VERSION 5.7 ;
BUSBITCHARS "[]" ;
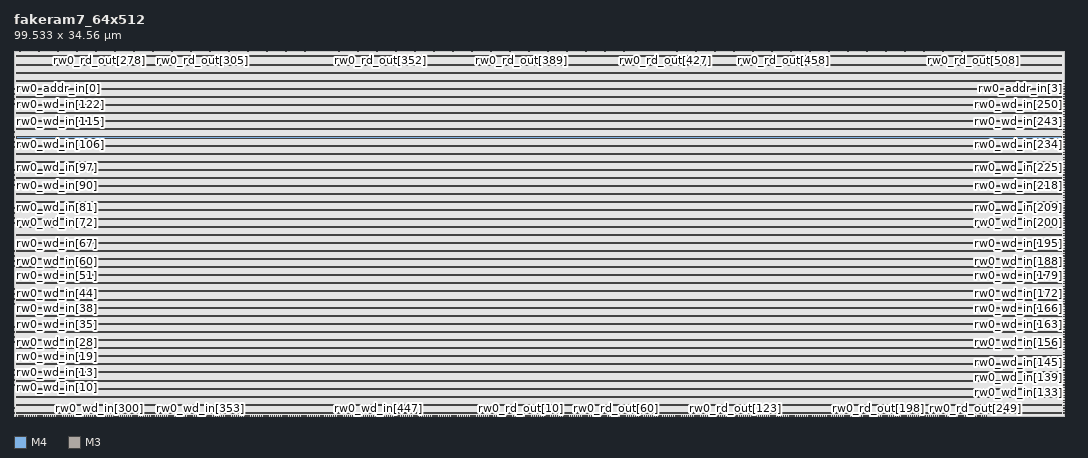
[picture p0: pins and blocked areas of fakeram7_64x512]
MACRO fakeram7_64x512
  FOREIGN fakeram7_64x512 0 0 ;
  SYMMETRY X Y R90 ;
  SIZE 99.533 BY 34.560 ;
  CLASS BLOCK ;
  PIN rw0_wd_in[0]
    DIRECTION INPUT ;
    USE SIGNAL ;
    SHAPE ABUTMENT ;
    PORT
      LAYER M4 ;
      RECT 0.000 0.276 0.072 0.300 ;
    END
  END rw0_wd_in[0]
  PIN rw0_wd_in[1]
    DIRECTION INPUT ;
    USE SIGNAL ;
    SHAPE ABUTMENT ;
    PORT
      LAYER M4 ;
      RECT 0.000 0.516 0.072 0.540 ;
    END
  END rw0_wd_in[1]
  PIN rw0_wd_in[2]
    DIRECTION INPUT ;
    USE SIGNAL ;
    SHAPE ABUTMENT ;
    PORT
      LAYER M4 ;
      RECT 0.000 0.756 0.072 0.780 ;
    END
  END rw0_wd_in[2]
  PIN rw0_wd_in[3]
    DIRECTION INPUT ;
    USE SIGNAL ;
    SHAPE ABUTMENT ;
    PORT
      LAYER M4 ;
      RECT 0.000 0.996 0.072 1.020 ;
    END
  END rw0_wd_in[3]
  PIN rw0_wd_in[4]
    DIRECTION INPUT ;
    USE SIGNAL ;
    SHAPE ABUTMENT ;
    PORT
      LAYER M4 ;
      RECT 0.000 1.236 0.072 1.260 ;
    END
  END rw0_wd_in[4]
  PIN rw0_wd_in[5]
    DIRECTION INPUT ;
    USE SIGNAL ;
    SHAPE ABUTMENT ;
    PORT
      LAYER M4 ;
      RECT 0.000 1.476 0.072 1.500 ;
    END
  END rw0_wd_in[5]
  PIN rw0_wd_in[6]
    DIRECTION INPUT ;
    USE SIGNAL ;
    SHAPE ABUTMENT ;
    PORT
      LAYER M4 ;
      RECT 0.000 1.716 0.072 1.740 ;
    END
  END rw0_wd_in[6]
  PIN rw0_wd_in[7]
    DIRECTION INPUT ;
    USE SIGNAL ;
    SHAPE ABUTMENT ;
    PORT
      LAYER M4 ;
      RECT 0.000 1.956 0.072 1.980 ;
    END
  END rw0_wd_in[7]
  PIN rw0_wd_in[8]
    DIRECTION INPUT ;
    USE SIGNAL ;
    SHAPE ABUTMENT ;
    PORT
      LAYER M4 ;
      RECT 0.000 2.196 0.072 2.220 ;
    END
  END rw0_wd_in[8]
  PIN rw0_wd_in[9]
    DIRECTION INPUT ;
    USE SIGNAL ;
    SHAPE ABUTMENT ;
    PORT
      LAYER M4 ;
      RECT 0.000 2.436 0.072 2.460 ;
    END
  END rw0_wd_in[9]
  PIN rw0_wd_in[10]
    DIRECTION INPUT ;
    USE SIGNAL ;
    SHAPE ABUTMENT ;
    PORT
      LAYER M4 ;
      RECT 0.000 2.676 0.072 2.700 ;
    END
  END rw0_wd_in[10]
  PIN rw0_wd_in[11]
    DIRECTION INPUT ;
    USE SIGNAL ;
    SHAPE ABUTMENT ;
    PORT
      LAYER M4 ;
      RECT 0.000 2.916 0.072 2.940 ;
    END
  END rw0_wd_in[11]
  PIN rw0_wd_in[12]
    DIRECTION INPUT ;
    USE SIGNAL ;
    SHAPE ABUTMENT ;
    PORT
      LAYER M4 ;
      RECT 0.000 3.156 0.072 3.180 ;
    END
  END rw0_wd_in[12]
  PIN rw0_wd_in[13]
    DIRECTION INPUT ;
    USE SIGNAL ;
    SHAPE ABUTMENT ;
    PORT
      LAYER M4 ;
      RECT 0.000 3.396 0.072 3.420 ;
    END
  END rw0_wd_in[13]
  PIN rw0_wd_in[14]
    DIRECTION INPUT ;
    USE SIGNAL ;
    SHAPE ABUTMENT ;
    PORT
      LAYER M4 ;
      RECT 0.000 3.636 0.072 3.660 ;
    END
  END rw0_wd_in[14]
  PIN rw0_wd_in[15]
    DIRECTION INPUT ;
    USE SIGNAL ;
    SHAPE ABUTMENT ;
    PORT
      LAYER M4 ;
      RECT 0.000 3.876 0.072 3.900 ;
    END
  END rw0_wd_in[15]
  PIN rw0_wd_in[16]
    DIRECTION INPUT ;
    USE SIGNAL ;
    SHAPE ABUTMENT ;
    PORT
      LAYER M4 ;
      RECT 0.000 4.116 0.072 4.140 ;
    END
  END rw0_wd_in[16]
  PIN rw0_wd_in[17]
    DIRECTION INPUT ;
    USE SIGNAL ;
    SHAPE ABUTMENT ;
    PORT
      LAYER M4 ;
      RECT 0.000 4.356 0.072 4.380 ;
    END
  END rw0_wd_in[17]
  PIN rw0_wd_in[18]
    DIRECTION INPUT ;
    USE SIGNAL ;
    SHAPE ABUTMENT ;
    PORT
      LAYER M4 ;
      RECT 0.000 4.596 0.072 4.620 ;
    END
  END rw0_wd_in[18]
  PIN rw0_wd_in[19]
    DIRECTION INPUT ;
    USE SIGNAL ;
    SHAPE ABUTMENT ;
    PORT
      LAYER M4 ;
      RECT 0.000 4.836 0.072 4.860 ;
    END
  END rw0_wd_in[19]
  PIN rw0_wd_in[20]
    DIRECTION INPUT ;
    USE SIGNAL ;
    SHAPE ABUTMENT ;
    PORT
      LAYER M4 ;
      RECT 0.000 5.076 0.072 5.100 ;
    END
  END rw0_wd_in[20]
  PIN rw0_wd_in[21]
    DIRECTION INPUT ;
    USE SIGNAL ;
    SHAPE ABUTMENT ;
    PORT
      LAYER M4 ;
      RECT 0.000 5.316 0.072 5.340 ;
    END
  END rw0_wd_in[21]
  PIN rw0_wd_in[22]
    DIRECTION INPUT ;
    USE SIGNAL ;
    SHAPE ABUTMENT ;
    PORT
      LAYER M4 ;
      RECT 0.000 5.556 0.072 5.580 ;
    END
  END rw0_wd_in[22]
  PIN rw0_wd_in[23]
    DIRECTION INPUT ;
    USE SIGNAL ;
    SHAPE ABUTMENT ;
    PORT
      LAYER M4 ;
      RECT 0.000 5.796 0.072 5.820 ;
    END
  END rw0_wd_in[23]
  PIN rw0_wd_in[24]
    DIRECTION INPUT ;
    USE SIGNAL ;
    SHAPE ABUTMENT ;
    PORT
      LAYER M4 ;
      RECT 0.000 6.036 0.072 6.060 ;
    END
  END rw0_wd_in[24]
  PIN rw0_wd_in[25]
    DIRECTION INPUT ;
    USE SIGNAL ;
    SHAPE ABUTMENT ;
    PORT
      LAYER M4 ;
      RECT 0.000 6.276 0.072 6.300 ;
    END
  END rw0_wd_in[25]
  PIN rw0_wd_in[26]
    DIRECTION INPUT ;
    USE SIGNAL ;
    SHAPE ABUTMENT ;
    PORT
      LAYER M4 ;
      RECT 0.000 6.516 0.072 6.540 ;
    END
  END rw0_wd_in[26]
  PIN rw0_wd_in[27]
    DIRECTION INPUT ;
    USE SIGNAL ;
    SHAPE ABUTMENT ;
    PORT
      LAYER M4 ;
      RECT 0.000 6.756 0.072 6.780 ;
    END
  END rw0_wd_in[27]
  PIN rw0_wd_in[28]
    DIRECTION INPUT ;
    USE SIGNAL ;
    SHAPE ABUTMENT ;
    PORT
      LAYER M4 ;
      RECT 0.000 6.996 0.072 7.020 ;
    END
  END rw0_wd_in[28]
  PIN rw0_wd_in[29]
    DIRECTION INPUT ;
    USE SIGNAL ;
    SHAPE ABUTMENT ;
    PORT
      LAYER M4 ;
      RECT 0.000 7.236 0.072 7.260 ;
    END
  END rw0_wd_in[29]
  PIN rw0_wd_in[30]
    DIRECTION INPUT ;
    USE SIGNAL ;
    SHAPE ABUTMENT ;
    PORT
      LAYER M4 ;
      RECT 0.000 7.476 0.072 7.500 ;
    END
  END rw0_wd_in[30]
  PIN rw0_wd_in[31]
    DIRECTION INPUT ;
    USE SIGNAL ;
    SHAPE ABUTMENT ;
    PORT
      LAYER M4 ;
      RECT 0.000 7.716 0.072 7.740 ;
    END
  END rw0_wd_in[31]
  PIN rw0_wd_in[32]
    DIRECTION INPUT ;
    USE SIGNAL ;
    SHAPE ABUTMENT ;
    PORT
      LAYER M4 ;
      RECT 0.000 7.956 0.072 7.980 ;
    END
  END rw0_wd_in[32]
  PIN rw0_wd_in[33]
    DIRECTION INPUT ;
    USE SIGNAL ;
    SHAPE ABUTMENT ;
    PORT
      LAYER M4 ;
      RECT 0.000 8.196 0.072 8.220 ;
    END
  END rw0_wd_in[33]
  PIN rw0_wd_in[34]
    DIRECTION INPUT ;
    USE SIGNAL ;
    SHAPE ABUTMENT ;
    PORT
      LAYER M4 ;
      RECT 0.000 8.436 0.072 8.460 ;
    END
  END rw0_wd_in[34]
  PIN rw0_wd_in[35]
    DIRECTION INPUT ;
    USE SIGNAL ;
    SHAPE ABUTMENT ;
    PORT
      LAYER M4 ;
      RECT 0.000 8.676 0.072 8.700 ;
    END
  END rw0_wd_in[35]
  PIN rw0_wd_in[36]
    DIRECTION INPUT ;
    USE SIGNAL ;
    SHAPE ABUTMENT ;
    PORT
      LAYER M4 ;
      RECT 0.000 8.916 0.072 8.940 ;
    END
  END rw0_wd_in[36]
  PIN rw0_wd_in[37]
    DIRECTION INPUT ;
    USE SIGNAL ;
    SHAPE ABUTMENT ;
    PORT
      LAYER M4 ;
      RECT 0.000 9.156 0.072 9.180 ;
    END
  END rw0_wd_in[37]
  PIN rw0_wd_in[38]
    DIRECTION INPUT ;
    USE SIGNAL ;
    SHAPE ABUTMENT ;
    PORT
      LAYER M4 ;
      RECT 0.000 9.396 0.072 9.420 ;
    END
  END rw0_wd_in[38]
  PIN rw0_wd_in[39]
    DIRECTION INPUT ;
    USE SIGNAL ;
    SHAPE ABUTMENT ;
    PORT
      LAYER M4 ;
      RECT 0.000 9.636 0.072 9.660 ;
    END
  END rw0_wd_in[39]
  PIN rw0_wd_in[40]
    DIRECTION INPUT ;
    USE SIGNAL ;
    SHAPE ABUTMENT ;
    PORT
      LAYER M4 ;
      RECT 0.000 9.876 0.072 9.900 ;
    END
  END rw0_wd_in[40]
  PIN rw0_wd_in[41]
    DIRECTION INPUT ;
    USE SIGNAL ;
    SHAPE ABUTMENT ;
    PORT
      LAYER M4 ;
      RECT 0.000 10.116 0.072 10.140 ;
    END
  END rw0_wd_in[41]
  PIN rw0_wd_in[42]
    DIRECTION INPUT ;
    USE SIGNAL ;
    SHAPE ABUTMENT ;
    PORT
      LAYER M4 ;
      RECT 0.000 10.356 0.072 10.380 ;
    END
  END rw0_wd_in[42]
  PIN rw0_wd_in[43]
    DIRECTION INPUT ;
    USE SIGNAL ;
    SHAPE ABUTMENT ;
    PORT
      LAYER M4 ;
      RECT 0.000 10.596 0.072 10.620 ;
    END
  END rw0_wd_in[43]
  PIN rw0_wd_in[44]
    DIRECTION INPUT ;
    USE SIGNAL ;
    SHAPE ABUTMENT ;
    PORT
      LAYER M4 ;
      RECT 0.000 10.836 0.072 10.860 ;
    END
  END rw0_wd_in[44]
  PIN rw0_wd_in[45]
    DIRECTION INPUT ;
    USE SIGNAL ;
    SHAPE ABUTMENT ;
    PORT
      LAYER M4 ;
      RECT 0.000 11.076 0.072 11.100 ;
    END
  END rw0_wd_in[45]
  PIN rw0_wd_in[46]
    DIRECTION INPUT ;
    USE SIGNAL ;
    SHAPE ABUTMENT ;
    PORT
      LAYER M4 ;
      RECT 0.000 11.316 0.072 11.340 ;
    END
  END rw0_wd_in[46]
  PIN rw0_wd_in[47]
    DIRECTION INPUT ;
    USE SIGNAL ;
    SHAPE ABUTMENT ;
    PORT
      LAYER M4 ;
      RECT 0.000 11.556 0.072 11.580 ;
    END
  END rw0_wd_in[47]
  PIN rw0_wd_in[48]
    DIRECTION INPUT ;
    USE SIGNAL ;
    SHAPE ABUTMENT ;
    PORT
      LAYER M4 ;
      RECT 0.000 11.796 0.072 11.820 ;
    END
  END rw0_wd_in[48]
  PIN rw0_wd_in[49]
    DIRECTION INPUT ;
    USE SIGNAL ;
    SHAPE ABUTMENT ;
    PORT
      LAYER M4 ;
      RECT 0.000 12.036 0.072 12.060 ;
    END
  END rw0_wd_in[49]
  PIN rw0_wd_in[50]
    DIRECTION INPUT ;
    USE SIGNAL ;
    SHAPE ABUTMENT ;
    PORT
      LAYER M4 ;
      RECT 0.000 12.276 0.072 12.300 ;
    END
  END rw0_wd_in[50]
  PIN rw0_wd_in[51]
    DIRECTION INPUT ;
    USE SIGNAL ;
    SHAPE ABUTMENT ;
    PORT
      LAYER M4 ;
      RECT 0.000 12.516 0.072 12.540 ;
    END
  END rw0_wd_in[51]
  PIN rw0_wd_in[52]
    DIRECTION INPUT ;
    USE SIGNAL ;
    SHAPE ABUTMENT ;
    PORT
      LAYER M4 ;
      RECT 0.000 12.756 0.072 12.780 ;
    END
  END rw0_wd_in[52]
  PIN rw0_wd_in[53]
    DIRECTION INPUT ;
    USE SIGNAL ;
    SHAPE ABUTMENT ;
    PORT
      LAYER M4 ;
      RECT 0.000 12.996 0.072 13.020 ;
    END
  END rw0_wd_in[53]
  PIN rw0_wd_in[54]
    DIRECTION INPUT ;
    USE SIGNAL ;
    SHAPE ABUTMENT ;
    PORT
      LAYER M4 ;
      RECT 0.000 13.236 0.072 13.260 ;
    END
  END rw0_wd_in[54]
  PIN rw0_wd_in[55]
    DIRECTION INPUT ;
    USE SIGNAL ;
    SHAPE ABUTMENT ;
    PORT
      LAYER M4 ;
      RECT 0.000 13.476 0.072 13.500 ;
    END
  END rw0_wd_in[55]
  PIN rw0_wd_in[56]
    DIRECTION INPUT ;
    USE SIGNAL ;
    SHAPE ABUTMENT ;
    PORT
      LAYER M4 ;
      RECT 0.000 13.716 0.072 13.740 ;
    END
  END rw0_wd_in[56]
  PIN rw0_wd_in[57]
    DIRECTION INPUT ;
    USE SIGNAL ;
    SHAPE ABUTMENT ;
    PORT
      LAYER M4 ;
      RECT 0.000 13.956 0.072 13.980 ;
    END
  END rw0_wd_in[57]
  PIN rw0_wd_in[58]
    DIRECTION INPUT ;
    USE SIGNAL ;
    SHAPE ABUTMENT ;
    PORT
      LAYER M4 ;
      RECT 0.000 14.196 0.072 14.220 ;
    END
  END rw0_wd_in[58]
  PIN rw0_wd_in[59]
    DIRECTION INPUT ;
    USE SIGNAL ;
    SHAPE ABUTMENT ;
    PORT
      LAYER M4 ;
      RECT 0.000 14.436 0.072 14.460 ;
    END
  END rw0_wd_in[59]
  PIN rw0_wd_in[60]
    DIRECTION INPUT ;
    USE SIGNAL ;
    SHAPE ABUTMENT ;
    PORT
      LAYER M4 ;
      RECT 0.000 14.676 0.072 14.700 ;
    END
  END rw0_wd_in[60]
  PIN rw0_wd_in[61]
    DIRECTION INPUT ;
    USE SIGNAL ;
    SHAPE ABUTMENT ;
    PORT
      LAYER M4 ;
      RECT 0.000 14.916 0.072 14.940 ;
    END
  END rw0_wd_in[61]
  PIN rw0_wd_in[62]
    DIRECTION INPUT ;
    USE SIGNAL ;
    SHAPE ABUTMENT ;
    PORT
      LAYER M4 ;
      RECT 0.000 15.156 0.072 15.180 ;
    END
  END rw0_wd_in[62]
  PIN rw0_wd_in[63]
    DIRECTION INPUT ;
    USE SIGNAL ;
    SHAPE ABUTMENT ;
    PORT
      LAYER M4 ;
      RECT 0.000 15.396 0.072 15.420 ;
    END
  END rw0_wd_in[63]
  PIN rw0_wd_in[64]
    DIRECTION INPUT ;
    USE SIGNAL ;
    SHAPE ABUTMENT ;
    PORT
      LAYER M4 ;
      RECT 0.000 15.636 0.072 15.660 ;
    END
  END rw0_wd_in[64]
  PIN rw0_wd_in[65]
    DIRECTION INPUT ;
    USE SIGNAL ;
    SHAPE ABUTMENT ;
    PORT
      LAYER M4 ;
      RECT 0.000 15.876 0.072 15.900 ;
    END
  END rw0_wd_in[65]
  PIN rw0_wd_in[66]
    DIRECTION INPUT ;
    USE SIGNAL ;
    SHAPE ABUTMENT ;
    PORT
      LAYER M4 ;
      RECT 0.000 16.116 0.072 16.140 ;
    END
  END rw0_wd_in[66]
  PIN rw0_wd_in[67]
    DIRECTION INPUT ;
    USE SIGNAL ;
    SHAPE ABUTMENT ;
    PORT
      LAYER M4 ;
      RECT 0.000 16.356 0.072 16.380 ;
    END
  END rw0_wd_in[67]
  PIN rw0_wd_in[68]
    DIRECTION INPUT ;
    USE SIGNAL ;
    SHAPE ABUTMENT ;
    PORT
      LAYER M4 ;
      RECT 0.000 16.596 0.072 16.620 ;
    END
  END rw0_wd_in[68]
  PIN rw0_wd_in[69]
    DIRECTION INPUT ;
    USE SIGNAL ;
    SHAPE ABUTMENT ;
    PORT
      LAYER M4 ;
      RECT 0.000 16.836 0.072 16.860 ;
    END
  END rw0_wd_in[69]
  PIN rw0_wd_in[70]
    DIRECTION INPUT ;
    USE SIGNAL ;
    SHAPE ABUTMENT ;
    PORT
      LAYER M4 ;
      RECT 0.000 17.076 0.072 17.100 ;
    END
  END rw0_wd_in[70]
  PIN rw0_wd_in[71]
    DIRECTION INPUT ;
    USE SIGNAL ;
    SHAPE ABUTMENT ;
    PORT
      LAYER M4 ;
      RECT 0.000 17.316 0.072 17.340 ;
    END
  END rw0_wd_in[71]
  PIN rw0_wd_in[72]
    DIRECTION INPUT ;
    USE SIGNAL ;
    SHAPE ABUTMENT ;
    PORT
      LAYER M4 ;
      RECT 0.000 17.556 0.072 17.580 ;
    END
  END rw0_wd_in[72]
  PIN rw0_wd_in[73]
    DIRECTION INPUT ;
    USE SIGNAL ;
    SHAPE ABUTMENT ;
    PORT
      LAYER M4 ;
      RECT 0.000 17.796 0.072 17.820 ;
    END
  END rw0_wd_in[73]
  PIN rw0_wd_in[74]
    DIRECTION INPUT ;
    USE SIGNAL ;
    SHAPE ABUTMENT ;
    PORT
      LAYER M4 ;
      RECT 0.000 18.036 0.072 18.060 ;
    END
  END rw0_wd_in[74]
  PIN rw0_wd_in[75]
    DIRECTION INPUT ;
    USE SIGNAL ;
    SHAPE ABUTMENT ;
    PORT
      LAYER M4 ;
      RECT 0.000 18.276 0.072 18.300 ;
    END
  END rw0_wd_in[75]
  PIN rw0_wd_in[76]
    DIRECTION INPUT ;
    USE SIGNAL ;
    SHAPE ABUTMENT ;
    PORT
      LAYER M4 ;
      RECT 0.000 18.516 0.072 18.540 ;
    END
  END rw0_wd_in[76]
  PIN rw0_wd_in[77]
    DIRECTION INPUT ;
    USE SIGNAL ;
    SHAPE ABUTMENT ;
    PORT
      LAYER M4 ;
      RECT 0.000 18.756 0.072 18.780 ;
    END
  END rw0_wd_in[77]
  PIN rw0_wd_in[78]
    DIRECTION INPUT ;
    USE SIGNAL ;
    SHAPE ABUTMENT ;
    PORT
      LAYER M4 ;
      RECT 0.000 18.996 0.072 19.020 ;
    END
  END rw0_wd_in[78]
  PIN rw0_wd_in[79]
    DIRECTION INPUT ;
    USE SIGNAL ;
    SHAPE ABUTMENT ;
    PORT
      LAYER M4 ;
      RECT 0.000 19.236 0.072 19.260 ;
    END
  END rw0_wd_in[79]
  PIN rw0_wd_in[80]
    DIRECTION INPUT ;
    USE SIGNAL ;
    SHAPE ABUTMENT ;
    PORT
      LAYER M4 ;
      RECT 0.000 19.476 0.072 19.500 ;
    END
  END rw0_wd_in[80]
  PIN rw0_wd_in[81]
    DIRECTION INPUT ;
    USE SIGNAL ;
    SHAPE ABUTMENT ;
    PORT
      LAYER M4 ;
      RECT 0.000 19.716 0.072 19.740 ;
    END
  END rw0_wd_in[81]
  PIN rw0_wd_in[82]
    DIRECTION INPUT ;
    USE SIGNAL ;
    SHAPE ABUTMENT ;
    PORT
      LAYER M4 ;
      RECT 0.000 19.956 0.072 19.980 ;
    END
  END rw0_wd_in[82]
  PIN rw0_wd_in[83]
    DIRECTION INPUT ;
    USE SIGNAL ;
    SHAPE ABUTMENT ;
    PORT
      LAYER M4 ;
      RECT 0.000 20.196 0.072 20.220 ;
    END
  END rw0_wd_in[83]
  PIN rw0_wd_in[84]
    DIRECTION INPUT ;
    USE SIGNAL ;
    SHAPE ABUTMENT ;
    PORT
      LAYER M4 ;
      RECT 0.000 20.436 0.072 20.460 ;
    END
  END rw0_wd_in[84]
  PIN rw0_wd_in[85]
    DIRECTION INPUT ;
    USE SIGNAL ;
    SHAPE ABUTMENT ;
    PORT
      LAYER M4 ;
      RECT 0.000 20.676 0.072 20.700 ;
    END
  END rw0_wd_in[85]
  PIN rw0_wd_in[86]
    DIRECTION INPUT ;
    USE SIGNAL ;
    SHAPE ABUTMENT ;
    PORT
      LAYER M4 ;
      RECT 0.000 20.916 0.072 20.940 ;
    END
  END rw0_wd_in[86]
  PIN rw0_wd_in[87]
    DIRECTION INPUT ;
    USE SIGNAL ;
    SHAPE ABUTMENT ;
    PORT
      LAYER M4 ;
      RECT 0.000 21.156 0.072 21.180 ;
    END
  END rw0_wd_in[87]
  PIN rw0_wd_in[88]
    DIRECTION INPUT ;
    USE SIGNAL ;
    SHAPE ABUTMENT ;
    PORT
      LAYER M4 ;
      RECT 0.000 21.396 0.072 21.420 ;
    END
  END rw0_wd_in[88]
  PIN rw0_wd_in[89]
    DIRECTION INPUT ;
    USE SIGNAL ;
    SHAPE ABUTMENT ;
    PORT
      LAYER M4 ;
      RECT 0.000 21.636 0.072 21.660 ;
    END
  END rw0_wd_in[89]
  PIN rw0_wd_in[90]
    DIRECTION INPUT ;
    USE SIGNAL ;
    SHAPE ABUTMENT ;
    PORT
      LAYER M4 ;
      RECT 0.000 21.876 0.072 21.900 ;
    END
  END rw0_wd_in[90]
  PIN rw0_wd_in[91]
    DIRECTION INPUT ;
    USE SIGNAL ;
    SHAPE ABUTMENT ;
    PORT
      LAYER M4 ;
      RECT 0.000 22.116 0.072 22.140 ;
    END
  END rw0_wd_in[91]
  PIN rw0_wd_in[92]
    DIRECTION INPUT ;
    USE SIGNAL ;
    SHAPE ABUTMENT ;
    PORT
      LAYER M4 ;
      RECT 0.000 22.356 0.072 22.380 ;
    END
  END rw0_wd_in[92]
  PIN rw0_wd_in[93]
    DIRECTION INPUT ;
    USE SIGNAL ;
    SHAPE ABUTMENT ;
    PORT
      LAYER M4 ;
      RECT 0.000 22.596 0.072 22.620 ;
    END
  END rw0_wd_in[93]
  PIN rw0_wd_in[94]
    DIRECTION INPUT ;
    USE SIGNAL ;
    SHAPE ABUTMENT ;
    PORT
      LAYER M4 ;
      RECT 0.000 22.836 0.072 22.860 ;
    END
  END rw0_wd_in[94]
  PIN rw0_wd_in[95]
    DIRECTION INPUT ;
    USE SIGNAL ;
    SHAPE ABUTMENT ;
    PORT
      LAYER M4 ;
      RECT 0.000 23.076 0.072 23.100 ;
    END
  END rw0_wd_in[95]
  PIN rw0_wd_in[96]
    DIRECTION INPUT ;
    USE SIGNAL ;
    SHAPE ABUTMENT ;
    PORT
      LAYER M4 ;
      RECT 0.000 23.316 0.072 23.340 ;
    END
  END rw0_wd_in[96]
  PIN rw0_wd_in[97]
    DIRECTION INPUT ;
    USE SIGNAL ;
    SHAPE ABUTMENT ;
    PORT
      LAYER M4 ;
      RECT 0.000 23.556 0.072 23.580 ;
    END
  END rw0_wd_in[97]
  PIN rw0_wd_in[98]
    DIRECTION INPUT ;
    USE SIGNAL ;
    SHAPE ABUTMENT ;
    PORT
      LAYER M4 ;
      RECT 0.000 23.796 0.072 23.820 ;
    END
  END rw0_wd_in[98]
  PIN rw0_wd_in[99]
    DIRECTION INPUT ;
    USE SIGNAL ;
    SHAPE ABUTMENT ;
    PORT
      LAYER M4 ;
      RECT 0.000 24.036 0.072 24.060 ;
    END
  END rw0_wd_in[99]
  PIN rw0_wd_in[100]
    DIRECTION INPUT ;
    USE SIGNAL ;
    SHAPE ABUTMENT ;
    PORT
      LAYER M4 ;
      RECT 0.000 24.276 0.072 24.300 ;
    END
  END rw0_wd_in[100]
  PIN rw0_wd_in[101]
    DIRECTION INPUT ;
    USE SIGNAL ;
    SHAPE ABUTMENT ;
    PORT
      LAYER M4 ;
      RECT 0.000 24.516 0.072 24.540 ;
    END
  END rw0_wd_in[101]
  PIN rw0_wd_in[102]
    DIRECTION INPUT ;
    USE SIGNAL ;
    SHAPE ABUTMENT ;
    PORT
      LAYER M4 ;
      RECT 0.000 24.756 0.072 24.780 ;
    END
  END rw0_wd_in[102]
  PIN rw0_wd_in[103]
    DIRECTION INPUT ;
    USE SIGNAL ;
    SHAPE ABUTMENT ;
    PORT
      LAYER M4 ;
      RECT 0.000 24.996 0.072 25.020 ;
    END
  END rw0_wd_in[103]
  PIN rw0_wd_in[104]
    DIRECTION INPUT ;
    USE SIGNAL ;
    SHAPE ABUTMENT ;
    PORT
      LAYER M4 ;
      RECT 0.000 25.236 0.072 25.260 ;
    END
  END rw0_wd_in[104]
  PIN rw0_wd_in[105]
    DIRECTION INPUT ;
    USE SIGNAL ;
    SHAPE ABUTMENT ;
    PORT
      LAYER M4 ;
      RECT 0.000 25.476 0.072 25.500 ;
    END
  END rw0_wd_in[105]
  PIN rw0_wd_in[106]
    DIRECTION INPUT ;
    USE SIGNAL ;
    SHAPE ABUTMENT ;
    PORT
      LAYER M4 ;
      RECT 0.000 25.716 0.072 25.740 ;
    END
  END rw0_wd_in[106]
  PIN rw0_wd_in[107]
    DIRECTION INPUT ;
    USE SIGNAL ;
    SHAPE ABUTMENT ;
    PORT
      LAYER M4 ;
      RECT 0.000 25.956 0.072 25.980 ;
    END
  END rw0_wd_in[107]
  PIN rw0_wd_in[108]
    DIRECTION INPUT ;
    USE SIGNAL ;
    SHAPE ABUTMENT ;
    PORT
      LAYER M4 ;
      RECT 0.000 26.196 0.072 26.220 ;
    END
  END rw0_wd_in[108]
  PIN rw0_wd_in[109]
    DIRECTION INPUT ;
    USE SIGNAL ;
    SHAPE ABUTMENT ;
    PORT
      LAYER M4 ;
      RECT 0.000 26.436 0.072 26.460 ;
    END
  END rw0_wd_in[109]
  PIN rw0_wd_in[110]
    DIRECTION INPUT ;
    USE SIGNAL ;
    SHAPE ABUTMENT ;
    PORT
      LAYER M4 ;
      RECT 0.000 26.676 0.072 26.700 ;
    END
  END rw0_wd_in[110]
  PIN rw0_wd_in[111]
    DIRECTION INPUT ;
    USE SIGNAL ;
    SHAPE ABUTMENT ;
    PORT
      LAYER M4 ;
      RECT 0.000 26.916 0.072 26.940 ;
    END
  END rw0_wd_in[111]
  PIN rw0_wd_in[112]
    DIRECTION INPUT ;
    USE SIGNAL ;
    SHAPE ABUTMENT ;
    PORT
      LAYER M4 ;
      RECT 0.000 27.156 0.072 27.180 ;
    END
  END rw0_wd_in[112]
  PIN rw0_wd_in[113]
    DIRECTION INPUT ;
    USE SIGNAL ;
    SHAPE ABUTMENT ;
    PORT
      LAYER M4 ;
      RECT 0.000 27.396 0.072 27.420 ;
    END
  END rw0_wd_in[113]
  PIN rw0_wd_in[114]
    DIRECTION INPUT ;
    USE SIGNAL ;
    SHAPE ABUTMENT ;
    PORT
      LAYER M4 ;
      RECT 0.000 27.636 0.072 27.660 ;
    END
  END rw0_wd_in[114]
  PIN rw0_wd_in[115]
    DIRECTION INPUT ;
    USE SIGNAL ;
    SHAPE ABUTMENT ;
    PORT
      LAYER M4 ;
      RECT 0.000 27.876 0.072 27.900 ;
    END
  END rw0_wd_in[115]
  PIN rw0_wd_in[116]
    DIRECTION INPUT ;
    USE SIGNAL ;
    SHAPE ABUTMENT ;
    PORT
      LAYER M4 ;
      RECT 0.000 28.116 0.072 28.140 ;
    END
  END rw0_wd_in[116]
  PIN rw0_wd_in[117]
    DIRECTION INPUT ;
    USE SIGNAL ;
    SHAPE ABUTMENT ;
    PORT
      LAYER M4 ;
      RECT 0.000 28.356 0.072 28.380 ;
    END
  END rw0_wd_in[117]
  PIN rw0_wd_in[118]
    DIRECTION INPUT ;
    USE SIGNAL ;
    SHAPE ABUTMENT ;
    PORT
      LAYER M4 ;
      RECT 0.000 28.596 0.072 28.620 ;
    END
  END rw0_wd_in[118]
  PIN rw0_wd_in[119]
    DIRECTION INPUT ;
    USE SIGNAL ;
    SHAPE ABUTMENT ;
    PORT
      LAYER M4 ;
      RECT 0.000 28.836 0.072 28.860 ;
    END
  END rw0_wd_in[119]
  PIN rw0_wd_in[120]
    DIRECTION INPUT ;
    USE SIGNAL ;
    SHAPE ABUTMENT ;
    PORT
      LAYER M4 ;
      RECT 0.000 29.076 0.072 29.100 ;
    END
  END rw0_wd_in[120]
  PIN rw0_wd_in[121]
    DIRECTION INPUT ;
    USE SIGNAL ;
    SHAPE ABUTMENT ;
    PORT
      LAYER M4 ;
      RECT 0.000 29.316 0.072 29.340 ;
    END
  END rw0_wd_in[121]
  PIN rw0_wd_in[122]
    DIRECTION INPUT ;
    USE SIGNAL ;
    SHAPE ABUTMENT ;
    PORT
      LAYER M4 ;
      RECT 0.000 29.556 0.072 29.580 ;
    END
  END rw0_wd_in[122]
  PIN rw0_wd_in[123]
    DIRECTION INPUT ;
    USE SIGNAL ;
    SHAPE ABUTMENT ;
    PORT
      LAYER M4 ;
      RECT 0.000 29.796 0.072 29.820 ;
    END
  END rw0_wd_in[123]
  PIN rw0_wd_in[124]
    DIRECTION INPUT ;
    USE SIGNAL ;
    SHAPE ABUTMENT ;
    PORT
      LAYER M4 ;
      RECT 0.000 30.036 0.072 30.060 ;
    END
  END rw0_wd_in[124]
  PIN rw0_wd_in[125]
    DIRECTION INPUT ;
    USE SIGNAL ;
    SHAPE ABUTMENT ;
    PORT
      LAYER M4 ;
      RECT 0.000 30.276 0.072 30.300 ;
    END
  END rw0_wd_in[125]
  PIN rw0_wd_in[126]
    DIRECTION INPUT ;
    USE SIGNAL ;
    SHAPE ABUTMENT ;
    PORT
      LAYER M4 ;
      RECT 0.000 30.516 0.072 30.540 ;
    END
  END rw0_wd_in[126]
  PIN rw0_wd_in[127]
    DIRECTION INPUT ;
    USE SIGNAL ;
    SHAPE ABUTMENT ;
    PORT
      LAYER M4 ;
      RECT 0.000 30.756 0.072 30.780 ;
    END
  END rw0_wd_in[127]
  PIN rw0_wd_in[128]
    DIRECTION INPUT ;
    USE SIGNAL ;
    SHAPE ABUTMENT ;
    PORT
      LAYER M4 ;
      RECT 99.461 0.276 99.533 0.300 ;
    END
  END rw0_wd_in[128]
  PIN rw0_wd_in[129]
    DIRECTION INPUT ;
    USE SIGNAL ;
    SHAPE ABUTMENT ;
    PORT
      LAYER M4 ;
      RECT 99.461 0.516 99.533 0.540 ;
    END
  END rw0_wd_in[129]
  PIN rw0_wd_in[130]
    DIRECTION INPUT ;
    USE SIGNAL ;
    SHAPE ABUTMENT ;
    PORT
      LAYER M4 ;
      RECT 99.461 0.756 99.533 0.780 ;
    END
  END rw0_wd_in[130]
  PIN rw0_wd_in[131]
    DIRECTION INPUT ;
    USE SIGNAL ;
    SHAPE ABUTMENT ;
    PORT
      LAYER M4 ;
      RECT 99.461 0.996 99.533 1.020 ;
    END
  END rw0_wd_in[131]
  PIN rw0_wd_in[132]
    DIRECTION INPUT ;
    USE SIGNAL ;
    SHAPE ABUTMENT ;
    PORT
      LAYER M4 ;
      RECT 99.461 1.236 99.533 1.260 ;
    END
  END rw0_wd_in[132]
  PIN rw0_wd_in[133]
    DIRECTION INPUT ;
    USE SIGNAL ;
    SHAPE ABUTMENT ;
    PORT
      LAYER M4 ;
      RECT 99.461 1.476 99.533 1.500 ;
    END
  END rw0_wd_in[133]
  PIN rw0_wd_in[134]
    DIRECTION INPUT ;
    USE SIGNAL ;
    SHAPE ABUTMENT ;
    PORT
      LAYER M4 ;
      RECT 99.461 1.716 99.533 1.740 ;
    END
  END rw0_wd_in[134]
  PIN rw0_wd_in[135]
    DIRECTION INPUT ;
    USE SIGNAL ;
    SHAPE ABUTMENT ;
    PORT
      LAYER M4 ;
      RECT 99.461 1.956 99.533 1.980 ;
    END
  END rw0_wd_in[135]
  PIN rw0_wd_in[136]
    DIRECTION INPUT ;
    USE SIGNAL ;
    SHAPE ABUTMENT ;
    PORT
      LAYER M4 ;
      RECT 99.461 2.196 99.533 2.220 ;
    END
  END rw0_wd_in[136]
  PIN rw0_wd_in[137]
    DIRECTION INPUT ;
    USE SIGNAL ;
    SHAPE ABUTMENT ;
    PORT
      LAYER M4 ;
      RECT 99.461 2.436 99.533 2.460 ;
    END
  END rw0_wd_in[137]
  PIN rw0_wd_in[138]
    DIRECTION INPUT ;
    USE SIGNAL ;
    SHAPE ABUTMENT ;
    PORT
      LAYER M4 ;
      RECT 99.461 2.676 99.533 2.700 ;
    END
  END rw0_wd_in[138]
  PIN rw0_wd_in[139]
    DIRECTION INPUT ;
    USE SIGNAL ;
    SHAPE ABUTMENT ;
    PORT
      LAYER M4 ;
      RECT 99.461 2.916 99.533 2.940 ;
    END
  END rw0_wd_in[139]
  PIN rw0_wd_in[140]
    DIRECTION INPUT ;
    USE SIGNAL ;
    SHAPE ABUTMENT ;
    PORT
      LAYER M4 ;
      RECT 99.461 3.156 99.533 3.180 ;
    END
  END rw0_wd_in[140]
  PIN rw0_wd_in[141]
    DIRECTION INPUT ;
    USE SIGNAL ;
    SHAPE ABUTMENT ;
    PORT
      LAYER M4 ;
      RECT 99.461 3.396 99.533 3.420 ;
    END
  END rw0_wd_in[141]
  PIN rw0_wd_in[142]
    DIRECTION INPUT ;
    USE SIGNAL ;
    SHAPE ABUTMENT ;
    PORT
      LAYER M4 ;
      RECT 99.461 3.636 99.533 3.660 ;
    END
  END rw0_wd_in[142]
  PIN rw0_wd_in[143]
    DIRECTION INPUT ;
    USE SIGNAL ;
    SHAPE ABUTMENT ;
    PORT
      LAYER M4 ;
      RECT 99.461 3.876 99.533 3.900 ;
    END
  END rw0_wd_in[143]
  PIN rw0_wd_in[144]
    DIRECTION INPUT ;
    USE SIGNAL ;
    SHAPE ABUTMENT ;
    PORT
      LAYER M4 ;
      RECT 99.461 4.116 99.533 4.140 ;
    END
  END rw0_wd_in[144]
  PIN rw0_wd_in[145]
    DIRECTION INPUT ;
    USE SIGNAL ;
    SHAPE ABUTMENT ;
    PORT
      LAYER M4 ;
      RECT 99.461 4.356 99.533 4.380 ;
    END
  END rw0_wd_in[145]
  PIN rw0_wd_in[146]
    DIRECTION INPUT ;
    USE SIGNAL ;
    SHAPE ABUTMENT ;
    PORT
      LAYER M4 ;
      RECT 99.461 4.596 99.533 4.620 ;
    END
  END rw0_wd_in[146]
  PIN rw0_wd_in[147]
    DIRECTION INPUT ;
    USE SIGNAL ;
    SHAPE ABUTMENT ;
    PORT
      LAYER M4 ;
      RECT 99.461 4.836 99.533 4.860 ;
    END
  END rw0_wd_in[147]
  PIN rw0_wd_in[148]
    DIRECTION INPUT ;
    USE SIGNAL ;
    SHAPE ABUTMENT ;
    PORT
      LAYER M4 ;
      RECT 99.461 5.076 99.533 5.100 ;
    END
  END rw0_wd_in[148]
  PIN rw0_wd_in[149]
    DIRECTION INPUT ;
    USE SIGNAL ;
    SHAPE ABUTMENT ;
    PORT
      LAYER M4 ;
      RECT 99.461 5.316 99.533 5.340 ;
    END
  END rw0_wd_in[149]
  PIN rw0_wd_in[150]
    DIRECTION INPUT ;
    USE SIGNAL ;
    SHAPE ABUTMENT ;
    PORT
      LAYER M4 ;
      RECT 99.461 5.556 99.533 5.580 ;
    END
  END rw0_wd_in[150]
  PIN rw0_wd_in[151]
    DIRECTION INPUT ;
    USE SIGNAL ;
    SHAPE ABUTMENT ;
    PORT
      LAYER M4 ;
      RECT 99.461 5.796 99.533 5.820 ;
    END
  END rw0_wd_in[151]
  PIN rw0_wd_in[152]
    DIRECTION INPUT ;
    USE SIGNAL ;
    SHAPE ABUTMENT ;
    PORT
      LAYER M4 ;
      RECT 99.461 6.036 99.533 6.060 ;
    END
  END rw0_wd_in[152]
  PIN rw0_wd_in[153]
    DIRECTION INPUT ;
    USE SIGNAL ;
    SHAPE ABUTMENT ;
    PORT
      LAYER M4 ;
      RECT 99.461 6.276 99.533 6.300 ;
    END
  END rw0_wd_in[153]
  PIN rw0_wd_in[154]
    DIRECTION INPUT ;
    USE SIGNAL ;
    SHAPE ABUTMENT ;
    PORT
      LAYER M4 ;
      RECT 99.461 6.516 99.533 6.540 ;
    END
  END rw0_wd_in[154]
  PIN rw0_wd_in[155]
    DIRECTION INPUT ;
    USE SIGNAL ;
    SHAPE ABUTMENT ;
    PORT
      LAYER M4 ;
      RECT 99.461 6.756 99.533 6.780 ;
    END
  END rw0_wd_in[155]
  PIN rw0_wd_in[156]
    DIRECTION INPUT ;
    USE SIGNAL ;
    SHAPE ABUTMENT ;
    PORT
      LAYER M4 ;
      RECT 99.461 6.996 99.533 7.020 ;
    END
  END rw0_wd_in[156]
  PIN rw0_wd_in[157]
    DIRECTION INPUT ;
    USE SIGNAL ;
    SHAPE ABUTMENT ;
    PORT
      LAYER M4 ;
      RECT 99.461 7.236 99.533 7.260 ;
    END
  END rw0_wd_in[157]
  PIN rw0_wd_in[158]
    DIRECTION INPUT ;
    USE SIGNAL ;
    SHAPE ABUTMENT ;
    PORT
      LAYER M4 ;
      RECT 99.461 7.476 99.533 7.500 ;
    END
  END rw0_wd_in[158]
  PIN rw0_wd_in[159]
    DIRECTION INPUT ;
    USE SIGNAL ;
    SHAPE ABUTMENT ;
    PORT
      LAYER M4 ;
      RECT 99.461 7.716 99.533 7.740 ;
    END
  END rw0_wd_in[159]
  PIN rw0_wd_in[160]
    DIRECTION INPUT ;
    USE SIGNAL ;
    SHAPE ABUTMENT ;
    PORT
      LAYER M4 ;
      RECT 99.461 7.956 99.533 7.980 ;
    END
  END rw0_wd_in[160]
  PIN rw0_wd_in[161]
    DIRECTION INPUT ;
    USE SIGNAL ;
    SHAPE ABUTMENT ;
    PORT
      LAYER M4 ;
      RECT 99.461 8.196 99.533 8.220 ;
    END
  END rw0_wd_in[161]
  PIN rw0_wd_in[162]
    DIRECTION INPUT ;
    USE SIGNAL ;
    SHAPE ABUTMENT ;
    PORT
      LAYER M4 ;
      RECT 99.461 8.436 99.533 8.460 ;
    END
  END rw0_wd_in[162]
  PIN rw0_wd_in[163]
    DIRECTION INPUT ;
    USE SIGNAL ;
    SHAPE ABUTMENT ;
    PORT
      LAYER M4 ;
      RECT 99.461 8.676 99.533 8.700 ;
    END
  END rw0_wd_in[163]
  PIN rw0_wd_in[164]
    DIRECTION INPUT ;
    USE SIGNAL ;
    SHAPE ABUTMENT ;
    PORT
      LAYER M4 ;
      RECT 99.461 8.916 99.533 8.940 ;
    END
  END rw0_wd_in[164]
  PIN rw0_wd_in[165]
    DIRECTION INPUT ;
    USE SIGNAL ;
    SHAPE ABUTMENT ;
    PORT
      LAYER M4 ;
      RECT 99.461 9.156 99.533 9.180 ;
    END
  END rw0_wd_in[165]
  PIN rw0_wd_in[166]
    DIRECTION INPUT ;
    USE SIGNAL ;
    SHAPE ABUTMENT ;
    PORT
      LAYER M4 ;
      RECT 99.461 9.396 99.533 9.420 ;
    END
  END rw0_wd_in[166]
  PIN rw0_wd_in[167]
    DIRECTION INPUT ;
    USE SIGNAL ;
    SHAPE ABUTMENT ;
    PORT
      LAYER M4 ;
      RECT 99.461 9.636 99.533 9.660 ;
    END
  END rw0_wd_in[167]
  PIN rw0_wd_in[168]
    DIRECTION INPUT ;
    USE SIGNAL ;
    SHAPE ABUTMENT ;
    PORT
      LAYER M4 ;
      RECT 99.461 9.876 99.533 9.900 ;
    END
  END rw0_wd_in[168]
  PIN rw0_wd_in[169]
    DIRECTION INPUT ;
    USE SIGNAL ;
    SHAPE ABUTMENT ;
    PORT
      LAYER M4 ;
      RECT 99.461 10.116 99.533 10.140 ;
    END
  END rw0_wd_in[169]
  PIN rw0_wd_in[170]
    DIRECTION INPUT ;
    USE SIGNAL ;
    SHAPE ABUTMENT ;
    PORT
      LAYER M4 ;
      RECT 99.461 10.356 99.533 10.380 ;
    END
  END rw0_wd_in[170]
  PIN rw0_wd_in[171]
    DIRECTION INPUT ;
    USE SIGNAL ;
    SHAPE ABUTMENT ;
    PORT
      LAYER M4 ;
      RECT 99.461 10.596 99.533 10.620 ;
    END
  END rw0_wd_in[171]
  PIN rw0_wd_in[172]
    DIRECTION INPUT ;
    USE SIGNAL ;
    SHAPE ABUTMENT ;
    PORT
      LAYER M4 ;
      RECT 99.461 10.836 99.533 10.860 ;
    END
  END rw0_wd_in[172]
  PIN rw0_wd_in[173]
    DIRECTION INPUT ;
    USE SIGNAL ;
    SHAPE ABUTMENT ;
    PORT
      LAYER M4 ;
      RECT 99.461 11.076 99.533 11.100 ;
    END
  END rw0_wd_in[173]
  PIN rw0_wd_in[174]
    DIRECTION INPUT ;
    USE SIGNAL ;
    SHAPE ABUTMENT ;
    PORT
      LAYER M4 ;
      RECT 99.461 11.316 99.533 11.340 ;
    END
  END rw0_wd_in[174]
  PIN rw0_wd_in[175]
    DIRECTION INPUT ;
    USE SIGNAL ;
    SHAPE ABUTMENT ;
    PORT
      LAYER M4 ;
      RECT 99.461 11.556 99.533 11.580 ;
    END
  END rw0_wd_in[175]
  PIN rw0_wd_in[176]
    DIRECTION INPUT ;
    USE SIGNAL ;
    SHAPE ABUTMENT ;
    PORT
      LAYER M4 ;
      RECT 99.461 11.796 99.533 11.820 ;
    END
  END rw0_wd_in[176]
  PIN rw0_wd_in[177]
    DIRECTION INPUT ;
    USE SIGNAL ;
    SHAPE ABUTMENT ;
    PORT
      LAYER M4 ;
      RECT 99.461 12.036 99.533 12.060 ;
    END
  END rw0_wd_in[177]
  PIN rw0_wd_in[178]
    DIRECTION INPUT ;
    USE SIGNAL ;
    SHAPE ABUTMENT ;
    PORT
      LAYER M4 ;
      RECT 99.461 12.276 99.533 12.300 ;
    END
  END rw0_wd_in[178]
  PIN rw0_wd_in[179]
    DIRECTION INPUT ;
    USE SIGNAL ;
    SHAPE ABUTMENT ;
    PORT
      LAYER M4 ;
      RECT 99.461 12.516 99.533 12.540 ;
    END
  END rw0_wd_in[179]
  PIN rw0_wd_in[180]
    DIRECTION INPUT ;
    USE SIGNAL ;
    SHAPE ABUTMENT ;
    PORT
      LAYER M4 ;
      RECT 99.461 12.756 99.533 12.780 ;
    END
  END rw0_wd_in[180]
  PIN rw0_wd_in[181]
    DIRECTION INPUT ;
    USE SIGNAL ;
    SHAPE ABUTMENT ;
    PORT
      LAYER M4 ;
      RECT 99.461 12.996 99.533 13.020 ;
    END
  END rw0_wd_in[181]
  PIN rw0_wd_in[182]
    DIRECTION INPUT ;
    USE SIGNAL ;
    SHAPE ABUTMENT ;
    PORT
      LAYER M4 ;
      RECT 99.461 13.236 99.533 13.260 ;
    END
  END rw0_wd_in[182]
  PIN rw0_wd_in[183]
    DIRECTION INPUT ;
    USE SIGNAL ;
    SHAPE ABUTMENT ;
    PORT
      LAYER M4 ;
      RECT 99.461 13.476 99.533 13.500 ;
    END
  END rw0_wd_in[183]
  PIN rw0_wd_in[184]
    DIRECTION INPUT ;
    USE SIGNAL ;
    SHAPE ABUTMENT ;
    PORT
      LAYER M4 ;
      RECT 99.461 13.716 99.533 13.740 ;
    END
  END rw0_wd_in[184]
  PIN rw0_wd_in[185]
    DIRECTION INPUT ;
    USE SIGNAL ;
    SHAPE ABUTMENT ;
    PORT
      LAYER M4 ;
      RECT 99.461 13.956 99.533 13.980 ;
    END
  END rw0_wd_in[185]
  PIN rw0_wd_in[186]
    DIRECTION INPUT ;
    USE SIGNAL ;
    SHAPE ABUTMENT ;
    PORT
      LAYER M4 ;
      RECT 99.461 14.196 99.533 14.220 ;
    END
  END rw0_wd_in[186]
  PIN rw0_wd_in[187]
    DIRECTION INPUT ;
    USE SIGNAL ;
    SHAPE ABUTMENT ;
    PORT
      LAYER M4 ;
      RECT 99.461 14.436 99.533 14.460 ;
    END
  END rw0_wd_in[187]
  PIN rw0_wd_in[188]
    DIRECTION INPUT ;
    USE SIGNAL ;
    SHAPE ABUTMENT ;
    PORT
      LAYER M4 ;
      RECT 99.461 14.676 99.533 14.700 ;
    END
  END rw0_wd_in[188]
  PIN rw0_wd_in[189]
    DIRECTION INPUT ;
    USE SIGNAL ;
    SHAPE ABUTMENT ;
    PORT
      LAYER M4 ;
      RECT 99.461 14.916 99.533 14.940 ;
    END
  END rw0_wd_in[189]
  PIN rw0_wd_in[190]
    DIRECTION INPUT ;
    USE SIGNAL ;
    SHAPE ABUTMENT ;
    PORT
      LAYER M4 ;
      RECT 99.461 15.156 99.533 15.180 ;
    END
  END rw0_wd_in[190]
  PIN rw0_wd_in[191]
    DIRECTION INPUT ;
    USE SIGNAL ;
    SHAPE ABUTMENT ;
    PORT
      LAYER M4 ;
      RECT 99.461 15.396 99.533 15.420 ;
    END
  END rw0_wd_in[191]
  PIN rw0_wd_in[192]
    DIRECTION INPUT ;
    USE SIGNAL ;
    SHAPE ABUTMENT ;
    PORT
      LAYER M4 ;
      RECT 99.461 15.636 99.533 15.660 ;
    END
  END rw0_wd_in[192]
  PIN rw0_wd_in[193]
    DIRECTION INPUT ;
    USE SIGNAL ;
    SHAPE ABUTMENT ;
    PORT
      LAYER M4 ;
      RECT 99.461 15.876 99.533 15.900 ;
    END
  END rw0_wd_in[193]
  PIN rw0_wd_in[194]
    DIRECTION INPUT ;
    USE SIGNAL ;
    SHAPE ABUTMENT ;
    PORT
      LAYER M4 ;
      RECT 99.461 16.116 99.533 16.140 ;
    END
  END rw0_wd_in[194]
  PIN rw0_wd_in[195]
    DIRECTION INPUT ;
    USE SIGNAL ;
    SHAPE ABUTMENT ;
    PORT
      LAYER M4 ;
      RECT 99.461 16.356 99.533 16.380 ;
    END
  END rw0_wd_in[195]
  PIN rw0_wd_in[196]
    DIRECTION INPUT ;
    USE SIGNAL ;
    SHAPE ABUTMENT ;
    PORT
      LAYER M4 ;
      RECT 99.461 16.596 99.533 16.620 ;
    END
  END rw0_wd_in[196]
  PIN rw0_wd_in[197]
    DIRECTION INPUT ;
    USE SIGNAL ;
    SHAPE ABUTMENT ;
    PORT
      LAYER M4 ;
      RECT 99.461 16.836 99.533 16.860 ;
    END
  END rw0_wd_in[197]
  PIN rw0_wd_in[198]
    DIRECTION INPUT ;
    USE SIGNAL ;
    SHAPE ABUTMENT ;
    PORT
      LAYER M4 ;
      RECT 99.461 17.076 99.533 17.100 ;
    END
  END rw0_wd_in[198]
  PIN rw0_wd_in[199]
    DIRECTION INPUT ;
    USE SIGNAL ;
    SHAPE ABUTMENT ;
    PORT
      LAYER M4 ;
      RECT 99.461 17.316 99.533 17.340 ;
    END
  END rw0_wd_in[199]
  PIN rw0_wd_in[200]
    DIRECTION INPUT ;
    USE SIGNAL ;
    SHAPE ABUTMENT ;
    PORT
      LAYER M4 ;
      RECT 99.461 17.556 99.533 17.580 ;
    END
  END rw0_wd_in[200]
  PIN rw0_wd_in[201]
    DIRECTION INPUT ;
    USE SIGNAL ;
    SHAPE ABUTMENT ;
    PORT
      LAYER M4 ;
      RECT 99.461 17.796 99.533 17.820 ;
    END
  END rw0_wd_in[201]
  PIN rw0_wd_in[202]
    DIRECTION INPUT ;
    USE SIGNAL ;
    SHAPE ABUTMENT ;
    PORT
      LAYER M4 ;
      RECT 99.461 18.036 99.533 18.060 ;
    END
  END rw0_wd_in[202]
  PIN rw0_wd_in[203]
    DIRECTION INPUT ;
    USE SIGNAL ;
    SHAPE ABUTMENT ;
    PORT
      LAYER M4 ;
      RECT 99.461 18.276 99.533 18.300 ;
    END
  END rw0_wd_in[203]
  PIN rw0_wd_in[204]
    DIRECTION INPUT ;
    USE SIGNAL ;
    SHAPE ABUTMENT ;
    PORT
      LAYER M4 ;
      RECT 99.461 18.516 99.533 18.540 ;
    END
  END rw0_wd_in[204]
  PIN rw0_wd_in[205]
    DIRECTION INPUT ;
    USE SIGNAL ;
    SHAPE ABUTMENT ;
    PORT
      LAYER M4 ;
      RECT 99.461 18.756 99.533 18.780 ;
    END
  END rw0_wd_in[205]
  PIN rw0_wd_in[206]
    DIRECTION INPUT ;
    USE SIGNAL ;
    SHAPE ABUTMENT ;
    PORT
      LAYER M4 ;
      RECT 99.461 18.996 99.533 19.020 ;
    END
  END rw0_wd_in[206]
  PIN rw0_wd_in[207]
    DIRECTION INPUT ;
    USE SIGNAL ;
    SHAPE ABUTMENT ;
    PORT
      LAYER M4 ;
      RECT 99.461 19.236 99.533 19.260 ;
    END
  END rw0_wd_in[207]
  PIN rw0_wd_in[208]
    DIRECTION INPUT ;
    USE SIGNAL ;
    SHAPE ABUTMENT ;
    PORT
      LAYER M4 ;
      RECT 99.461 19.476 99.533 19.500 ;
    END
  END rw0_wd_in[208]
  PIN rw0_wd_in[209]
    DIRECTION INPUT ;
    USE SIGNAL ;
    SHAPE ABUTMENT ;
    PORT
      LAYER M4 ;
      RECT 99.461 19.716 99.533 19.740 ;
    END
  END rw0_wd_in[209]
  PIN rw0_wd_in[210]
    DIRECTION INPUT ;
    USE SIGNAL ;
    SHAPE ABUTMENT ;
    PORT
      LAYER M4 ;
      RECT 99.461 19.956 99.533 19.980 ;
    END
  END rw0_wd_in[210]
  PIN rw0_wd_in[211]
    DIRECTION INPUT ;
    USE SIGNAL ;
    SHAPE ABUTMENT ;
    PORT
      LAYER M4 ;
      RECT 99.461 20.196 99.533 20.220 ;
    END
  END rw0_wd_in[211]
  PIN rw0_wd_in[212]
    DIRECTION INPUT ;
    USE SIGNAL ;
    SHAPE ABUTMENT ;
    PORT
      LAYER M4 ;
      RECT 99.461 20.436 99.533 20.460 ;
    END
  END rw0_wd_in[212]
  PIN rw0_wd_in[213]
    DIRECTION INPUT ;
    USE SIGNAL ;
    SHAPE ABUTMENT ;
    PORT
      LAYER M4 ;
      RECT 99.461 20.676 99.533 20.700 ;
    END
  END rw0_wd_in[213]
  PIN rw0_wd_in[214]
    DIRECTION INPUT ;
    USE SIGNAL ;
    SHAPE ABUTMENT ;
    PORT
      LAYER M4 ;
      RECT 99.461 20.916 99.533 20.940 ;
    END
  END rw0_wd_in[214]
  PIN rw0_wd_in[215]
    DIRECTION INPUT ;
    USE SIGNAL ;
    SHAPE ABUTMENT ;
    PORT
      LAYER M4 ;
      RECT 99.461 21.156 99.533 21.180 ;
    END
  END rw0_wd_in[215]
  PIN rw0_wd_in[216]
    DIRECTION INPUT ;
    USE SIGNAL ;
    SHAPE ABUTMENT ;
    PORT
      LAYER M4 ;
      RECT 99.461 21.396 99.533 21.420 ;
    END
  END rw0_wd_in[216]
  PIN rw0_wd_in[217]
    DIRECTION INPUT ;
    USE SIGNAL ;
    SHAPE ABUTMENT ;
    PORT
      LAYER M4 ;
      RECT 99.461 21.636 99.533 21.660 ;
    END
  END rw0_wd_in[217]
  PIN rw0_wd_in[218]
    DIRECTION INPUT ;
    USE SIGNAL ;
    SHAPE ABUTMENT ;
    PORT
      LAYER M4 ;
      RECT 99.461 21.876 99.533 21.900 ;
    END
  END rw0_wd_in[218]
  PIN rw0_wd_in[219]
    DIRECTION INPUT ;
    USE SIGNAL ;
    SHAPE ABUTMENT ;
    PORT
      LAYER M4 ;
      RECT 99.461 22.116 99.533 22.140 ;
    END
  END rw0_wd_in[219]
  PIN rw0_wd_in[220]
    DIRECTION INPUT ;
    USE SIGNAL ;
    SHAPE ABUTMENT ;
    PORT
      LAYER M4 ;
      RECT 99.461 22.356 99.533 22.380 ;
    END
  END rw0_wd_in[220]
  PIN rw0_wd_in[221]
    DIRECTION INPUT ;
    USE SIGNAL ;
    SHAPE ABUTMENT ;
    PORT
      LAYER M4 ;
      RECT 99.461 22.596 99.533 22.620 ;
    END
  END rw0_wd_in[221]
  PIN rw0_wd_in[222]
    DIRECTION INPUT ;
    USE SIGNAL ;
    SHAPE ABUTMENT ;
    PORT
      LAYER M4 ;
      RECT 99.461 22.836 99.533 22.860 ;
    END
  END rw0_wd_in[222]
  PIN rw0_wd_in[223]
    DIRECTION INPUT ;
    USE SIGNAL ;
    SHAPE ABUTMENT ;
    PORT
      LAYER M4 ;
      RECT 99.461 23.076 99.533 23.100 ;
    END
  END rw0_wd_in[223]
  PIN rw0_wd_in[224]
    DIRECTION INPUT ;
    USE SIGNAL ;
    SHAPE ABUTMENT ;
    PORT
      LAYER M4 ;
      RECT 99.461 23.316 99.533 23.340 ;
    END
  END rw0_wd_in[224]
  PIN rw0_wd_in[225]
    DIRECTION INPUT ;
    USE SIGNAL ;
    SHAPE ABUTMENT ;
    PORT
      LAYER M4 ;
      RECT 99.461 23.556 99.533 23.580 ;
    END
  END rw0_wd_in[225]
  PIN rw0_wd_in[226]
    DIRECTION INPUT ;
    USE SIGNAL ;
    SHAPE ABUTMENT ;
    PORT
      LAYER M4 ;
      RECT 99.461 23.796 99.533 23.820 ;
    END
  END rw0_wd_in[226]
  PIN rw0_wd_in[227]
    DIRECTION INPUT ;
    USE SIGNAL ;
    SHAPE ABUTMENT ;
    PORT
      LAYER M4 ;
      RECT 99.461 24.036 99.533 24.060 ;
    END
  END rw0_wd_in[227]
  PIN rw0_wd_in[228]
    DIRECTION INPUT ;
    USE SIGNAL ;
    SHAPE ABUTMENT ;
    PORT
      LAYER M4 ;
      RECT 99.461 24.276 99.533 24.300 ;
    END
  END rw0_wd_in[228]
  PIN rw0_wd_in[229]
    DIRECTION INPUT ;
    USE SIGNAL ;
    SHAPE ABUTMENT ;
    PORT
      LAYER M4 ;
      RECT 99.461 24.516 99.533 24.540 ;
    END
  END rw0_wd_in[229]
  PIN rw0_wd_in[230]
    DIRECTION INPUT ;
    USE SIGNAL ;
    SHAPE ABUTMENT ;
    PORT
      LAYER M4 ;
      RECT 99.461 24.756 99.533 24.780 ;
    END
  END rw0_wd_in[230]
  PIN rw0_wd_in[231]
    DIRECTION INPUT ;
    USE SIGNAL ;
    SHAPE ABUTMENT ;
    PORT
      LAYER M4 ;
      RECT 99.461 24.996 99.533 25.020 ;
    END
  END rw0_wd_in[231]
  PIN rw0_wd_in[232]
    DIRECTION INPUT ;
    USE SIGNAL ;
    SHAPE ABUTMENT ;
    PORT
      LAYER M4 ;
      RECT 99.461 25.236 99.533 25.260 ;
    END
  END rw0_wd_in[232]
  PIN rw0_wd_in[233]
    DIRECTION INPUT ;
    USE SIGNAL ;
    SHAPE ABUTMENT ;
    PORT
      LAYER M4 ;
      RECT 99.461 25.476 99.533 25.500 ;
    END
  END rw0_wd_in[233]
  PIN rw0_wd_in[234]
    DIRECTION INPUT ;
    USE SIGNAL ;
    SHAPE ABUTMENT ;
    PORT
      LAYER M4 ;
      RECT 99.461 25.716 99.533 25.740 ;
    END
  END rw0_wd_in[234]
  PIN rw0_wd_in[235]
    DIRECTION INPUT ;
    USE SIGNAL ;
    SHAPE ABUTMENT ;
    PORT
      LAYER M4 ;
      RECT 99.461 25.956 99.533 25.980 ;
    END
  END rw0_wd_in[235]
  PIN rw0_wd_in[236]
    DIRECTION INPUT ;
    USE SIGNAL ;
    SHAPE ABUTMENT ;
    PORT
      LAYER M4 ;
      RECT 99.461 26.196 99.533 26.220 ;
    END
  END rw0_wd_in[236]
  PIN rw0_wd_in[237]
    DIRECTION INPUT ;
    USE SIGNAL ;
    SHAPE ABUTMENT ;
    PORT
      LAYER M4 ;
      RECT 99.461 26.436 99.533 26.460 ;
    END
  END rw0_wd_in[237]
  PIN rw0_wd_in[238]
    DIRECTION INPUT ;
    USE SIGNAL ;
    SHAPE ABUTMENT ;
    PORT
      LAYER M4 ;
      RECT 99.461 26.676 99.533 26.700 ;
    END
  END rw0_wd_in[238]
  PIN rw0_wd_in[239]
    DIRECTION INPUT ;
    USE SIGNAL ;
    SHAPE ABUTMENT ;
    PORT
      LAYER M4 ;
      RECT 99.461 26.916 99.533 26.940 ;
    END
  END rw0_wd_in[239]
  PIN rw0_wd_in[240]
    DIRECTION INPUT ;
    USE SIGNAL ;
    SHAPE ABUTMENT ;
    PORT
      LAYER M4 ;
      RECT 99.461 27.156 99.533 27.180 ;
    END
  END rw0_wd_in[240]
  PIN rw0_wd_in[241]
    DIRECTION INPUT ;
    USE SIGNAL ;
    SHAPE ABUTMENT ;
    PORT
      LAYER M4 ;
      RECT 99.461 27.396 99.533 27.420 ;
    END
  END rw0_wd_in[241]
  PIN rw0_wd_in[242]
    DIRECTION INPUT ;
    USE SIGNAL ;
    SHAPE ABUTMENT ;
    PORT
      LAYER M4 ;
      RECT 99.461 27.636 99.533 27.660 ;
    END
  END rw0_wd_in[242]
  PIN rw0_wd_in[243]
    DIRECTION INPUT ;
    USE SIGNAL ;
    SHAPE ABUTMENT ;
    PORT
      LAYER M4 ;
      RECT 99.461 27.876 99.533 27.900 ;
    END
  END rw0_wd_in[243]
  PIN rw0_wd_in[244]
    DIRECTION INPUT ;
    USE SIGNAL ;
    SHAPE ABUTMENT ;
    PORT
      LAYER M4 ;
      RECT 99.461 28.116 99.533 28.140 ;
    END
  END rw0_wd_in[244]
  PIN rw0_wd_in[245]
    DIRECTION INPUT ;
    USE SIGNAL ;
    SHAPE ABUTMENT ;
    PORT
      LAYER M4 ;
      RECT 99.461 28.356 99.533 28.380 ;
    END
  END rw0_wd_in[245]
  PIN rw0_wd_in[246]
    DIRECTION INPUT ;
    USE SIGNAL ;
    SHAPE ABUTMENT ;
    PORT
      LAYER M4 ;
      RECT 99.461 28.596 99.533 28.620 ;
    END
  END rw0_wd_in[246]
  PIN rw0_wd_in[247]
    DIRECTION INPUT ;
    USE SIGNAL ;
    SHAPE ABUTMENT ;
    PORT
      LAYER M4 ;
      RECT 99.461 28.836 99.533 28.860 ;
    END
  END rw0_wd_in[247]
  PIN rw0_wd_in[248]
    DIRECTION INPUT ;
    USE SIGNAL ;
    SHAPE ABUTMENT ;
    PORT
      LAYER M4 ;
      RECT 99.461 29.076 99.533 29.100 ;
    END
  END rw0_wd_in[248]
  PIN rw0_wd_in[249]
    DIRECTION INPUT ;
    USE SIGNAL ;
    SHAPE ABUTMENT ;
    PORT
      LAYER M4 ;
      RECT 99.461 29.316 99.533 29.340 ;
    END
  END rw0_wd_in[249]
  PIN rw0_wd_in[250]
    DIRECTION INPUT ;
    USE SIGNAL ;
    SHAPE ABUTMENT ;
    PORT
      LAYER M4 ;
      RECT 99.461 29.556 99.533 29.580 ;
    END
  END rw0_wd_in[250]
  PIN rw0_wd_in[251]
    DIRECTION INPUT ;
    USE SIGNAL ;
    SHAPE ABUTMENT ;
    PORT
      LAYER M4 ;
      RECT 99.461 29.796 99.533 29.820 ;
    END
  END rw0_wd_in[251]
  PIN rw0_wd_in[252]
    DIRECTION INPUT ;
    USE SIGNAL ;
    SHAPE ABUTMENT ;
    PORT
      LAYER M4 ;
      RECT 99.461 30.036 99.533 30.060 ;
    END
  END rw0_wd_in[252]
  PIN rw0_wd_in[253]
    DIRECTION INPUT ;
    USE SIGNAL ;
    SHAPE ABUTMENT ;
    PORT
      LAYER M4 ;
      RECT 99.461 30.276 99.533 30.300 ;
    END
  END rw0_wd_in[253]
  PIN rw0_wd_in[254]
    DIRECTION INPUT ;
    USE SIGNAL ;
    SHAPE ABUTMENT ;
    PORT
      LAYER M4 ;
      RECT 99.461 30.516 99.533 30.540 ;
    END
  END rw0_wd_in[254]
  PIN rw0_wd_in[255]
    DIRECTION INPUT ;
    USE SIGNAL ;
    SHAPE ABUTMENT ;
    PORT
      LAYER M4 ;
      RECT 99.461 30.756 99.533 30.780 ;
    END
  END rw0_wd_in[255]
  PIN rw0_wd_in[256]
    DIRECTION OUTPUT ;
    USE SIGNAL ;
    SHAPE ABUTMENT ;
    PORT
      LAYER M3 ;
      RECT 0.207 0.000 0.225 0.054 ;
    END
  END rw0_wd_in[256]
  PIN rw0_wd_in[257]
    DIRECTION OUTPUT ;
    USE SIGNAL ;
    SHAPE ABUTMENT ;
    PORT
      LAYER M3 ;
      RECT 0.387 0.000 0.405 0.054 ;
    END
  END rw0_wd_in[257]
  PIN rw0_wd_in[258]
    DIRECTION OUTPUT ;
    USE SIGNAL ;
    SHAPE ABUTMENT ;
    PORT
      LAYER M3 ;
      RECT 0.567 0.000 0.585 0.054 ;
    END
  END rw0_wd_in[258]
  PIN rw0_wd_in[259]
    DIRECTION OUTPUT ;
    USE SIGNAL ;
    SHAPE ABUTMENT ;
    PORT
      LAYER M3 ;
      RECT 0.747 0.000 0.765 0.054 ;
    END
  END rw0_wd_in[259]
  PIN rw0_wd_in[260]
    DIRECTION OUTPUT ;
    USE SIGNAL ;
    SHAPE ABUTMENT ;
    PORT
      LAYER M3 ;
      RECT 0.927 0.000 0.945 0.054 ;
    END
  END rw0_wd_in[260]
  PIN rw0_wd_in[261]
    DIRECTION OUTPUT ;
    USE SIGNAL ;
    SHAPE ABUTMENT ;
    PORT
      LAYER M3 ;
      RECT 1.107 0.000 1.125 0.054 ;
    END
  END rw0_wd_in[261]
  PIN rw0_wd_in[262]
    DIRECTION OUTPUT ;
    USE SIGNAL ;
    SHAPE ABUTMENT ;
    PORT
      LAYER M3 ;
      RECT 1.287 0.000 1.305 0.054 ;
    END
  END rw0_wd_in[262]
  PIN rw0_wd_in[263]
    DIRECTION OUTPUT ;
    USE SIGNAL ;
    SHAPE ABUTMENT ;
    PORT
      LAYER M3 ;
      RECT 1.467 0.000 1.485 0.054 ;
    END
  END rw0_wd_in[263]
  PIN rw0_wd_in[264]
    DIRECTION OUTPUT ;
    USE SIGNAL ;
    SHAPE ABUTMENT ;
    PORT
      LAYER M3 ;
      RECT 1.647 0.000 1.665 0.054 ;
    END
  END rw0_wd_in[264]
  PIN rw0_wd_in[265]
    DIRECTION OUTPUT ;
    USE SIGNAL ;
    SHAPE ABUTMENT ;
    PORT
      LAYER M3 ;
      RECT 1.827 0.000 1.845 0.054 ;
    END
  END rw0_wd_in[265]
  PIN rw0_wd_in[266]
    DIRECTION OUTPUT ;
    USE SIGNAL ;
    SHAPE ABUTMENT ;
    PORT
      LAYER M3 ;
      RECT 2.007 0.000 2.025 0.054 ;
    END
  END rw0_wd_in[266]
  PIN rw0_wd_in[267]
    DIRECTION OUTPUT ;
    USE SIGNAL ;
    SHAPE ABUTMENT ;
    PORT
      LAYER M3 ;
      RECT 2.187 0.000 2.205 0.054 ;
    END
  END rw0_wd_in[267]
  PIN rw0_wd_in[268]
    DIRECTION OUTPUT ;
    USE SIGNAL ;
    SHAPE ABUTMENT ;
    PORT
      LAYER M3 ;
      RECT 2.367 0.000 2.385 0.054 ;
    END
  END rw0_wd_in[268]
  PIN rw0_wd_in[269]
    DIRECTION OUTPUT ;
    USE SIGNAL ;
    SHAPE ABUTMENT ;
    PORT
      LAYER M3 ;
      RECT 2.547 0.000 2.565 0.054 ;
    END
  END rw0_wd_in[269]
  PIN rw0_wd_in[270]
    DIRECTION OUTPUT ;
    USE SIGNAL ;
    SHAPE ABUTMENT ;
    PORT
      LAYER M3 ;
      RECT 2.727 0.000 2.745 0.054 ;
    END
  END rw0_wd_in[270]
  PIN rw0_wd_in[271]
    DIRECTION OUTPUT ;
    USE SIGNAL ;
    SHAPE ABUTMENT ;
    PORT
      LAYER M3 ;
      RECT 2.907 0.000 2.925 0.054 ;
    END
  END rw0_wd_in[271]
  PIN rw0_wd_in[272]
    DIRECTION OUTPUT ;
    USE SIGNAL ;
    SHAPE ABUTMENT ;
    PORT
      LAYER M3 ;
      RECT 3.087 0.000 3.105 0.054 ;
    END
  END rw0_wd_in[272]
  PIN rw0_wd_in[273]
    DIRECTION OUTPUT ;
    USE SIGNAL ;
    SHAPE ABUTMENT ;
    PORT
      LAYER M3 ;
      RECT 3.267 0.000 3.285 0.054 ;
    END
  END rw0_wd_in[273]
  PIN rw0_wd_in[274]
    DIRECTION OUTPUT ;
    USE SIGNAL ;
    SHAPE ABUTMENT ;
    PORT
      LAYER M3 ;
      RECT 3.447 0.000 3.465 0.054 ;
    END
  END rw0_wd_in[274]
  PIN rw0_wd_in[275]
    DIRECTION OUTPUT ;
    USE SIGNAL ;
    SHAPE ABUTMENT ;
    PORT
      LAYER M3 ;
      RECT 3.627 0.000 3.645 0.054 ;
    END
  END rw0_wd_in[275]
  PIN rw0_wd_in[276]
    DIRECTION OUTPUT ;
    USE SIGNAL ;
    SHAPE ABUTMENT ;
    PORT
      LAYER M3 ;
      RECT 3.807 0.000 3.825 0.054 ;
    END
  END rw0_wd_in[276]
  PIN rw0_wd_in[277]
    DIRECTION OUTPUT ;
    USE SIGNAL ;
    SHAPE ABUTMENT ;
    PORT
      LAYER M3 ;
      RECT 3.987 0.000 4.005 0.054 ;
    END
  END rw0_wd_in[277]
  PIN rw0_wd_in[278]
    DIRECTION OUTPUT ;
    USE SIGNAL ;
    SHAPE ABUTMENT ;
    PORT
      LAYER M3 ;
      RECT 4.167 0.000 4.185 0.054 ;
    END
  END rw0_wd_in[278]
  PIN rw0_wd_in[279]
    DIRECTION OUTPUT ;
    USE SIGNAL ;
    SHAPE ABUTMENT ;
    PORT
      LAYER M3 ;
      RECT 4.347 0.000 4.365 0.054 ;
    END
  END rw0_wd_in[279]
  PIN rw0_wd_in[280]
    DIRECTION OUTPUT ;
    USE SIGNAL ;
    SHAPE ABUTMENT ;
    PORT
      LAYER M3 ;
      RECT 4.527 0.000 4.545 0.054 ;
    END
  END rw0_wd_in[280]
  PIN rw0_wd_in[281]
    DIRECTION OUTPUT ;
    USE SIGNAL ;
    SHAPE ABUTMENT ;
    PORT
      LAYER M3 ;
      RECT 4.707 0.000 4.725 0.054 ;
    END
  END rw0_wd_in[281]
  PIN rw0_wd_in[282]
    DIRECTION OUTPUT ;
    USE SIGNAL ;
    SHAPE ABUTMENT ;
    PORT
      LAYER M3 ;
      RECT 4.887 0.000 4.905 0.054 ;
    END
  END rw0_wd_in[282]
  PIN rw0_wd_in[283]
    DIRECTION OUTPUT ;
    USE SIGNAL ;
    SHAPE ABUTMENT ;
    PORT
      LAYER M3 ;
      RECT 5.067 0.000 5.085 0.054 ;
    END
  END rw0_wd_in[283]
  PIN rw0_wd_in[284]
    DIRECTION OUTPUT ;
    USE SIGNAL ;
    SHAPE ABUTMENT ;
    PORT
      LAYER M3 ;
      RECT 5.247 0.000 5.265 0.054 ;
    END
  END rw0_wd_in[284]
  PIN rw0_wd_in[285]
    DIRECTION OUTPUT ;
    USE SIGNAL ;
    SHAPE ABUTMENT ;
    PORT
      LAYER M3 ;
      RECT 5.427 0.000 5.445 0.054 ;
    END
  END rw0_wd_in[285]
  PIN rw0_wd_in[286]
    DIRECTION OUTPUT ;
    USE SIGNAL ;
    SHAPE ABUTMENT ;
    PORT
      LAYER M3 ;
      RECT 5.607 0.000 5.625 0.054 ;
    END
  END rw0_wd_in[286]
  PIN rw0_wd_in[287]
    DIRECTION OUTPUT ;
    USE SIGNAL ;
    SHAPE ABUTMENT ;
    PORT
      LAYER M3 ;
      RECT 5.787 0.000 5.805 0.054 ;
    END
  END rw0_wd_in[287]
  PIN rw0_wd_in[288]
    DIRECTION OUTPUT ;
    USE SIGNAL ;
    SHAPE ABUTMENT ;
    PORT
      LAYER M3 ;
      RECT 5.967 0.000 5.985 0.054 ;
    END
  END rw0_wd_in[288]
  PIN rw0_wd_in[289]
    DIRECTION OUTPUT ;
    USE SIGNAL ;
    SHAPE ABUTMENT ;
    PORT
      LAYER M3 ;
      RECT 6.147 0.000 6.165 0.054 ;
    END
  END rw0_wd_in[289]
  PIN rw0_wd_in[290]
    DIRECTION OUTPUT ;
    USE SIGNAL ;
    SHAPE ABUTMENT ;
    PORT
      LAYER M3 ;
      RECT 6.327 0.000 6.345 0.054 ;
    END
  END rw0_wd_in[290]
  PIN rw0_wd_in[291]
    DIRECTION OUTPUT ;
    USE SIGNAL ;
    SHAPE ABUTMENT ;
    PORT
      LAYER M3 ;
      RECT 6.507 0.000 6.525 0.054 ;
    END
  END rw0_wd_in[291]
  PIN rw0_wd_in[292]
    DIRECTION OUTPUT ;
    USE SIGNAL ;
    SHAPE ABUTMENT ;
    PORT
      LAYER M3 ;
      RECT 6.687 0.000 6.705 0.054 ;
    END
  END rw0_wd_in[292]
  PIN rw0_wd_in[293]
    DIRECTION OUTPUT ;
    USE SIGNAL ;
    SHAPE ABUTMENT ;
    PORT
      LAYER M3 ;
      RECT 6.867 0.000 6.885 0.054 ;
    END
  END rw0_wd_in[293]
  PIN rw0_wd_in[294]
    DIRECTION OUTPUT ;
    USE SIGNAL ;
    SHAPE ABUTMENT ;
    PORT
      LAYER M3 ;
      RECT 7.047 0.000 7.065 0.054 ;
    END
  END rw0_wd_in[294]
  PIN rw0_wd_in[295]
    DIRECTION OUTPUT ;
    USE SIGNAL ;
    SHAPE ABUTMENT ;
    PORT
      LAYER M3 ;
      RECT 7.227 0.000 7.245 0.054 ;
    END
  END rw0_wd_in[295]
  PIN rw0_wd_in[296]
    DIRECTION OUTPUT ;
    USE SIGNAL ;
    SHAPE ABUTMENT ;
    PORT
      LAYER M3 ;
      RECT 7.407 0.000 7.425 0.054 ;
    END
  END rw0_wd_in[296]
  PIN rw0_wd_in[297]
    DIRECTION OUTPUT ;
    USE SIGNAL ;
    SHAPE ABUTMENT ;
    PORT
      LAYER M3 ;
      RECT 7.587 0.000 7.605 0.054 ;
    END
  END rw0_wd_in[297]
  PIN rw0_wd_in[298]
    DIRECTION OUTPUT ;
    USE SIGNAL ;
    SHAPE ABUTMENT ;
    PORT
      LAYER M3 ;
      RECT 7.767 0.000 7.785 0.054 ;
    END
  END rw0_wd_in[298]
  PIN rw0_wd_in[299]
    DIRECTION OUTPUT ;
    USE SIGNAL ;
    SHAPE ABUTMENT ;
    PORT
      LAYER M3 ;
      RECT 7.947 0.000 7.965 0.054 ;
    END
  END rw0_wd_in[299]
  PIN rw0_wd_in[300]
    DIRECTION OUTPUT ;
    USE SIGNAL ;
    SHAPE ABUTMENT ;
    PORT
      LAYER M3 ;
      RECT 8.127 0.000 8.145 0.054 ;
    END
  END rw0_wd_in[300]
  PIN rw0_wd_in[301]
    DIRECTION OUTPUT ;
    USE SIGNAL ;
    SHAPE ABUTMENT ;
    PORT
      LAYER M3 ;
      RECT 8.307 0.000 8.325 0.054 ;
    END
  END rw0_wd_in[301]
  PIN rw0_wd_in[302]
    DIRECTION OUTPUT ;
    USE SIGNAL ;
    SHAPE ABUTMENT ;
    PORT
      LAYER M3 ;
      RECT 8.487 0.000 8.505 0.054 ;
    END
  END rw0_wd_in[302]
  PIN rw0_wd_in[303]
    DIRECTION OUTPUT ;
    USE SIGNAL ;
    SHAPE ABUTMENT ;
    PORT
      LAYER M3 ;
      RECT 8.667 0.000 8.685 0.054 ;
    END
  END rw0_wd_in[303]
  PIN rw0_wd_in[304]
    DIRECTION OUTPUT ;
    USE SIGNAL ;
    SHAPE ABUTMENT ;
    PORT
      LAYER M3 ;
      RECT 8.847 0.000 8.865 0.054 ;
    END
  END rw0_wd_in[304]
  PIN rw0_wd_in[305]
    DIRECTION OUTPUT ;
    USE SIGNAL ;
    SHAPE ABUTMENT ;
    PORT
      LAYER M3 ;
      RECT 9.027 0.000 9.045 0.054 ;
    END
  END rw0_wd_in[305]
  PIN rw0_wd_in[306]
    DIRECTION OUTPUT ;
    USE SIGNAL ;
    SHAPE ABUTMENT ;
    PORT
      LAYER M3 ;
      RECT 9.207 0.000 9.225 0.054 ;
    END
  END rw0_wd_in[306]
  PIN rw0_wd_in[307]
    DIRECTION OUTPUT ;
    USE SIGNAL ;
    SHAPE ABUTMENT ;
    PORT
      LAYER M3 ;
      RECT 9.387 0.000 9.405 0.054 ;
    END
  END rw0_wd_in[307]
  PIN rw0_wd_in[308]
    DIRECTION OUTPUT ;
    USE SIGNAL ;
    SHAPE ABUTMENT ;
    PORT
      LAYER M3 ;
      RECT 9.567 0.000 9.585 0.054 ;
    END
  END rw0_wd_in[308]
  PIN rw0_wd_in[309]
    DIRECTION OUTPUT ;
    USE SIGNAL ;
    SHAPE ABUTMENT ;
    PORT
      LAYER M3 ;
      RECT 9.747 0.000 9.765 0.054 ;
    END
  END rw0_wd_in[309]
  PIN rw0_wd_in[310]
    DIRECTION OUTPUT ;
    USE SIGNAL ;
    SHAPE ABUTMENT ;
    PORT
      LAYER M3 ;
      RECT 9.927 0.000 9.945 0.054 ;
    END
  END rw0_wd_in[310]
  PIN rw0_wd_in[311]
    DIRECTION OUTPUT ;
    USE SIGNAL ;
    SHAPE ABUTMENT ;
    PORT
      LAYER M3 ;
      RECT 10.107 0.000 10.125 0.054 ;
    END
  END rw0_wd_in[311]
  PIN rw0_wd_in[312]
    DIRECTION OUTPUT ;
    USE SIGNAL ;
    SHAPE ABUTMENT ;
    PORT
      LAYER M3 ;
      RECT 10.287 0.000 10.305 0.054 ;
    END
  END rw0_wd_in[312]
  PIN rw0_wd_in[313]
    DIRECTION OUTPUT ;
    USE SIGNAL ;
    SHAPE ABUTMENT ;
    PORT
      LAYER M3 ;
      RECT 10.467 0.000 10.485 0.054 ;
    END
  END rw0_wd_in[313]
  PIN rw0_wd_in[314]
    DIRECTION OUTPUT ;
    USE SIGNAL ;
    SHAPE ABUTMENT ;
    PORT
      LAYER M3 ;
      RECT 10.647 0.000 10.665 0.054 ;
    END
  END rw0_wd_in[314]
  PIN rw0_wd_in[315]
    DIRECTION OUTPUT ;
    USE SIGNAL ;
    SHAPE ABUTMENT ;
    PORT
      LAYER M3 ;
      RECT 10.827 0.000 10.845 0.054 ;
    END
  END rw0_wd_in[315]
  PIN rw0_wd_in[316]
    DIRECTION OUTPUT ;
    USE SIGNAL ;
    SHAPE ABUTMENT ;
    PORT
      LAYER M3 ;
      RECT 11.007 0.000 11.025 0.054 ;
    END
  END rw0_wd_in[316]
  PIN rw0_wd_in[317]
    DIRECTION OUTPUT ;
    USE SIGNAL ;
    SHAPE ABUTMENT ;
    PORT
      LAYER M3 ;
      RECT 11.187 0.000 11.205 0.054 ;
    END
  END rw0_wd_in[317]
  PIN rw0_wd_in[318]
    DIRECTION OUTPUT ;
    USE SIGNAL ;
    SHAPE ABUTMENT ;
    PORT
      LAYER M3 ;
      RECT 11.367 0.000 11.385 0.054 ;
    END
  END rw0_wd_in[318]
  PIN rw0_wd_in[319]
    DIRECTION OUTPUT ;
    USE SIGNAL ;
    SHAPE ABUTMENT ;
    PORT
      LAYER M3 ;
      RECT 11.547 0.000 11.565 0.054 ;
    END
  END rw0_wd_in[319]
  PIN rw0_wd_in[320]
    DIRECTION OUTPUT ;
    USE SIGNAL ;
    SHAPE ABUTMENT ;
    PORT
      LAYER M3 ;
      RECT 11.727 0.000 11.745 0.054 ;
    END
  END rw0_wd_in[320]
  PIN rw0_wd_in[321]
    DIRECTION OUTPUT ;
    USE SIGNAL ;
    SHAPE ABUTMENT ;
    PORT
      LAYER M3 ;
      RECT 11.907 0.000 11.925 0.054 ;
    END
  END rw0_wd_in[321]
  PIN rw0_wd_in[322]
    DIRECTION OUTPUT ;
    USE SIGNAL ;
    SHAPE ABUTMENT ;
    PORT
      LAYER M3 ;
      RECT 12.087 0.000 12.105 0.054 ;
    END
  END rw0_wd_in[322]
  PIN rw0_wd_in[323]
    DIRECTION OUTPUT ;
    USE SIGNAL ;
    SHAPE ABUTMENT ;
    PORT
      LAYER M3 ;
      RECT 12.267 0.000 12.285 0.054 ;
    END
  END rw0_wd_in[323]
  PIN rw0_wd_in[324]
    DIRECTION OUTPUT ;
    USE SIGNAL ;
    SHAPE ABUTMENT ;
    PORT
      LAYER M3 ;
      RECT 12.447 0.000 12.465 0.054 ;
    END
  END rw0_wd_in[324]
  PIN rw0_wd_in[325]
    DIRECTION OUTPUT ;
    USE SIGNAL ;
    SHAPE ABUTMENT ;
    PORT
      LAYER M3 ;
      RECT 12.627 0.000 12.645 0.054 ;
    END
  END rw0_wd_in[325]
  PIN rw0_wd_in[326]
    DIRECTION OUTPUT ;
    USE SIGNAL ;
    SHAPE ABUTMENT ;
    PORT
      LAYER M3 ;
      RECT 12.807 0.000 12.825 0.054 ;
    END
  END rw0_wd_in[326]
  PIN rw0_wd_in[327]
    DIRECTION OUTPUT ;
    USE SIGNAL ;
    SHAPE ABUTMENT ;
    PORT
      LAYER M3 ;
      RECT 12.987 0.000 13.005 0.054 ;
    END
  END rw0_wd_in[327]
  PIN rw0_wd_in[328]
    DIRECTION OUTPUT ;
    USE SIGNAL ;
    SHAPE ABUTMENT ;
    PORT
      LAYER M3 ;
      RECT 13.167 0.000 13.185 0.054 ;
    END
  END rw0_wd_in[328]
  PIN rw0_wd_in[329]
    DIRECTION OUTPUT ;
    USE SIGNAL ;
    SHAPE ABUTMENT ;
    PORT
      LAYER M3 ;
      RECT 13.347 0.000 13.365 0.054 ;
    END
  END rw0_wd_in[329]
  PIN rw0_wd_in[330]
    DIRECTION OUTPUT ;
    USE SIGNAL ;
    SHAPE ABUTMENT ;
    PORT
      LAYER M3 ;
      RECT 13.527 0.000 13.545 0.054 ;
    END
  END rw0_wd_in[330]
  PIN rw0_wd_in[331]
    DIRECTION OUTPUT ;
    USE SIGNAL ;
    SHAPE ABUTMENT ;
    PORT
      LAYER M3 ;
      RECT 13.707 0.000 13.725 0.054 ;
    END
  END rw0_wd_in[331]
  PIN rw0_wd_in[332]
    DIRECTION OUTPUT ;
    USE SIGNAL ;
    SHAPE ABUTMENT ;
    PORT
      LAYER M3 ;
      RECT 13.887 0.000 13.905 0.054 ;
    END
  END rw0_wd_in[332]
  PIN rw0_wd_in[333]
    DIRECTION OUTPUT ;
    USE SIGNAL ;
    SHAPE ABUTMENT ;
    PORT
      LAYER M3 ;
      RECT 14.067 0.000 14.085 0.054 ;
    END
  END rw0_wd_in[333]
  PIN rw0_wd_in[334]
    DIRECTION OUTPUT ;
    USE SIGNAL ;
    SHAPE ABUTMENT ;
    PORT
      LAYER M3 ;
      RECT 14.247 0.000 14.265 0.054 ;
    END
  END rw0_wd_in[334]
  PIN rw0_wd_in[335]
    DIRECTION OUTPUT ;
    USE SIGNAL ;
    SHAPE ABUTMENT ;
    PORT
      LAYER M3 ;
      RECT 14.427 0.000 14.445 0.054 ;
    END
  END rw0_wd_in[335]
  PIN rw0_wd_in[336]
    DIRECTION OUTPUT ;
    USE SIGNAL ;
    SHAPE ABUTMENT ;
    PORT
      LAYER M3 ;
      RECT 14.607 0.000 14.625 0.054 ;
    END
  END rw0_wd_in[336]
  PIN rw0_wd_in[337]
    DIRECTION OUTPUT ;
    USE SIGNAL ;
    SHAPE ABUTMENT ;
    PORT
      LAYER M3 ;
      RECT 14.787 0.000 14.805 0.054 ;
    END
  END rw0_wd_in[337]
  PIN rw0_wd_in[338]
    DIRECTION OUTPUT ;
    USE SIGNAL ;
    SHAPE ABUTMENT ;
    PORT
      LAYER M3 ;
      RECT 14.967 0.000 14.985 0.054 ;
    END
  END rw0_wd_in[338]
  PIN rw0_wd_in[339]
    DIRECTION OUTPUT ;
    USE SIGNAL ;
    SHAPE ABUTMENT ;
    PORT
      LAYER M3 ;
      RECT 15.147 0.000 15.165 0.054 ;
    END
  END rw0_wd_in[339]
  PIN rw0_wd_in[340]
    DIRECTION OUTPUT ;
    USE SIGNAL ;
    SHAPE ABUTMENT ;
    PORT
      LAYER M3 ;
      RECT 15.327 0.000 15.345 0.054 ;
    END
  END rw0_wd_in[340]
  PIN rw0_wd_in[341]
    DIRECTION OUTPUT ;
    USE SIGNAL ;
    SHAPE ABUTMENT ;
    PORT
      LAYER M3 ;
      RECT 15.507 0.000 15.525 0.054 ;
    END
  END rw0_wd_in[341]
  PIN rw0_wd_in[342]
    DIRECTION OUTPUT ;
    USE SIGNAL ;
    SHAPE ABUTMENT ;
    PORT
      LAYER M3 ;
      RECT 15.687 0.000 15.705 0.054 ;
    END
  END rw0_wd_in[342]
  PIN rw0_wd_in[343]
    DIRECTION OUTPUT ;
    USE SIGNAL ;
    SHAPE ABUTMENT ;
    PORT
      LAYER M3 ;
      RECT 15.867 0.000 15.885 0.054 ;
    END
  END rw0_wd_in[343]
  PIN rw0_wd_in[344]
    DIRECTION OUTPUT ;
    USE SIGNAL ;
    SHAPE ABUTMENT ;
    PORT
      LAYER M3 ;
      RECT 16.047 0.000 16.065 0.054 ;
    END
  END rw0_wd_in[344]
  PIN rw0_wd_in[345]
    DIRECTION OUTPUT ;
    USE SIGNAL ;
    SHAPE ABUTMENT ;
    PORT
      LAYER M3 ;
      RECT 16.227 0.000 16.245 0.054 ;
    END
  END rw0_wd_in[345]
  PIN rw0_wd_in[346]
    DIRECTION OUTPUT ;
    USE SIGNAL ;
    SHAPE ABUTMENT ;
    PORT
      LAYER M3 ;
      RECT 16.407 0.000 16.425 0.054 ;
    END
  END rw0_wd_in[346]
  PIN rw0_wd_in[347]
    DIRECTION OUTPUT ;
    USE SIGNAL ;
    SHAPE ABUTMENT ;
    PORT
      LAYER M3 ;
      RECT 16.587 0.000 16.605 0.054 ;
    END
  END rw0_wd_in[347]
  PIN rw0_wd_in[348]
    DIRECTION OUTPUT ;
    USE SIGNAL ;
    SHAPE ABUTMENT ;
    PORT
      LAYER M3 ;
      RECT 16.767 0.000 16.785 0.054 ;
    END
  END rw0_wd_in[348]
  PIN rw0_wd_in[349]
    DIRECTION OUTPUT ;
    USE SIGNAL ;
    SHAPE ABUTMENT ;
    PORT
      LAYER M3 ;
      RECT 16.947 0.000 16.965 0.054 ;
    END
  END rw0_wd_in[349]
  PIN rw0_wd_in[350]
    DIRECTION OUTPUT ;
    USE SIGNAL ;
    SHAPE ABUTMENT ;
    PORT
      LAYER M3 ;
      RECT 17.127 0.000 17.145 0.054 ;
    END
  END rw0_wd_in[350]
  PIN rw0_wd_in[351]
    DIRECTION OUTPUT ;
    USE SIGNAL ;
    SHAPE ABUTMENT ;
    PORT
      LAYER M3 ;
      RECT 17.307 0.000 17.325 0.054 ;
    END
  END rw0_wd_in[351]
  PIN rw0_wd_in[352]
    DIRECTION OUTPUT ;
    USE SIGNAL ;
    SHAPE ABUTMENT ;
    PORT
      LAYER M3 ;
      RECT 17.487 0.000 17.505 0.054 ;
    END
  END rw0_wd_in[352]
  PIN rw0_wd_in[353]
    DIRECTION OUTPUT ;
    USE SIGNAL ;
    SHAPE ABUTMENT ;
    PORT
      LAYER M3 ;
      RECT 17.667 0.000 17.685 0.054 ;
    END
  END rw0_wd_in[353]
  PIN rw0_wd_in[354]
    DIRECTION OUTPUT ;
    USE SIGNAL ;
    SHAPE ABUTMENT ;
    PORT
      LAYER M3 ;
      RECT 17.847 0.000 17.865 0.054 ;
    END
  END rw0_wd_in[354]
  PIN rw0_wd_in[355]
    DIRECTION OUTPUT ;
    USE SIGNAL ;
    SHAPE ABUTMENT ;
    PORT
      LAYER M3 ;
      RECT 18.027 0.000 18.045 0.054 ;
    END
  END rw0_wd_in[355]
  PIN rw0_wd_in[356]
    DIRECTION OUTPUT ;
    USE SIGNAL ;
    SHAPE ABUTMENT ;
    PORT
      LAYER M3 ;
      RECT 18.207 0.000 18.225 0.054 ;
    END
  END rw0_wd_in[356]
  PIN rw0_wd_in[357]
    DIRECTION OUTPUT ;
    USE SIGNAL ;
    SHAPE ABUTMENT ;
    PORT
      LAYER M3 ;
      RECT 18.387 0.000 18.405 0.054 ;
    END
  END rw0_wd_in[357]
  PIN rw0_wd_in[358]
    DIRECTION OUTPUT ;
    USE SIGNAL ;
    SHAPE ABUTMENT ;
    PORT
      LAYER M3 ;
      RECT 18.567 0.000 18.585 0.054 ;
    END
  END rw0_wd_in[358]
  PIN rw0_wd_in[359]
    DIRECTION OUTPUT ;
    USE SIGNAL ;
    SHAPE ABUTMENT ;
    PORT
      LAYER M3 ;
      RECT 18.747 0.000 18.765 0.054 ;
    END
  END rw0_wd_in[359]
  PIN rw0_wd_in[360]
    DIRECTION OUTPUT ;
    USE SIGNAL ;
    SHAPE ABUTMENT ;
    PORT
      LAYER M3 ;
      RECT 18.927 0.000 18.945 0.054 ;
    END
  END rw0_wd_in[360]
  PIN rw0_wd_in[361]
    DIRECTION OUTPUT ;
    USE SIGNAL ;
    SHAPE ABUTMENT ;
    PORT
      LAYER M3 ;
      RECT 19.107 0.000 19.125 0.054 ;
    END
  END rw0_wd_in[361]
  PIN rw0_wd_in[362]
    DIRECTION OUTPUT ;
    USE SIGNAL ;
    SHAPE ABUTMENT ;
    PORT
      LAYER M3 ;
      RECT 19.287 0.000 19.305 0.054 ;
    END
  END rw0_wd_in[362]
  PIN rw0_wd_in[363]
    DIRECTION OUTPUT ;
    USE SIGNAL ;
    SHAPE ABUTMENT ;
    PORT
      LAYER M3 ;
      RECT 19.467 0.000 19.485 0.054 ;
    END
  END rw0_wd_in[363]
  PIN rw0_wd_in[364]
    DIRECTION OUTPUT ;
    USE SIGNAL ;
    SHAPE ABUTMENT ;
    PORT
      LAYER M3 ;
      RECT 19.647 0.000 19.665 0.054 ;
    END
  END rw0_wd_in[364]
  PIN rw0_wd_in[365]
    DIRECTION OUTPUT ;
    USE SIGNAL ;
    SHAPE ABUTMENT ;
    PORT
      LAYER M3 ;
      RECT 19.827 0.000 19.845 0.054 ;
    END
  END rw0_wd_in[365]
  PIN rw0_wd_in[366]
    DIRECTION OUTPUT ;
    USE SIGNAL ;
    SHAPE ABUTMENT ;
    PORT
      LAYER M3 ;
      RECT 20.007 0.000 20.025 0.054 ;
    END
  END rw0_wd_in[366]
  PIN rw0_wd_in[367]
    DIRECTION OUTPUT ;
    USE SIGNAL ;
    SHAPE ABUTMENT ;
    PORT
      LAYER M3 ;
      RECT 20.187 0.000 20.205 0.054 ;
    END
  END rw0_wd_in[367]
  PIN rw0_wd_in[368]
    DIRECTION OUTPUT ;
    USE SIGNAL ;
    SHAPE ABUTMENT ;
    PORT
      LAYER M3 ;
      RECT 20.367 0.000 20.385 0.054 ;
    END
  END rw0_wd_in[368]
  PIN rw0_wd_in[369]
    DIRECTION OUTPUT ;
    USE SIGNAL ;
    SHAPE ABUTMENT ;
    PORT
      LAYER M3 ;
      RECT 20.547 0.000 20.565 0.054 ;
    END
  END rw0_wd_in[369]
  PIN rw0_wd_in[370]
    DIRECTION OUTPUT ;
    USE SIGNAL ;
    SHAPE ABUTMENT ;
    PORT
      LAYER M3 ;
      RECT 20.727 0.000 20.745 0.054 ;
    END
  END rw0_wd_in[370]
  PIN rw0_wd_in[371]
    DIRECTION OUTPUT ;
    USE SIGNAL ;
    SHAPE ABUTMENT ;
    PORT
      LAYER M3 ;
      RECT 20.907 0.000 20.925 0.054 ;
    END
  END rw0_wd_in[371]
  PIN rw0_wd_in[372]
    DIRECTION OUTPUT ;
    USE SIGNAL ;
    SHAPE ABUTMENT ;
    PORT
      LAYER M3 ;
      RECT 21.087 0.000 21.105 0.054 ;
    END
  END rw0_wd_in[372]
  PIN rw0_wd_in[373]
    DIRECTION OUTPUT ;
    USE SIGNAL ;
    SHAPE ABUTMENT ;
    PORT
      LAYER M3 ;
      RECT 21.267 0.000 21.285 0.054 ;
    END
  END rw0_wd_in[373]
  PIN rw0_wd_in[374]
    DIRECTION OUTPUT ;
    USE SIGNAL ;
    SHAPE ABUTMENT ;
    PORT
      LAYER M3 ;
      RECT 21.447 0.000 21.465 0.054 ;
    END
  END rw0_wd_in[374]
  PIN rw0_wd_in[375]
    DIRECTION OUTPUT ;
    USE SIGNAL ;
    SHAPE ABUTMENT ;
    PORT
      LAYER M3 ;
      RECT 21.627 0.000 21.645 0.054 ;
    END
  END rw0_wd_in[375]
  PIN rw0_wd_in[376]
    DIRECTION OUTPUT ;
    USE SIGNAL ;
    SHAPE ABUTMENT ;
    PORT
      LAYER M3 ;
      RECT 21.807 0.000 21.825 0.054 ;
    END
  END rw0_wd_in[376]
  PIN rw0_wd_in[377]
    DIRECTION OUTPUT ;
    USE SIGNAL ;
    SHAPE ABUTMENT ;
    PORT
      LAYER M3 ;
      RECT 21.987 0.000 22.005 0.054 ;
    END
  END rw0_wd_in[377]
  PIN rw0_wd_in[378]
    DIRECTION OUTPUT ;
    USE SIGNAL ;
    SHAPE ABUTMENT ;
    PORT
      LAYER M3 ;
      RECT 22.167 0.000 22.185 0.054 ;
    END
  END rw0_wd_in[378]
  PIN rw0_wd_in[379]
    DIRECTION OUTPUT ;
    USE SIGNAL ;
    SHAPE ABUTMENT ;
    PORT
      LAYER M3 ;
      RECT 22.347 0.000 22.365 0.054 ;
    END
  END rw0_wd_in[379]
  PIN rw0_wd_in[380]
    DIRECTION OUTPUT ;
    USE SIGNAL ;
    SHAPE ABUTMENT ;
    PORT
      LAYER M3 ;
      RECT 22.527 0.000 22.545 0.054 ;
    END
  END rw0_wd_in[380]
  PIN rw0_wd_in[381]
    DIRECTION OUTPUT ;
    USE SIGNAL ;
    SHAPE ABUTMENT ;
    PORT
      LAYER M3 ;
      RECT 22.707 0.000 22.725 0.054 ;
    END
  END rw0_wd_in[381]
  PIN rw0_wd_in[382]
    DIRECTION OUTPUT ;
    USE SIGNAL ;
    SHAPE ABUTMENT ;
    PORT
      LAYER M3 ;
      RECT 22.887 0.000 22.905 0.054 ;
    END
  END rw0_wd_in[382]
  PIN rw0_wd_in[383]
    DIRECTION OUTPUT ;
    USE SIGNAL ;
    SHAPE ABUTMENT ;
    PORT
      LAYER M3 ;
      RECT 23.067 0.000 23.085 0.054 ;
    END
  END rw0_wd_in[383]
  PIN rw0_wd_in[384]
    DIRECTION OUTPUT ;
    USE SIGNAL ;
    SHAPE ABUTMENT ;
    PORT
      LAYER M3 ;
      RECT 23.247 0.000 23.265 0.054 ;
    END
  END rw0_wd_in[384]
  PIN rw0_wd_in[385]
    DIRECTION OUTPUT ;
    USE SIGNAL ;
    SHAPE ABUTMENT ;
    PORT
      LAYER M3 ;
      RECT 23.427 0.000 23.445 0.054 ;
    END
  END rw0_wd_in[385]
  PIN rw0_wd_in[386]
    DIRECTION OUTPUT ;
    USE SIGNAL ;
    SHAPE ABUTMENT ;
    PORT
      LAYER M3 ;
      RECT 23.607 0.000 23.625 0.054 ;
    END
  END rw0_wd_in[386]
  PIN rw0_wd_in[387]
    DIRECTION OUTPUT ;
    USE SIGNAL ;
    SHAPE ABUTMENT ;
    PORT
      LAYER M3 ;
      RECT 23.787 0.000 23.805 0.054 ;
    END
  END rw0_wd_in[387]
  PIN rw0_wd_in[388]
    DIRECTION OUTPUT ;
    USE SIGNAL ;
    SHAPE ABUTMENT ;
    PORT
      LAYER M3 ;
      RECT 23.967 0.000 23.985 0.054 ;
    END
  END rw0_wd_in[388]
  PIN rw0_wd_in[389]
    DIRECTION OUTPUT ;
    USE SIGNAL ;
    SHAPE ABUTMENT ;
    PORT
      LAYER M3 ;
      RECT 24.147 0.000 24.165 0.054 ;
    END
  END rw0_wd_in[389]
  PIN rw0_wd_in[390]
    DIRECTION OUTPUT ;
    USE SIGNAL ;
    SHAPE ABUTMENT ;
    PORT
      LAYER M3 ;
      RECT 24.327 0.000 24.345 0.054 ;
    END
  END rw0_wd_in[390]
  PIN rw0_wd_in[391]
    DIRECTION OUTPUT ;
    USE SIGNAL ;
    SHAPE ABUTMENT ;
    PORT
      LAYER M3 ;
      RECT 24.507 0.000 24.525 0.054 ;
    END
  END rw0_wd_in[391]
  PIN rw0_wd_in[392]
    DIRECTION OUTPUT ;
    USE SIGNAL ;
    SHAPE ABUTMENT ;
    PORT
      LAYER M3 ;
      RECT 24.687 0.000 24.705 0.054 ;
    END
  END rw0_wd_in[392]
  PIN rw0_wd_in[393]
    DIRECTION OUTPUT ;
    USE SIGNAL ;
    SHAPE ABUTMENT ;
    PORT
      LAYER M3 ;
      RECT 24.867 0.000 24.885 0.054 ;
    END
  END rw0_wd_in[393]
  PIN rw0_wd_in[394]
    DIRECTION OUTPUT ;
    USE SIGNAL ;
    SHAPE ABUTMENT ;
    PORT
      LAYER M3 ;
      RECT 25.047 0.000 25.065 0.054 ;
    END
  END rw0_wd_in[394]
  PIN rw0_wd_in[395]
    DIRECTION OUTPUT ;
    USE SIGNAL ;
    SHAPE ABUTMENT ;
    PORT
      LAYER M3 ;
      RECT 25.227 0.000 25.245 0.054 ;
    END
  END rw0_wd_in[395]
  PIN rw0_wd_in[396]
    DIRECTION OUTPUT ;
    USE SIGNAL ;
    SHAPE ABUTMENT ;
    PORT
      LAYER M3 ;
      RECT 25.407 0.000 25.425 0.054 ;
    END
  END rw0_wd_in[396]
  PIN rw0_wd_in[397]
    DIRECTION OUTPUT ;
    USE SIGNAL ;
    SHAPE ABUTMENT ;
    PORT
      LAYER M3 ;
      RECT 25.587 0.000 25.605 0.054 ;
    END
  END rw0_wd_in[397]
  PIN rw0_wd_in[398]
    DIRECTION OUTPUT ;
    USE SIGNAL ;
    SHAPE ABUTMENT ;
    PORT
      LAYER M3 ;
      RECT 25.767 0.000 25.785 0.054 ;
    END
  END rw0_wd_in[398]
  PIN rw0_wd_in[399]
    DIRECTION OUTPUT ;
    USE SIGNAL ;
    SHAPE ABUTMENT ;
    PORT
      LAYER M3 ;
      RECT 25.947 0.000 25.965 0.054 ;
    END
  END rw0_wd_in[399]
  PIN rw0_wd_in[400]
    DIRECTION OUTPUT ;
    USE SIGNAL ;
    SHAPE ABUTMENT ;
    PORT
      LAYER M3 ;
      RECT 26.127 0.000 26.145 0.054 ;
    END
  END rw0_wd_in[400]
  PIN rw0_wd_in[401]
    DIRECTION OUTPUT ;
    USE SIGNAL ;
    SHAPE ABUTMENT ;
    PORT
      LAYER M3 ;
      RECT 26.307 0.000 26.325 0.054 ;
    END
  END rw0_wd_in[401]
  PIN rw0_wd_in[402]
    DIRECTION OUTPUT ;
    USE SIGNAL ;
    SHAPE ABUTMENT ;
    PORT
      LAYER M3 ;
      RECT 26.487 0.000 26.505 0.054 ;
    END
  END rw0_wd_in[402]
  PIN rw0_wd_in[403]
    DIRECTION OUTPUT ;
    USE SIGNAL ;
    SHAPE ABUTMENT ;
    PORT
      LAYER M3 ;
      RECT 26.667 0.000 26.685 0.054 ;
    END
  END rw0_wd_in[403]
  PIN rw0_wd_in[404]
    DIRECTION OUTPUT ;
    USE SIGNAL ;
    SHAPE ABUTMENT ;
    PORT
      LAYER M3 ;
      RECT 26.847 0.000 26.865 0.054 ;
    END
  END rw0_wd_in[404]
  PIN rw0_wd_in[405]
    DIRECTION OUTPUT ;
    USE SIGNAL ;
    SHAPE ABUTMENT ;
    PORT
      LAYER M3 ;
      RECT 27.027 0.000 27.045 0.054 ;
    END
  END rw0_wd_in[405]
  PIN rw0_wd_in[406]
    DIRECTION OUTPUT ;
    USE SIGNAL ;
    SHAPE ABUTMENT ;
    PORT
      LAYER M3 ;
      RECT 27.207 0.000 27.225 0.054 ;
    END
  END rw0_wd_in[406]
  PIN rw0_wd_in[407]
    DIRECTION OUTPUT ;
    USE SIGNAL ;
    SHAPE ABUTMENT ;
    PORT
      LAYER M3 ;
      RECT 27.387 0.000 27.405 0.054 ;
    END
  END rw0_wd_in[407]
  PIN rw0_wd_in[408]
    DIRECTION OUTPUT ;
    USE SIGNAL ;
    SHAPE ABUTMENT ;
    PORT
      LAYER M3 ;
      RECT 27.567 0.000 27.585 0.054 ;
    END
  END rw0_wd_in[408]
  PIN rw0_wd_in[409]
    DIRECTION OUTPUT ;
    USE SIGNAL ;
    SHAPE ABUTMENT ;
    PORT
      LAYER M3 ;
      RECT 27.747 0.000 27.765 0.054 ;
    END
  END rw0_wd_in[409]
  PIN rw0_wd_in[410]
    DIRECTION OUTPUT ;
    USE SIGNAL ;
    SHAPE ABUTMENT ;
    PORT
      LAYER M3 ;
      RECT 27.927 0.000 27.945 0.054 ;
    END
  END rw0_wd_in[410]
  PIN rw0_wd_in[411]
    DIRECTION OUTPUT ;
    USE SIGNAL ;
    SHAPE ABUTMENT ;
    PORT
      LAYER M3 ;
      RECT 28.107 0.000 28.125 0.054 ;
    END
  END rw0_wd_in[411]
  PIN rw0_wd_in[412]
    DIRECTION OUTPUT ;
    USE SIGNAL ;
    SHAPE ABUTMENT ;
    PORT
      LAYER M3 ;
      RECT 28.287 0.000 28.305 0.054 ;
    END
  END rw0_wd_in[412]
  PIN rw0_wd_in[413]
    DIRECTION OUTPUT ;
    USE SIGNAL ;
    SHAPE ABUTMENT ;
    PORT
      LAYER M3 ;
      RECT 28.467 0.000 28.485 0.054 ;
    END
  END rw0_wd_in[413]
  PIN rw0_wd_in[414]
    DIRECTION OUTPUT ;
    USE SIGNAL ;
    SHAPE ABUTMENT ;
    PORT
      LAYER M3 ;
      RECT 28.647 0.000 28.665 0.054 ;
    END
  END rw0_wd_in[414]
  PIN rw0_wd_in[415]
    DIRECTION OUTPUT ;
    USE SIGNAL ;
    SHAPE ABUTMENT ;
    PORT
      LAYER M3 ;
      RECT 28.827 0.000 28.845 0.054 ;
    END
  END rw0_wd_in[415]
  PIN rw0_wd_in[416]
    DIRECTION OUTPUT ;
    USE SIGNAL ;
    SHAPE ABUTMENT ;
    PORT
      LAYER M3 ;
      RECT 29.007 0.000 29.025 0.054 ;
    END
  END rw0_wd_in[416]
  PIN rw0_wd_in[417]
    DIRECTION OUTPUT ;
    USE SIGNAL ;
    SHAPE ABUTMENT ;
    PORT
      LAYER M3 ;
      RECT 29.187 0.000 29.205 0.054 ;
    END
  END rw0_wd_in[417]
  PIN rw0_wd_in[418]
    DIRECTION OUTPUT ;
    USE SIGNAL ;
    SHAPE ABUTMENT ;
    PORT
      LAYER M3 ;
      RECT 29.367 0.000 29.385 0.054 ;
    END
  END rw0_wd_in[418]
  PIN rw0_wd_in[419]
    DIRECTION OUTPUT ;
    USE SIGNAL ;
    SHAPE ABUTMENT ;
    PORT
      LAYER M3 ;
      RECT 29.547 0.000 29.565 0.054 ;
    END
  END rw0_wd_in[419]
  PIN rw0_wd_in[420]
    DIRECTION OUTPUT ;
    USE SIGNAL ;
    SHAPE ABUTMENT ;
    PORT
      LAYER M3 ;
      RECT 29.727 0.000 29.745 0.054 ;
    END
  END rw0_wd_in[420]
  PIN rw0_wd_in[421]
    DIRECTION OUTPUT ;
    USE SIGNAL ;
    SHAPE ABUTMENT ;
    PORT
      LAYER M3 ;
      RECT 29.907 0.000 29.925 0.054 ;
    END
  END rw0_wd_in[421]
  PIN rw0_wd_in[422]
    DIRECTION OUTPUT ;
    USE SIGNAL ;
    SHAPE ABUTMENT ;
    PORT
      LAYER M3 ;
      RECT 30.087 0.000 30.105 0.054 ;
    END
  END rw0_wd_in[422]
  PIN rw0_wd_in[423]
    DIRECTION OUTPUT ;
    USE SIGNAL ;
    SHAPE ABUTMENT ;
    PORT
      LAYER M3 ;
      RECT 30.267 0.000 30.285 0.054 ;
    END
  END rw0_wd_in[423]
  PIN rw0_wd_in[424]
    DIRECTION OUTPUT ;
    USE SIGNAL ;
    SHAPE ABUTMENT ;
    PORT
      LAYER M3 ;
      RECT 30.447 0.000 30.465 0.054 ;
    END
  END rw0_wd_in[424]
  PIN rw0_wd_in[425]
    DIRECTION OUTPUT ;
    USE SIGNAL ;
    SHAPE ABUTMENT ;
    PORT
      LAYER M3 ;
      RECT 30.627 0.000 30.645 0.054 ;
    END
  END rw0_wd_in[425]
  PIN rw0_wd_in[426]
    DIRECTION OUTPUT ;
    USE SIGNAL ;
    SHAPE ABUTMENT ;
    PORT
      LAYER M3 ;
      RECT 30.807 0.000 30.825 0.054 ;
    END
  END rw0_wd_in[426]
  PIN rw0_wd_in[427]
    DIRECTION OUTPUT ;
    USE SIGNAL ;
    SHAPE ABUTMENT ;
    PORT
      LAYER M3 ;
      RECT 30.987 0.000 31.005 0.054 ;
    END
  END rw0_wd_in[427]
  PIN rw0_wd_in[428]
    DIRECTION OUTPUT ;
    USE SIGNAL ;
    SHAPE ABUTMENT ;
    PORT
      LAYER M3 ;
      RECT 31.167 0.000 31.185 0.054 ;
    END
  END rw0_wd_in[428]
  PIN rw0_wd_in[429]
    DIRECTION OUTPUT ;
    USE SIGNAL ;
    SHAPE ABUTMENT ;
    PORT
      LAYER M3 ;
      RECT 31.347 0.000 31.365 0.054 ;
    END
  END rw0_wd_in[429]
  PIN rw0_wd_in[430]
    DIRECTION OUTPUT ;
    USE SIGNAL ;
    SHAPE ABUTMENT ;
    PORT
      LAYER M3 ;
      RECT 31.527 0.000 31.545 0.054 ;
    END
  END rw0_wd_in[430]
  PIN rw0_wd_in[431]
    DIRECTION OUTPUT ;
    USE SIGNAL ;
    SHAPE ABUTMENT ;
    PORT
      LAYER M3 ;
      RECT 31.707 0.000 31.725 0.054 ;
    END
  END rw0_wd_in[431]
  PIN rw0_wd_in[432]
    DIRECTION OUTPUT ;
    USE SIGNAL ;
    SHAPE ABUTMENT ;
    PORT
      LAYER M3 ;
      RECT 31.887 0.000 31.905 0.054 ;
    END
  END rw0_wd_in[432]
  PIN rw0_wd_in[433]
    DIRECTION OUTPUT ;
    USE SIGNAL ;
    SHAPE ABUTMENT ;
    PORT
      LAYER M3 ;
      RECT 32.067 0.000 32.085 0.054 ;
    END
  END rw0_wd_in[433]
  PIN rw0_wd_in[434]
    DIRECTION OUTPUT ;
    USE SIGNAL ;
    SHAPE ABUTMENT ;
    PORT
      LAYER M3 ;
      RECT 32.247 0.000 32.265 0.054 ;
    END
  END rw0_wd_in[434]
  PIN rw0_wd_in[435]
    DIRECTION OUTPUT ;
    USE SIGNAL ;
    SHAPE ABUTMENT ;
    PORT
      LAYER M3 ;
      RECT 32.427 0.000 32.445 0.054 ;
    END
  END rw0_wd_in[435]
  PIN rw0_wd_in[436]
    DIRECTION OUTPUT ;
    USE SIGNAL ;
    SHAPE ABUTMENT ;
    PORT
      LAYER M3 ;
      RECT 32.607 0.000 32.625 0.054 ;
    END
  END rw0_wd_in[436]
  PIN rw0_wd_in[437]
    DIRECTION OUTPUT ;
    USE SIGNAL ;
    SHAPE ABUTMENT ;
    PORT
      LAYER M3 ;
      RECT 32.787 0.000 32.805 0.054 ;
    END
  END rw0_wd_in[437]
  PIN rw0_wd_in[438]
    DIRECTION OUTPUT ;
    USE SIGNAL ;
    SHAPE ABUTMENT ;
    PORT
      LAYER M3 ;
      RECT 32.967 0.000 32.985 0.054 ;
    END
  END rw0_wd_in[438]
  PIN rw0_wd_in[439]
    DIRECTION OUTPUT ;
    USE SIGNAL ;
    SHAPE ABUTMENT ;
    PORT
      LAYER M3 ;
      RECT 33.147 0.000 33.165 0.054 ;
    END
  END rw0_wd_in[439]
  PIN rw0_wd_in[440]
    DIRECTION OUTPUT ;
    USE SIGNAL ;
    SHAPE ABUTMENT ;
    PORT
      LAYER M3 ;
      RECT 33.327 0.000 33.345 0.054 ;
    END
  END rw0_wd_in[440]
  PIN rw0_wd_in[441]
    DIRECTION OUTPUT ;
    USE SIGNAL ;
    SHAPE ABUTMENT ;
    PORT
      LAYER M3 ;
      RECT 33.507 0.000 33.525 0.054 ;
    END
  END rw0_wd_in[441]
  PIN rw0_wd_in[442]
    DIRECTION OUTPUT ;
    USE SIGNAL ;
    SHAPE ABUTMENT ;
    PORT
      LAYER M3 ;
      RECT 33.687 0.000 33.705 0.054 ;
    END
  END rw0_wd_in[442]
  PIN rw0_wd_in[443]
    DIRECTION OUTPUT ;
    USE SIGNAL ;
    SHAPE ABUTMENT ;
    PORT
      LAYER M3 ;
      RECT 33.867 0.000 33.885 0.054 ;
    END
  END rw0_wd_in[443]
  PIN rw0_wd_in[444]
    DIRECTION OUTPUT ;
    USE SIGNAL ;
    SHAPE ABUTMENT ;
    PORT
      LAYER M3 ;
      RECT 34.047 0.000 34.065 0.054 ;
    END
  END rw0_wd_in[444]
  PIN rw0_wd_in[445]
    DIRECTION OUTPUT ;
    USE SIGNAL ;
    SHAPE ABUTMENT ;
    PORT
      LAYER M3 ;
      RECT 34.227 0.000 34.245 0.054 ;
    END
  END rw0_wd_in[445]
  PIN rw0_wd_in[446]
    DIRECTION OUTPUT ;
    USE SIGNAL ;
    SHAPE ABUTMENT ;
    PORT
      LAYER M3 ;
      RECT 34.407 0.000 34.425 0.054 ;
    END
  END rw0_wd_in[446]
  PIN rw0_wd_in[447]
    DIRECTION OUTPUT ;
    USE SIGNAL ;
    SHAPE ABUTMENT ;
    PORT
      LAYER M3 ;
      RECT 34.587 0.000 34.605 0.054 ;
    END
  END rw0_wd_in[447]
  PIN rw0_wd_in[448]
    DIRECTION OUTPUT ;
    USE SIGNAL ;
    SHAPE ABUTMENT ;
    PORT
      LAYER M3 ;
      RECT 34.767 0.000 34.785 0.054 ;
    END
  END rw0_wd_in[448]
  PIN rw0_wd_in[449]
    DIRECTION OUTPUT ;
    USE SIGNAL ;
    SHAPE ABUTMENT ;
    PORT
      LAYER M3 ;
      RECT 34.947 0.000 34.965 0.054 ;
    END
  END rw0_wd_in[449]
  PIN rw0_wd_in[450]
    DIRECTION OUTPUT ;
    USE SIGNAL ;
    SHAPE ABUTMENT ;
    PORT
      LAYER M3 ;
      RECT 35.127 0.000 35.145 0.054 ;
    END
  END rw0_wd_in[450]
  PIN rw0_wd_in[451]
    DIRECTION OUTPUT ;
    USE SIGNAL ;
    SHAPE ABUTMENT ;
    PORT
      LAYER M3 ;
      RECT 35.307 0.000 35.325 0.054 ;
    END
  END rw0_wd_in[451]
  PIN rw0_wd_in[452]
    DIRECTION OUTPUT ;
    USE SIGNAL ;
    SHAPE ABUTMENT ;
    PORT
      LAYER M3 ;
      RECT 35.487 0.000 35.505 0.054 ;
    END
  END rw0_wd_in[452]
  PIN rw0_wd_in[453]
    DIRECTION OUTPUT ;
    USE SIGNAL ;
    SHAPE ABUTMENT ;
    PORT
      LAYER M3 ;
      RECT 35.667 0.000 35.685 0.054 ;
    END
  END rw0_wd_in[453]
  PIN rw0_wd_in[454]
    DIRECTION OUTPUT ;
    USE SIGNAL ;
    SHAPE ABUTMENT ;
    PORT
      LAYER M3 ;
      RECT 35.847 0.000 35.865 0.054 ;
    END
  END rw0_wd_in[454]
  PIN rw0_wd_in[455]
    DIRECTION OUTPUT ;
    USE SIGNAL ;
    SHAPE ABUTMENT ;
    PORT
      LAYER M3 ;
      RECT 36.027 0.000 36.045 0.054 ;
    END
  END rw0_wd_in[455]
  PIN rw0_wd_in[456]
    DIRECTION OUTPUT ;
    USE SIGNAL ;
    SHAPE ABUTMENT ;
    PORT
      LAYER M3 ;
      RECT 36.207 0.000 36.225 0.054 ;
    END
  END rw0_wd_in[456]
  PIN rw0_wd_in[457]
    DIRECTION OUTPUT ;
    USE SIGNAL ;
    SHAPE ABUTMENT ;
    PORT
      LAYER M3 ;
      RECT 36.387 0.000 36.405 0.054 ;
    END
  END rw0_wd_in[457]
  PIN rw0_wd_in[458]
    DIRECTION OUTPUT ;
    USE SIGNAL ;
    SHAPE ABUTMENT ;
    PORT
      LAYER M3 ;
      RECT 36.567 0.000 36.585 0.054 ;
    END
  END rw0_wd_in[458]
  PIN rw0_wd_in[459]
    DIRECTION OUTPUT ;
    USE SIGNAL ;
    SHAPE ABUTMENT ;
    PORT
      LAYER M3 ;
      RECT 36.747 0.000 36.765 0.054 ;
    END
  END rw0_wd_in[459]
  PIN rw0_wd_in[460]
    DIRECTION OUTPUT ;
    USE SIGNAL ;
    SHAPE ABUTMENT ;
    PORT
      LAYER M3 ;
      RECT 36.927 0.000 36.945 0.054 ;
    END
  END rw0_wd_in[460]
  PIN rw0_wd_in[461]
    DIRECTION OUTPUT ;
    USE SIGNAL ;
    SHAPE ABUTMENT ;
    PORT
      LAYER M3 ;
      RECT 37.107 0.000 37.125 0.054 ;
    END
  END rw0_wd_in[461]
  PIN rw0_wd_in[462]
    DIRECTION OUTPUT ;
    USE SIGNAL ;
    SHAPE ABUTMENT ;
    PORT
      LAYER M3 ;
      RECT 37.287 0.000 37.305 0.054 ;
    END
  END rw0_wd_in[462]
  PIN rw0_wd_in[463]
    DIRECTION OUTPUT ;
    USE SIGNAL ;
    SHAPE ABUTMENT ;
    PORT
      LAYER M3 ;
      RECT 37.467 0.000 37.485 0.054 ;
    END
  END rw0_wd_in[463]
  PIN rw0_wd_in[464]
    DIRECTION OUTPUT ;
    USE SIGNAL ;
    SHAPE ABUTMENT ;
    PORT
      LAYER M3 ;
      RECT 37.647 0.000 37.665 0.054 ;
    END
  END rw0_wd_in[464]
  PIN rw0_wd_in[465]
    DIRECTION OUTPUT ;
    USE SIGNAL ;
    SHAPE ABUTMENT ;
    PORT
      LAYER M3 ;
      RECT 37.827 0.000 37.845 0.054 ;
    END
  END rw0_wd_in[465]
  PIN rw0_wd_in[466]
    DIRECTION OUTPUT ;
    USE SIGNAL ;
    SHAPE ABUTMENT ;
    PORT
      LAYER M3 ;
      RECT 38.007 0.000 38.025 0.054 ;
    END
  END rw0_wd_in[466]
  PIN rw0_wd_in[467]
    DIRECTION OUTPUT ;
    USE SIGNAL ;
    SHAPE ABUTMENT ;
    PORT
      LAYER M3 ;
      RECT 38.187 0.000 38.205 0.054 ;
    END
  END rw0_wd_in[467]
  PIN rw0_wd_in[468]
    DIRECTION OUTPUT ;
    USE SIGNAL ;
    SHAPE ABUTMENT ;
    PORT
      LAYER M3 ;
      RECT 38.367 0.000 38.385 0.054 ;
    END
  END rw0_wd_in[468]
  PIN rw0_wd_in[469]
    DIRECTION OUTPUT ;
    USE SIGNAL ;
    SHAPE ABUTMENT ;
    PORT
      LAYER M3 ;
      RECT 38.547 0.000 38.565 0.054 ;
    END
  END rw0_wd_in[469]
  PIN rw0_wd_in[470]
    DIRECTION OUTPUT ;
    USE SIGNAL ;
    SHAPE ABUTMENT ;
    PORT
      LAYER M3 ;
      RECT 38.727 0.000 38.745 0.054 ;
    END
  END rw0_wd_in[470]
  PIN rw0_wd_in[471]
    DIRECTION OUTPUT ;
    USE SIGNAL ;
    SHAPE ABUTMENT ;
    PORT
      LAYER M3 ;
      RECT 38.907 0.000 38.925 0.054 ;
    END
  END rw0_wd_in[471]
  PIN rw0_wd_in[472]
    DIRECTION OUTPUT ;
    USE SIGNAL ;
    SHAPE ABUTMENT ;
    PORT
      LAYER M3 ;
      RECT 39.087 0.000 39.105 0.054 ;
    END
  END rw0_wd_in[472]
  PIN rw0_wd_in[473]
    DIRECTION OUTPUT ;
    USE SIGNAL ;
    SHAPE ABUTMENT ;
    PORT
      LAYER M3 ;
      RECT 39.267 0.000 39.285 0.054 ;
    END
  END rw0_wd_in[473]
  PIN rw0_wd_in[474]
    DIRECTION OUTPUT ;
    USE SIGNAL ;
    SHAPE ABUTMENT ;
    PORT
      LAYER M3 ;
      RECT 39.447 0.000 39.465 0.054 ;
    END
  END rw0_wd_in[474]
  PIN rw0_wd_in[475]
    DIRECTION OUTPUT ;
    USE SIGNAL ;
    SHAPE ABUTMENT ;
    PORT
      LAYER M3 ;
      RECT 39.627 0.000 39.645 0.054 ;
    END
  END rw0_wd_in[475]
  PIN rw0_wd_in[476]
    DIRECTION OUTPUT ;
    USE SIGNAL ;
    SHAPE ABUTMENT ;
    PORT
      LAYER M3 ;
      RECT 39.807 0.000 39.825 0.054 ;
    END
  END rw0_wd_in[476]
  PIN rw0_wd_in[477]
    DIRECTION OUTPUT ;
    USE SIGNAL ;
    SHAPE ABUTMENT ;
    PORT
      LAYER M3 ;
      RECT 39.987 0.000 40.005 0.054 ;
    END
  END rw0_wd_in[477]
  PIN rw0_wd_in[478]
    DIRECTION OUTPUT ;
    USE SIGNAL ;
    SHAPE ABUTMENT ;
    PORT
      LAYER M3 ;
      RECT 40.167 0.000 40.185 0.054 ;
    END
  END rw0_wd_in[478]
  PIN rw0_wd_in[479]
    DIRECTION OUTPUT ;
    USE SIGNAL ;
    SHAPE ABUTMENT ;
    PORT
      LAYER M3 ;
      RECT 40.347 0.000 40.365 0.054 ;
    END
  END rw0_wd_in[479]
  PIN rw0_wd_in[480]
    DIRECTION OUTPUT ;
    USE SIGNAL ;
    SHAPE ABUTMENT ;
    PORT
      LAYER M3 ;
      RECT 40.527 0.000 40.545 0.054 ;
    END
  END rw0_wd_in[480]
  PIN rw0_wd_in[481]
    DIRECTION OUTPUT ;
    USE SIGNAL ;
    SHAPE ABUTMENT ;
    PORT
      LAYER M3 ;
      RECT 40.707 0.000 40.725 0.054 ;
    END
  END rw0_wd_in[481]
  PIN rw0_wd_in[482]
    DIRECTION OUTPUT ;
    USE SIGNAL ;
    SHAPE ABUTMENT ;
    PORT
      LAYER M3 ;
      RECT 40.887 0.000 40.905 0.054 ;
    END
  END rw0_wd_in[482]
  PIN rw0_wd_in[483]
    DIRECTION OUTPUT ;
    USE SIGNAL ;
    SHAPE ABUTMENT ;
    PORT
      LAYER M3 ;
      RECT 41.067 0.000 41.085 0.054 ;
    END
  END rw0_wd_in[483]
  PIN rw0_wd_in[484]
    DIRECTION OUTPUT ;
    USE SIGNAL ;
    SHAPE ABUTMENT ;
    PORT
      LAYER M3 ;
      RECT 41.247 0.000 41.265 0.054 ;
    END
  END rw0_wd_in[484]
  PIN rw0_wd_in[485]
    DIRECTION OUTPUT ;
    USE SIGNAL ;
    SHAPE ABUTMENT ;
    PORT
      LAYER M3 ;
      RECT 41.427 0.000 41.445 0.054 ;
    END
  END rw0_wd_in[485]
  PIN rw0_wd_in[486]
    DIRECTION OUTPUT ;
    USE SIGNAL ;
    SHAPE ABUTMENT ;
    PORT
      LAYER M3 ;
      RECT 41.607 0.000 41.625 0.054 ;
    END
  END rw0_wd_in[486]
  PIN rw0_wd_in[487]
    DIRECTION OUTPUT ;
    USE SIGNAL ;
    SHAPE ABUTMENT ;
    PORT
      LAYER M3 ;
      RECT 41.787 0.000 41.805 0.054 ;
    END
  END rw0_wd_in[487]
  PIN rw0_wd_in[488]
    DIRECTION OUTPUT ;
    USE SIGNAL ;
    SHAPE ABUTMENT ;
    PORT
      LAYER M3 ;
      RECT 41.967 0.000 41.985 0.054 ;
    END
  END rw0_wd_in[488]
  PIN rw0_wd_in[489]
    DIRECTION OUTPUT ;
    USE SIGNAL ;
    SHAPE ABUTMENT ;
    PORT
      LAYER M3 ;
      RECT 42.147 0.000 42.165 0.054 ;
    END
  END rw0_wd_in[489]
  PIN rw0_wd_in[490]
    DIRECTION OUTPUT ;
    USE SIGNAL ;
    SHAPE ABUTMENT ;
    PORT
      LAYER M3 ;
      RECT 42.327 0.000 42.345 0.054 ;
    END
  END rw0_wd_in[490]
  PIN rw0_wd_in[491]
    DIRECTION OUTPUT ;
    USE SIGNAL ;
    SHAPE ABUTMENT ;
    PORT
      LAYER M3 ;
      RECT 42.507 0.000 42.525 0.054 ;
    END
  END rw0_wd_in[491]
  PIN rw0_wd_in[492]
    DIRECTION OUTPUT ;
    USE SIGNAL ;
    SHAPE ABUTMENT ;
    PORT
      LAYER M3 ;
      RECT 42.687 0.000 42.705 0.054 ;
    END
  END rw0_wd_in[492]
  PIN rw0_wd_in[493]
    DIRECTION OUTPUT ;
    USE SIGNAL ;
    SHAPE ABUTMENT ;
    PORT
      LAYER M3 ;
      RECT 42.867 0.000 42.885 0.054 ;
    END
  END rw0_wd_in[493]
  PIN rw0_wd_in[494]
    DIRECTION OUTPUT ;
    USE SIGNAL ;
    SHAPE ABUTMENT ;
    PORT
      LAYER M3 ;
      RECT 43.047 0.000 43.065 0.054 ;
    END
  END rw0_wd_in[494]
  PIN rw0_wd_in[495]
    DIRECTION OUTPUT ;
    USE SIGNAL ;
    SHAPE ABUTMENT ;
    PORT
      LAYER M3 ;
      RECT 43.227 0.000 43.245 0.054 ;
    END
  END rw0_wd_in[495]
  PIN rw0_wd_in[496]
    DIRECTION OUTPUT ;
    USE SIGNAL ;
    SHAPE ABUTMENT ;
    PORT
      LAYER M3 ;
      RECT 43.407 0.000 43.425 0.054 ;
    END
  END rw0_wd_in[496]
  PIN rw0_wd_in[497]
    DIRECTION OUTPUT ;
    USE SIGNAL ;
    SHAPE ABUTMENT ;
    PORT
      LAYER M3 ;
      RECT 43.587 0.000 43.605 0.054 ;
    END
  END rw0_wd_in[497]
  PIN rw0_wd_in[498]
    DIRECTION OUTPUT ;
    USE SIGNAL ;
    SHAPE ABUTMENT ;
    PORT
      LAYER M3 ;
      RECT 43.767 0.000 43.785 0.054 ;
    END
  END rw0_wd_in[498]
  PIN rw0_wd_in[499]
    DIRECTION OUTPUT ;
    USE SIGNAL ;
    SHAPE ABUTMENT ;
    PORT
      LAYER M3 ;
      RECT 43.947 0.000 43.965 0.054 ;
    END
  END rw0_wd_in[499]
  PIN rw0_wd_in[500]
    DIRECTION OUTPUT ;
    USE SIGNAL ;
    SHAPE ABUTMENT ;
    PORT
      LAYER M3 ;
      RECT 44.127 0.000 44.145 0.054 ;
    END
  END rw0_wd_in[500]
  PIN rw0_wd_in[501]
    DIRECTION OUTPUT ;
    USE SIGNAL ;
    SHAPE ABUTMENT ;
    PORT
      LAYER M3 ;
      RECT 44.307 0.000 44.325 0.054 ;
    END
  END rw0_wd_in[501]
  PIN rw0_wd_in[502]
    DIRECTION OUTPUT ;
    USE SIGNAL ;
    SHAPE ABUTMENT ;
    PORT
      LAYER M3 ;
      RECT 44.487 0.000 44.505 0.054 ;
    END
  END rw0_wd_in[502]
  PIN rw0_wd_in[503]
    DIRECTION OUTPUT ;
    USE SIGNAL ;
    SHAPE ABUTMENT ;
    PORT
      LAYER M3 ;
      RECT 44.667 0.000 44.685 0.054 ;
    END
  END rw0_wd_in[503]
  PIN rw0_wd_in[504]
    DIRECTION OUTPUT ;
    USE SIGNAL ;
    SHAPE ABUTMENT ;
    PORT
      LAYER M3 ;
      RECT 44.847 0.000 44.865 0.054 ;
    END
  END rw0_wd_in[504]
  PIN rw0_wd_in[505]
    DIRECTION OUTPUT ;
    USE SIGNAL ;
    SHAPE ABUTMENT ;
    PORT
      LAYER M3 ;
      RECT 45.027 0.000 45.045 0.054 ;
    END
  END rw0_wd_in[505]
  PIN rw0_wd_in[506]
    DIRECTION OUTPUT ;
    USE SIGNAL ;
    SHAPE ABUTMENT ;
    PORT
      LAYER M3 ;
      RECT 45.207 0.000 45.225 0.054 ;
    END
  END rw0_wd_in[506]
  PIN rw0_wd_in[507]
    DIRECTION OUTPUT ;
    USE SIGNAL ;
    SHAPE ABUTMENT ;
    PORT
      LAYER M3 ;
      RECT 45.387 0.000 45.405 0.054 ;
    END
  END rw0_wd_in[507]
  PIN rw0_wd_in[508]
    DIRECTION OUTPUT ;
    USE SIGNAL ;
    SHAPE ABUTMENT ;
    PORT
      LAYER M3 ;
      RECT 45.567 0.000 45.585 0.054 ;
    END
  END rw0_wd_in[508]
  PIN rw0_wd_in[509]
    DIRECTION OUTPUT ;
    USE SIGNAL ;
    SHAPE ABUTMENT ;
    PORT
      LAYER M3 ;
      RECT 45.747 0.000 45.765 0.054 ;
    END
  END rw0_wd_in[509]
  PIN rw0_wd_in[510]
    DIRECTION OUTPUT ;
    USE SIGNAL ;
    SHAPE ABUTMENT ;
    PORT
      LAYER M3 ;
      RECT 45.927 0.000 45.945 0.054 ;
    END
  END rw0_wd_in[510]
  PIN rw0_wd_in[511]
    DIRECTION OUTPUT ;
    USE SIGNAL ;
    SHAPE ABUTMENT ;
    PORT
      LAYER M3 ;
      RECT 46.107 0.000 46.125 0.054 ;
    END
  END rw0_wd_in[511]
  PIN rw0_rd_out[0]
    DIRECTION OUTPUT ;
    USE SIGNAL ;
    SHAPE ABUTMENT ;
    PORT
      LAYER M3 ;
      RECT 46.287 0.000 46.305 0.054 ;
    END
  END rw0_rd_out[0]
  PIN rw0_rd_out[1]
    DIRECTION OUTPUT ;
    USE SIGNAL ;
    SHAPE ABUTMENT ;
    PORT
      LAYER M3 ;
      RECT 46.467 0.000 46.485 0.054 ;
    END
  END rw0_rd_out[1]
  PIN rw0_rd_out[2]
    DIRECTION OUTPUT ;
    USE SIGNAL ;
    SHAPE ABUTMENT ;
    PORT
      LAYER M3 ;
      RECT 46.647 0.000 46.665 0.054 ;
    END
  END rw0_rd_out[2]
  PIN rw0_rd_out[3]
    DIRECTION OUTPUT ;
    USE SIGNAL ;
    SHAPE ABUTMENT ;
    PORT
      LAYER M3 ;
      RECT 46.827 0.000 46.845 0.054 ;
    END
  END rw0_rd_out[3]
  PIN rw0_rd_out[4]
    DIRECTION OUTPUT ;
    USE SIGNAL ;
    SHAPE ABUTMENT ;
    PORT
      LAYER M3 ;
      RECT 47.007 0.000 47.025 0.054 ;
    END
  END rw0_rd_out[4]
  PIN rw0_rd_out[5]
    DIRECTION OUTPUT ;
    USE SIGNAL ;
    SHAPE ABUTMENT ;
    PORT
      LAYER M3 ;
      RECT 47.187 0.000 47.205 0.054 ;
    END
  END rw0_rd_out[5]
  PIN rw0_rd_out[6]
    DIRECTION OUTPUT ;
    USE SIGNAL ;
    SHAPE ABUTMENT ;
    PORT
      LAYER M3 ;
      RECT 47.367 0.000 47.385 0.054 ;
    END
  END rw0_rd_out[6]
  PIN rw0_rd_out[7]
    DIRECTION OUTPUT ;
    USE SIGNAL ;
    SHAPE ABUTMENT ;
    PORT
      LAYER M3 ;
      RECT 47.547 0.000 47.565 0.054 ;
    END
  END rw0_rd_out[7]
  PIN rw0_rd_out[8]
    DIRECTION OUTPUT ;
    USE SIGNAL ;
    SHAPE ABUTMENT ;
    PORT
      LAYER M3 ;
      RECT 47.727 0.000 47.745 0.054 ;
    END
  END rw0_rd_out[8]
  PIN rw0_rd_out[9]
    DIRECTION OUTPUT ;
    USE SIGNAL ;
    SHAPE ABUTMENT ;
    PORT
      LAYER M3 ;
      RECT 47.907 0.000 47.925 0.054 ;
    END
  END rw0_rd_out[9]
  PIN rw0_rd_out[10]
    DIRECTION OUTPUT ;
    USE SIGNAL ;
    SHAPE ABUTMENT ;
    PORT
      LAYER M3 ;
      RECT 48.087 0.000 48.105 0.054 ;
    END
  END rw0_rd_out[10]
  PIN rw0_rd_out[11]
    DIRECTION OUTPUT ;
    USE SIGNAL ;
    SHAPE ABUTMENT ;
    PORT
      LAYER M3 ;
      RECT 48.267 0.000 48.285 0.054 ;
    END
  END rw0_rd_out[11]
  PIN rw0_rd_out[12]
    DIRECTION OUTPUT ;
    USE SIGNAL ;
    SHAPE ABUTMENT ;
    PORT
      LAYER M3 ;
      RECT 48.447 0.000 48.465 0.054 ;
    END
  END rw0_rd_out[12]
  PIN rw0_rd_out[13]
    DIRECTION OUTPUT ;
    USE SIGNAL ;
    SHAPE ABUTMENT ;
    PORT
      LAYER M3 ;
      RECT 48.627 0.000 48.645 0.054 ;
    END
  END rw0_rd_out[13]
  PIN rw0_rd_out[14]
    DIRECTION OUTPUT ;
    USE SIGNAL ;
    SHAPE ABUTMENT ;
    PORT
      LAYER M3 ;
      RECT 48.807 0.000 48.825 0.054 ;
    END
  END rw0_rd_out[14]
  PIN rw0_rd_out[15]
    DIRECTION OUTPUT ;
    USE SIGNAL ;
    SHAPE ABUTMENT ;
    PORT
      LAYER M3 ;
      RECT 48.987 0.000 49.005 0.054 ;
    END
  END rw0_rd_out[15]
  PIN rw0_rd_out[16]
    DIRECTION OUTPUT ;
    USE SIGNAL ;
    SHAPE ABUTMENT ;
    PORT
      LAYER M3 ;
      RECT 49.167 0.000 49.185 0.054 ;
    END
  END rw0_rd_out[16]
  PIN rw0_rd_out[17]
    DIRECTION OUTPUT ;
    USE SIGNAL ;
    SHAPE ABUTMENT ;
    PORT
      LAYER M3 ;
      RECT 49.347 0.000 49.365 0.054 ;
    END
  END rw0_rd_out[17]
  PIN rw0_rd_out[18]
    DIRECTION OUTPUT ;
    USE SIGNAL ;
    SHAPE ABUTMENT ;
    PORT
      LAYER M3 ;
      RECT 49.527 0.000 49.545 0.054 ;
    END
  END rw0_rd_out[18]
  PIN rw0_rd_out[19]
    DIRECTION OUTPUT ;
    USE SIGNAL ;
    SHAPE ABUTMENT ;
    PORT
      LAYER M3 ;
      RECT 49.707 0.000 49.725 0.054 ;
    END
  END rw0_rd_out[19]
  PIN rw0_rd_out[20]
    DIRECTION OUTPUT ;
    USE SIGNAL ;
    SHAPE ABUTMENT ;
    PORT
      LAYER M3 ;
      RECT 49.887 0.000 49.905 0.054 ;
    END
  END rw0_rd_out[20]
  PIN rw0_rd_out[21]
    DIRECTION OUTPUT ;
    USE SIGNAL ;
    SHAPE ABUTMENT ;
    PORT
      LAYER M3 ;
      RECT 50.067 0.000 50.085 0.054 ;
    END
  END rw0_rd_out[21]
  PIN rw0_rd_out[22]
    DIRECTION OUTPUT ;
    USE SIGNAL ;
    SHAPE ABUTMENT ;
    PORT
      LAYER M3 ;
      RECT 50.247 0.000 50.265 0.054 ;
    END
  END rw0_rd_out[22]
  PIN rw0_rd_out[23]
    DIRECTION OUTPUT ;
    USE SIGNAL ;
    SHAPE ABUTMENT ;
    PORT
      LAYER M3 ;
      RECT 50.427 0.000 50.445 0.054 ;
    END
  END rw0_rd_out[23]
  PIN rw0_rd_out[24]
    DIRECTION OUTPUT ;
    USE SIGNAL ;
    SHAPE ABUTMENT ;
    PORT
      LAYER M3 ;
      RECT 50.607 0.000 50.625 0.054 ;
    END
  END rw0_rd_out[24]
  PIN rw0_rd_out[25]
    DIRECTION OUTPUT ;
    USE SIGNAL ;
    SHAPE ABUTMENT ;
    PORT
      LAYER M3 ;
      RECT 50.787 0.000 50.805 0.054 ;
    END
  END rw0_rd_out[25]
  PIN rw0_rd_out[26]
    DIRECTION OUTPUT ;
    USE SIGNAL ;
    SHAPE ABUTMENT ;
    PORT
      LAYER M3 ;
      RECT 50.967 0.000 50.985 0.054 ;
    END
  END rw0_rd_out[26]
  PIN rw0_rd_out[27]
    DIRECTION OUTPUT ;
    USE SIGNAL ;
    SHAPE ABUTMENT ;
    PORT
      LAYER M3 ;
      RECT 51.147 0.000 51.165 0.054 ;
    END
  END rw0_rd_out[27]
  PIN rw0_rd_out[28]
    DIRECTION OUTPUT ;
    USE SIGNAL ;
    SHAPE ABUTMENT ;
    PORT
      LAYER M3 ;
      RECT 51.327 0.000 51.345 0.054 ;
    END
  END rw0_rd_out[28]
  PIN rw0_rd_out[29]
    DIRECTION OUTPUT ;
    USE SIGNAL ;
    SHAPE ABUTMENT ;
    PORT
      LAYER M3 ;
      RECT 51.507 0.000 51.525 0.054 ;
    END
  END rw0_rd_out[29]
  PIN rw0_rd_out[30]
    DIRECTION OUTPUT ;
    USE SIGNAL ;
    SHAPE ABUTMENT ;
    PORT
      LAYER M3 ;
      RECT 51.687 0.000 51.705 0.054 ;
    END
  END rw0_rd_out[30]
  PIN rw0_rd_out[31]
    DIRECTION OUTPUT ;
    USE SIGNAL ;
    SHAPE ABUTMENT ;
    PORT
      LAYER M3 ;
      RECT 51.867 0.000 51.885 0.054 ;
    END
  END rw0_rd_out[31]
  PIN rw0_rd_out[32]
    DIRECTION OUTPUT ;
    USE SIGNAL ;
    SHAPE ABUTMENT ;
    PORT
      LAYER M3 ;
      RECT 52.047 0.000 52.065 0.054 ;
    END
  END rw0_rd_out[32]
  PIN rw0_rd_out[33]
    DIRECTION OUTPUT ;
    USE SIGNAL ;
    SHAPE ABUTMENT ;
    PORT
      LAYER M3 ;
      RECT 52.227 0.000 52.245 0.054 ;
    END
  END rw0_rd_out[33]
  PIN rw0_rd_out[34]
    DIRECTION OUTPUT ;
    USE SIGNAL ;
    SHAPE ABUTMENT ;
    PORT
      LAYER M3 ;
      RECT 52.407 0.000 52.425 0.054 ;
    END
  END rw0_rd_out[34]
  PIN rw0_rd_out[35]
    DIRECTION OUTPUT ;
    USE SIGNAL ;
    SHAPE ABUTMENT ;
    PORT
      LAYER M3 ;
      RECT 52.587 0.000 52.605 0.054 ;
    END
  END rw0_rd_out[35]
  PIN rw0_rd_out[36]
    DIRECTION OUTPUT ;
    USE SIGNAL ;
    SHAPE ABUTMENT ;
    PORT
      LAYER M3 ;
      RECT 52.767 0.000 52.785 0.054 ;
    END
  END rw0_rd_out[36]
  PIN rw0_rd_out[37]
    DIRECTION OUTPUT ;
    USE SIGNAL ;
    SHAPE ABUTMENT ;
    PORT
      LAYER M3 ;
      RECT 52.947 0.000 52.965 0.054 ;
    END
  END rw0_rd_out[37]
  PIN rw0_rd_out[38]
    DIRECTION OUTPUT ;
    USE SIGNAL ;
    SHAPE ABUTMENT ;
    PORT
      LAYER M3 ;
      RECT 53.127 0.000 53.145 0.054 ;
    END
  END rw0_rd_out[38]
  PIN rw0_rd_out[39]
    DIRECTION OUTPUT ;
    USE SIGNAL ;
    SHAPE ABUTMENT ;
    PORT
      LAYER M3 ;
      RECT 53.307 0.000 53.325 0.054 ;
    END
  END rw0_rd_out[39]
  PIN rw0_rd_out[40]
    DIRECTION OUTPUT ;
    USE SIGNAL ;
    SHAPE ABUTMENT ;
    PORT
      LAYER M3 ;
      RECT 53.487 0.000 53.505 0.054 ;
    END
  END rw0_rd_out[40]
  PIN rw0_rd_out[41]
    DIRECTION OUTPUT ;
    USE SIGNAL ;
    SHAPE ABUTMENT ;
    PORT
      LAYER M3 ;
      RECT 53.667 0.000 53.685 0.054 ;
    END
  END rw0_rd_out[41]
  PIN rw0_rd_out[42]
    DIRECTION OUTPUT ;
    USE SIGNAL ;
    SHAPE ABUTMENT ;
    PORT
      LAYER M3 ;
      RECT 53.847 0.000 53.865 0.054 ;
    END
  END rw0_rd_out[42]
  PIN rw0_rd_out[43]
    DIRECTION OUTPUT ;
    USE SIGNAL ;
    SHAPE ABUTMENT ;
    PORT
      LAYER M3 ;
      RECT 54.027 0.000 54.045 0.054 ;
    END
  END rw0_rd_out[43]
  PIN rw0_rd_out[44]
    DIRECTION OUTPUT ;
    USE SIGNAL ;
    SHAPE ABUTMENT ;
    PORT
      LAYER M3 ;
      RECT 54.207 0.000 54.225 0.054 ;
    END
  END rw0_rd_out[44]
  PIN rw0_rd_out[45]
    DIRECTION OUTPUT ;
    USE SIGNAL ;
    SHAPE ABUTMENT ;
    PORT
      LAYER M3 ;
      RECT 54.387 0.000 54.405 0.054 ;
    END
  END rw0_rd_out[45]
  PIN rw0_rd_out[46]
    DIRECTION OUTPUT ;
    USE SIGNAL ;
    SHAPE ABUTMENT ;
    PORT
      LAYER M3 ;
      RECT 54.567 0.000 54.585 0.054 ;
    END
  END rw0_rd_out[46]
  PIN rw0_rd_out[47]
    DIRECTION OUTPUT ;
    USE SIGNAL ;
    SHAPE ABUTMENT ;
    PORT
      LAYER M3 ;
      RECT 54.747 0.000 54.765 0.054 ;
    END
  END rw0_rd_out[47]
  PIN rw0_rd_out[48]
    DIRECTION OUTPUT ;
    USE SIGNAL ;
    SHAPE ABUTMENT ;
    PORT
      LAYER M3 ;
      RECT 54.927 0.000 54.945 0.054 ;
    END
  END rw0_rd_out[48]
  PIN rw0_rd_out[49]
    DIRECTION OUTPUT ;
    USE SIGNAL ;
    SHAPE ABUTMENT ;
    PORT
      LAYER M3 ;
      RECT 55.107 0.000 55.125 0.054 ;
    END
  END rw0_rd_out[49]
  PIN rw0_rd_out[50]
    DIRECTION OUTPUT ;
    USE SIGNAL ;
    SHAPE ABUTMENT ;
    PORT
      LAYER M3 ;
      RECT 55.287 0.000 55.305 0.054 ;
    END
  END rw0_rd_out[50]
  PIN rw0_rd_out[51]
    DIRECTION OUTPUT ;
    USE SIGNAL ;
    SHAPE ABUTMENT ;
    PORT
      LAYER M3 ;
      RECT 55.467 0.000 55.485 0.054 ;
    END
  END rw0_rd_out[51]
  PIN rw0_rd_out[52]
    DIRECTION OUTPUT ;
    USE SIGNAL ;
    SHAPE ABUTMENT ;
    PORT
      LAYER M3 ;
      RECT 55.647 0.000 55.665 0.054 ;
    END
  END rw0_rd_out[52]
  PIN rw0_rd_out[53]
    DIRECTION OUTPUT ;
    USE SIGNAL ;
    SHAPE ABUTMENT ;
    PORT
      LAYER M3 ;
      RECT 55.827 0.000 55.845 0.054 ;
    END
  END rw0_rd_out[53]
  PIN rw0_rd_out[54]
    DIRECTION OUTPUT ;
    USE SIGNAL ;
    SHAPE ABUTMENT ;
    PORT
      LAYER M3 ;
      RECT 56.007 0.000 56.025 0.054 ;
    END
  END rw0_rd_out[54]
  PIN rw0_rd_out[55]
    DIRECTION OUTPUT ;
    USE SIGNAL ;
    SHAPE ABUTMENT ;
    PORT
      LAYER M3 ;
      RECT 56.187 0.000 56.205 0.054 ;
    END
  END rw0_rd_out[55]
  PIN rw0_rd_out[56]
    DIRECTION OUTPUT ;
    USE SIGNAL ;
    SHAPE ABUTMENT ;
    PORT
      LAYER M3 ;
      RECT 56.367 0.000 56.385 0.054 ;
    END
  END rw0_rd_out[56]
  PIN rw0_rd_out[57]
    DIRECTION OUTPUT ;
    USE SIGNAL ;
    SHAPE ABUTMENT ;
    PORT
      LAYER M3 ;
      RECT 56.547 0.000 56.565 0.054 ;
    END
  END rw0_rd_out[57]
  PIN rw0_rd_out[58]
    DIRECTION OUTPUT ;
    USE SIGNAL ;
    SHAPE ABUTMENT ;
    PORT
      LAYER M3 ;
      RECT 56.727 0.000 56.745 0.054 ;
    END
  END rw0_rd_out[58]
  PIN rw0_rd_out[59]
    DIRECTION OUTPUT ;
    USE SIGNAL ;
    SHAPE ABUTMENT ;
    PORT
      LAYER M3 ;
      RECT 56.907 0.000 56.925 0.054 ;
    END
  END rw0_rd_out[59]
  PIN rw0_rd_out[60]
    DIRECTION OUTPUT ;
    USE SIGNAL ;
    SHAPE ABUTMENT ;
    PORT
      LAYER M3 ;
      RECT 57.087 0.000 57.105 0.054 ;
    END
  END rw0_rd_out[60]
  PIN rw0_rd_out[61]
    DIRECTION OUTPUT ;
    USE SIGNAL ;
    SHAPE ABUTMENT ;
    PORT
      LAYER M3 ;
      RECT 57.267 0.000 57.285 0.054 ;
    END
  END rw0_rd_out[61]
  PIN rw0_rd_out[62]
    DIRECTION OUTPUT ;
    USE SIGNAL ;
    SHAPE ABUTMENT ;
    PORT
      LAYER M3 ;
      RECT 57.447 0.000 57.465 0.054 ;
    END
  END rw0_rd_out[62]
  PIN rw0_rd_out[63]
    DIRECTION OUTPUT ;
    USE SIGNAL ;
    SHAPE ABUTMENT ;
    PORT
      LAYER M3 ;
      RECT 57.627 0.000 57.645 0.054 ;
    END
  END rw0_rd_out[63]
  PIN rw0_rd_out[64]
    DIRECTION OUTPUT ;
    USE SIGNAL ;
    SHAPE ABUTMENT ;
    PORT
      LAYER M3 ;
      RECT 57.807 0.000 57.825 0.054 ;
    END
  END rw0_rd_out[64]
  PIN rw0_rd_out[65]
    DIRECTION OUTPUT ;
    USE SIGNAL ;
    SHAPE ABUTMENT ;
    PORT
      LAYER M3 ;
      RECT 57.987 0.000 58.005 0.054 ;
    END
  END rw0_rd_out[65]
  PIN rw0_rd_out[66]
    DIRECTION OUTPUT ;
    USE SIGNAL ;
    SHAPE ABUTMENT ;
    PORT
      LAYER M3 ;
      RECT 58.167 0.000 58.185 0.054 ;
    END
  END rw0_rd_out[66]
  PIN rw0_rd_out[67]
    DIRECTION OUTPUT ;
    USE SIGNAL ;
    SHAPE ABUTMENT ;
    PORT
      LAYER M3 ;
      RECT 58.347 0.000 58.365 0.054 ;
    END
  END rw0_rd_out[67]
  PIN rw0_rd_out[68]
    DIRECTION OUTPUT ;
    USE SIGNAL ;
    SHAPE ABUTMENT ;
    PORT
      LAYER M3 ;
      RECT 58.527 0.000 58.545 0.054 ;
    END
  END rw0_rd_out[68]
  PIN rw0_rd_out[69]
    DIRECTION OUTPUT ;
    USE SIGNAL ;
    SHAPE ABUTMENT ;
    PORT
      LAYER M3 ;
      RECT 58.707 0.000 58.725 0.054 ;
    END
  END rw0_rd_out[69]
  PIN rw0_rd_out[70]
    DIRECTION OUTPUT ;
    USE SIGNAL ;
    SHAPE ABUTMENT ;
    PORT
      LAYER M3 ;
      RECT 58.887 0.000 58.905 0.054 ;
    END
  END rw0_rd_out[70]
  PIN rw0_rd_out[71]
    DIRECTION OUTPUT ;
    USE SIGNAL ;
    SHAPE ABUTMENT ;
    PORT
      LAYER M3 ;
      RECT 59.067 0.000 59.085 0.054 ;
    END
  END rw0_rd_out[71]
  PIN rw0_rd_out[72]
    DIRECTION OUTPUT ;
    USE SIGNAL ;
    SHAPE ABUTMENT ;
    PORT
      LAYER M3 ;
      RECT 59.247 0.000 59.265 0.054 ;
    END
  END rw0_rd_out[72]
  PIN rw0_rd_out[73]
    DIRECTION OUTPUT ;
    USE SIGNAL ;
    SHAPE ABUTMENT ;
    PORT
      LAYER M3 ;
      RECT 59.427 0.000 59.445 0.054 ;
    END
  END rw0_rd_out[73]
  PIN rw0_rd_out[74]
    DIRECTION OUTPUT ;
    USE SIGNAL ;
    SHAPE ABUTMENT ;
    PORT
      LAYER M3 ;
      RECT 59.607 0.000 59.625 0.054 ;
    END
  END rw0_rd_out[74]
  PIN rw0_rd_out[75]
    DIRECTION OUTPUT ;
    USE SIGNAL ;
    SHAPE ABUTMENT ;
    PORT
      LAYER M3 ;
      RECT 59.787 0.000 59.805 0.054 ;
    END
  END rw0_rd_out[75]
  PIN rw0_rd_out[76]
    DIRECTION OUTPUT ;
    USE SIGNAL ;
    SHAPE ABUTMENT ;
    PORT
      LAYER M3 ;
      RECT 59.967 0.000 59.985 0.054 ;
    END
  END rw0_rd_out[76]
  PIN rw0_rd_out[77]
    DIRECTION OUTPUT ;
    USE SIGNAL ;
    SHAPE ABUTMENT ;
    PORT
      LAYER M3 ;
      RECT 60.147 0.000 60.165 0.054 ;
    END
  END rw0_rd_out[77]
  PIN rw0_rd_out[78]
    DIRECTION OUTPUT ;
    USE SIGNAL ;
    SHAPE ABUTMENT ;
    PORT
      LAYER M3 ;
      RECT 60.327 0.000 60.345 0.054 ;
    END
  END rw0_rd_out[78]
  PIN rw0_rd_out[79]
    DIRECTION OUTPUT ;
    USE SIGNAL ;
    SHAPE ABUTMENT ;
    PORT
      LAYER M3 ;
      RECT 60.507 0.000 60.525 0.054 ;
    END
  END rw0_rd_out[79]
  PIN rw0_rd_out[80]
    DIRECTION OUTPUT ;
    USE SIGNAL ;
    SHAPE ABUTMENT ;
    PORT
      LAYER M3 ;
      RECT 60.687 0.000 60.705 0.054 ;
    END
  END rw0_rd_out[80]
  PIN rw0_rd_out[81]
    DIRECTION OUTPUT ;
    USE SIGNAL ;
    SHAPE ABUTMENT ;
    PORT
      LAYER M3 ;
      RECT 60.867 0.000 60.885 0.054 ;
    END
  END rw0_rd_out[81]
  PIN rw0_rd_out[82]
    DIRECTION OUTPUT ;
    USE SIGNAL ;
    SHAPE ABUTMENT ;
    PORT
      LAYER M3 ;
      RECT 61.047 0.000 61.065 0.054 ;
    END
  END rw0_rd_out[82]
  PIN rw0_rd_out[83]
    DIRECTION OUTPUT ;
    USE SIGNAL ;
    SHAPE ABUTMENT ;
    PORT
      LAYER M3 ;
      RECT 61.227 0.000 61.245 0.054 ;
    END
  END rw0_rd_out[83]
  PIN rw0_rd_out[84]
    DIRECTION OUTPUT ;
    USE SIGNAL ;
    SHAPE ABUTMENT ;
    PORT
      LAYER M3 ;
      RECT 61.407 0.000 61.425 0.054 ;
    END
  END rw0_rd_out[84]
  PIN rw0_rd_out[85]
    DIRECTION OUTPUT ;
    USE SIGNAL ;
    SHAPE ABUTMENT ;
    PORT
      LAYER M3 ;
      RECT 61.587 0.000 61.605 0.054 ;
    END
  END rw0_rd_out[85]
  PIN rw0_rd_out[86]
    DIRECTION OUTPUT ;
    USE SIGNAL ;
    SHAPE ABUTMENT ;
    PORT
      LAYER M3 ;
      RECT 61.767 0.000 61.785 0.054 ;
    END
  END rw0_rd_out[86]
  PIN rw0_rd_out[87]
    DIRECTION OUTPUT ;
    USE SIGNAL ;
    SHAPE ABUTMENT ;
    PORT
      LAYER M3 ;
      RECT 61.947 0.000 61.965 0.054 ;
    END
  END rw0_rd_out[87]
  PIN rw0_rd_out[88]
    DIRECTION OUTPUT ;
    USE SIGNAL ;
    SHAPE ABUTMENT ;
    PORT
      LAYER M3 ;
      RECT 62.127 0.000 62.145 0.054 ;
    END
  END rw0_rd_out[88]
  PIN rw0_rd_out[89]
    DIRECTION OUTPUT ;
    USE SIGNAL ;
    SHAPE ABUTMENT ;
    PORT
      LAYER M3 ;
      RECT 62.307 0.000 62.325 0.054 ;
    END
  END rw0_rd_out[89]
  PIN rw0_rd_out[90]
    DIRECTION OUTPUT ;
    USE SIGNAL ;
    SHAPE ABUTMENT ;
    PORT
      LAYER M3 ;
      RECT 62.487 0.000 62.505 0.054 ;
    END
  END rw0_rd_out[90]
  PIN rw0_rd_out[91]
    DIRECTION OUTPUT ;
    USE SIGNAL ;
    SHAPE ABUTMENT ;
    PORT
      LAYER M3 ;
      RECT 62.667 0.000 62.685 0.054 ;
    END
  END rw0_rd_out[91]
  PIN rw0_rd_out[92]
    DIRECTION OUTPUT ;
    USE SIGNAL ;
    SHAPE ABUTMENT ;
    PORT
      LAYER M3 ;
      RECT 62.847 0.000 62.865 0.054 ;
    END
  END rw0_rd_out[92]
  PIN rw0_rd_out[93]
    DIRECTION OUTPUT ;
    USE SIGNAL ;
    SHAPE ABUTMENT ;
    PORT
      LAYER M3 ;
      RECT 63.027 0.000 63.045 0.054 ;
    END
  END rw0_rd_out[93]
  PIN rw0_rd_out[94]
    DIRECTION OUTPUT ;
    USE SIGNAL ;
    SHAPE ABUTMENT ;
    PORT
      LAYER M3 ;
      RECT 63.207 0.000 63.225 0.054 ;
    END
  END rw0_rd_out[94]
  PIN rw0_rd_out[95]
    DIRECTION OUTPUT ;
    USE SIGNAL ;
    SHAPE ABUTMENT ;
    PORT
      LAYER M3 ;
      RECT 63.387 0.000 63.405 0.054 ;
    END
  END rw0_rd_out[95]
  PIN rw0_rd_out[96]
    DIRECTION OUTPUT ;
    USE SIGNAL ;
    SHAPE ABUTMENT ;
    PORT
      LAYER M3 ;
      RECT 63.567 0.000 63.585 0.054 ;
    END
  END rw0_rd_out[96]
  PIN rw0_rd_out[97]
    DIRECTION OUTPUT ;
    USE SIGNAL ;
    SHAPE ABUTMENT ;
    PORT
      LAYER M3 ;
      RECT 63.747 0.000 63.765 0.054 ;
    END
  END rw0_rd_out[97]
  PIN rw0_rd_out[98]
    DIRECTION OUTPUT ;
    USE SIGNAL ;
    SHAPE ABUTMENT ;
    PORT
      LAYER M3 ;
      RECT 63.927 0.000 63.945 0.054 ;
    END
  END rw0_rd_out[98]
  PIN rw0_rd_out[99]
    DIRECTION OUTPUT ;
    USE SIGNAL ;
    SHAPE ABUTMENT ;
    PORT
      LAYER M3 ;
      RECT 64.107 0.000 64.125 0.054 ;
    END
  END rw0_rd_out[99]
  PIN rw0_rd_out[100]
    DIRECTION OUTPUT ;
    USE SIGNAL ;
    SHAPE ABUTMENT ;
    PORT
      LAYER M3 ;
      RECT 64.287 0.000 64.305 0.054 ;
    END
  END rw0_rd_out[100]
  PIN rw0_rd_out[101]
    DIRECTION OUTPUT ;
    USE SIGNAL ;
    SHAPE ABUTMENT ;
    PORT
      LAYER M3 ;
      RECT 64.467 0.000 64.485 0.054 ;
    END
  END rw0_rd_out[101]
  PIN rw0_rd_out[102]
    DIRECTION OUTPUT ;
    USE SIGNAL ;
    SHAPE ABUTMENT ;
    PORT
      LAYER M3 ;
      RECT 64.647 0.000 64.665 0.054 ;
    END
  END rw0_rd_out[102]
  PIN rw0_rd_out[103]
    DIRECTION OUTPUT ;
    USE SIGNAL ;
    SHAPE ABUTMENT ;
    PORT
      LAYER M3 ;
      RECT 64.827 0.000 64.845 0.054 ;
    END
  END rw0_rd_out[103]
  PIN rw0_rd_out[104]
    DIRECTION OUTPUT ;
    USE SIGNAL ;
    SHAPE ABUTMENT ;
    PORT
      LAYER M3 ;
      RECT 65.007 0.000 65.025 0.054 ;
    END
  END rw0_rd_out[104]
  PIN rw0_rd_out[105]
    DIRECTION OUTPUT ;
    USE SIGNAL ;
    SHAPE ABUTMENT ;
    PORT
      LAYER M3 ;
      RECT 65.187 0.000 65.205 0.054 ;
    END
  END rw0_rd_out[105]
  PIN rw0_rd_out[106]
    DIRECTION OUTPUT ;
    USE SIGNAL ;
    SHAPE ABUTMENT ;
    PORT
      LAYER M3 ;
      RECT 65.367 0.000 65.385 0.054 ;
    END
  END rw0_rd_out[106]
  PIN rw0_rd_out[107]
    DIRECTION OUTPUT ;
    USE SIGNAL ;
    SHAPE ABUTMENT ;
    PORT
      LAYER M3 ;
      RECT 65.547 0.000 65.565 0.054 ;
    END
  END rw0_rd_out[107]
  PIN rw0_rd_out[108]
    DIRECTION OUTPUT ;
    USE SIGNAL ;
    SHAPE ABUTMENT ;
    PORT
      LAYER M3 ;
      RECT 65.727 0.000 65.745 0.054 ;
    END
  END rw0_rd_out[108]
  PIN rw0_rd_out[109]
    DIRECTION OUTPUT ;
    USE SIGNAL ;
    SHAPE ABUTMENT ;
    PORT
      LAYER M3 ;
      RECT 65.907 0.000 65.925 0.054 ;
    END
  END rw0_rd_out[109]
  PIN rw0_rd_out[110]
    DIRECTION OUTPUT ;
    USE SIGNAL ;
    SHAPE ABUTMENT ;
    PORT
      LAYER M3 ;
      RECT 66.087 0.000 66.105 0.054 ;
    END
  END rw0_rd_out[110]
  PIN rw0_rd_out[111]
    DIRECTION OUTPUT ;
    USE SIGNAL ;
    SHAPE ABUTMENT ;
    PORT
      LAYER M3 ;
      RECT 66.267 0.000 66.285 0.054 ;
    END
  END rw0_rd_out[111]
  PIN rw0_rd_out[112]
    DIRECTION OUTPUT ;
    USE SIGNAL ;
    SHAPE ABUTMENT ;
    PORT
      LAYER M3 ;
      RECT 66.447 0.000 66.465 0.054 ;
    END
  END rw0_rd_out[112]
  PIN rw0_rd_out[113]
    DIRECTION OUTPUT ;
    USE SIGNAL ;
    SHAPE ABUTMENT ;
    PORT
      LAYER M3 ;
      RECT 66.627 0.000 66.645 0.054 ;
    END
  END rw0_rd_out[113]
  PIN rw0_rd_out[114]
    DIRECTION OUTPUT ;
    USE SIGNAL ;
    SHAPE ABUTMENT ;
    PORT
      LAYER M3 ;
      RECT 66.807 0.000 66.825 0.054 ;
    END
  END rw0_rd_out[114]
  PIN rw0_rd_out[115]
    DIRECTION OUTPUT ;
    USE SIGNAL ;
    SHAPE ABUTMENT ;
    PORT
      LAYER M3 ;
      RECT 66.987 0.000 67.005 0.054 ;
    END
  END rw0_rd_out[115]
  PIN rw0_rd_out[116]
    DIRECTION OUTPUT ;
    USE SIGNAL ;
    SHAPE ABUTMENT ;
    PORT
      LAYER M3 ;
      RECT 67.167 0.000 67.185 0.054 ;
    END
  END rw0_rd_out[116]
  PIN rw0_rd_out[117]
    DIRECTION OUTPUT ;
    USE SIGNAL ;
    SHAPE ABUTMENT ;
    PORT
      LAYER M3 ;
      RECT 67.347 0.000 67.365 0.054 ;
    END
  END rw0_rd_out[117]
  PIN rw0_rd_out[118]
    DIRECTION OUTPUT ;
    USE SIGNAL ;
    SHAPE ABUTMENT ;
    PORT
      LAYER M3 ;
      RECT 67.527 0.000 67.545 0.054 ;
    END
  END rw0_rd_out[118]
  PIN rw0_rd_out[119]
    DIRECTION OUTPUT ;
    USE SIGNAL ;
    SHAPE ABUTMENT ;
    PORT
      LAYER M3 ;
      RECT 67.707 0.000 67.725 0.054 ;
    END
  END rw0_rd_out[119]
  PIN rw0_rd_out[120]
    DIRECTION OUTPUT ;
    USE SIGNAL ;
    SHAPE ABUTMENT ;
    PORT
      LAYER M3 ;
      RECT 67.887 0.000 67.905 0.054 ;
    END
  END rw0_rd_out[120]
  PIN rw0_rd_out[121]
    DIRECTION OUTPUT ;
    USE SIGNAL ;
    SHAPE ABUTMENT ;
    PORT
      LAYER M3 ;
      RECT 68.067 0.000 68.085 0.054 ;
    END
  END rw0_rd_out[121]
  PIN rw0_rd_out[122]
    DIRECTION OUTPUT ;
    USE SIGNAL ;
    SHAPE ABUTMENT ;
    PORT
      LAYER M3 ;
      RECT 68.247 0.000 68.265 0.054 ;
    END
  END rw0_rd_out[122]
  PIN rw0_rd_out[123]
    DIRECTION OUTPUT ;
    USE SIGNAL ;
    SHAPE ABUTMENT ;
    PORT
      LAYER M3 ;
      RECT 68.427 0.000 68.445 0.054 ;
    END
  END rw0_rd_out[123]
  PIN rw0_rd_out[124]
    DIRECTION OUTPUT ;
    USE SIGNAL ;
    SHAPE ABUTMENT ;
    PORT
      LAYER M3 ;
      RECT 68.607 0.000 68.625 0.054 ;
    END
  END rw0_rd_out[124]
  PIN rw0_rd_out[125]
    DIRECTION OUTPUT ;
    USE SIGNAL ;
    SHAPE ABUTMENT ;
    PORT
      LAYER M3 ;
      RECT 68.787 0.000 68.805 0.054 ;
    END
  END rw0_rd_out[125]
  PIN rw0_rd_out[126]
    DIRECTION OUTPUT ;
    USE SIGNAL ;
    SHAPE ABUTMENT ;
    PORT
      LAYER M3 ;
      RECT 68.967 0.000 68.985 0.054 ;
    END
  END rw0_rd_out[126]
  PIN rw0_rd_out[127]
    DIRECTION OUTPUT ;
    USE SIGNAL ;
    SHAPE ABUTMENT ;
    PORT
      LAYER M3 ;
      RECT 69.147 0.000 69.165 0.054 ;
    END
  END rw0_rd_out[127]
  PIN rw0_rd_out[128]
    DIRECTION OUTPUT ;
    USE SIGNAL ;
    SHAPE ABUTMENT ;
    PORT
      LAYER M3 ;
      RECT 69.327 0.000 69.345 0.054 ;
    END
  END rw0_rd_out[128]
  PIN rw0_rd_out[129]
    DIRECTION OUTPUT ;
    USE SIGNAL ;
    SHAPE ABUTMENT ;
    PORT
      LAYER M3 ;
      RECT 69.507 0.000 69.525 0.054 ;
    END
  END rw0_rd_out[129]
  PIN rw0_rd_out[130]
    DIRECTION OUTPUT ;
    USE SIGNAL ;
    SHAPE ABUTMENT ;
    PORT
      LAYER M3 ;
      RECT 69.687 0.000 69.705 0.054 ;
    END
  END rw0_rd_out[130]
  PIN rw0_rd_out[131]
    DIRECTION OUTPUT ;
    USE SIGNAL ;
    SHAPE ABUTMENT ;
    PORT
      LAYER M3 ;
      RECT 69.867 0.000 69.885 0.054 ;
    END
  END rw0_rd_out[131]
  PIN rw0_rd_out[132]
    DIRECTION OUTPUT ;
    USE SIGNAL ;
    SHAPE ABUTMENT ;
    PORT
      LAYER M3 ;
      RECT 70.047 0.000 70.065 0.054 ;
    END
  END rw0_rd_out[132]
  PIN rw0_rd_out[133]
    DIRECTION OUTPUT ;
    USE SIGNAL ;
    SHAPE ABUTMENT ;
    PORT
      LAYER M3 ;
      RECT 70.227 0.000 70.245 0.054 ;
    END
  END rw0_rd_out[133]
  PIN rw0_rd_out[134]
    DIRECTION OUTPUT ;
    USE SIGNAL ;
    SHAPE ABUTMENT ;
    PORT
      LAYER M3 ;
      RECT 70.407 0.000 70.425 0.054 ;
    END
  END rw0_rd_out[134]
  PIN rw0_rd_out[135]
    DIRECTION OUTPUT ;
    USE SIGNAL ;
    SHAPE ABUTMENT ;
    PORT
      LAYER M3 ;
      RECT 70.587 0.000 70.605 0.054 ;
    END
  END rw0_rd_out[135]
  PIN rw0_rd_out[136]
    DIRECTION OUTPUT ;
    USE SIGNAL ;
    SHAPE ABUTMENT ;
    PORT
      LAYER M3 ;
      RECT 70.767 0.000 70.785 0.054 ;
    END
  END rw0_rd_out[136]
  PIN rw0_rd_out[137]
    DIRECTION OUTPUT ;
    USE SIGNAL ;
    SHAPE ABUTMENT ;
    PORT
      LAYER M3 ;
      RECT 70.947 0.000 70.965 0.054 ;
    END
  END rw0_rd_out[137]
  PIN rw0_rd_out[138]
    DIRECTION OUTPUT ;
    USE SIGNAL ;
    SHAPE ABUTMENT ;
    PORT
      LAYER M3 ;
      RECT 71.127 0.000 71.145 0.054 ;
    END
  END rw0_rd_out[138]
  PIN rw0_rd_out[139]
    DIRECTION OUTPUT ;
    USE SIGNAL ;
    SHAPE ABUTMENT ;
    PORT
      LAYER M3 ;
      RECT 71.307 0.000 71.325 0.054 ;
    END
  END rw0_rd_out[139]
  PIN rw0_rd_out[140]
    DIRECTION OUTPUT ;
    USE SIGNAL ;
    SHAPE ABUTMENT ;
    PORT
      LAYER M3 ;
      RECT 71.487 0.000 71.505 0.054 ;
    END
  END rw0_rd_out[140]
  PIN rw0_rd_out[141]
    DIRECTION OUTPUT ;
    USE SIGNAL ;
    SHAPE ABUTMENT ;
    PORT
      LAYER M3 ;
      RECT 71.667 0.000 71.685 0.054 ;
    END
  END rw0_rd_out[141]
  PIN rw0_rd_out[142]
    DIRECTION OUTPUT ;
    USE SIGNAL ;
    SHAPE ABUTMENT ;
    PORT
      LAYER M3 ;
      RECT 71.847 0.000 71.865 0.054 ;
    END
  END rw0_rd_out[142]
  PIN rw0_rd_out[143]
    DIRECTION OUTPUT ;
    USE SIGNAL ;
    SHAPE ABUTMENT ;
    PORT
      LAYER M3 ;
      RECT 72.027 0.000 72.045 0.054 ;
    END
  END rw0_rd_out[143]
  PIN rw0_rd_out[144]
    DIRECTION OUTPUT ;
    USE SIGNAL ;
    SHAPE ABUTMENT ;
    PORT
      LAYER M3 ;
      RECT 72.207 0.000 72.225 0.054 ;
    END
  END rw0_rd_out[144]
  PIN rw0_rd_out[145]
    DIRECTION OUTPUT ;
    USE SIGNAL ;
    SHAPE ABUTMENT ;
    PORT
      LAYER M3 ;
      RECT 72.387 0.000 72.405 0.054 ;
    END
  END rw0_rd_out[145]
  PIN rw0_rd_out[146]
    DIRECTION OUTPUT ;
    USE SIGNAL ;
    SHAPE ABUTMENT ;
    PORT
      LAYER M3 ;
      RECT 72.567 0.000 72.585 0.054 ;
    END
  END rw0_rd_out[146]
  PIN rw0_rd_out[147]
    DIRECTION OUTPUT ;
    USE SIGNAL ;
    SHAPE ABUTMENT ;
    PORT
      LAYER M3 ;
      RECT 72.747 0.000 72.765 0.054 ;
    END
  END rw0_rd_out[147]
  PIN rw0_rd_out[148]
    DIRECTION OUTPUT ;
    USE SIGNAL ;
    SHAPE ABUTMENT ;
    PORT
      LAYER M3 ;
      RECT 72.927 0.000 72.945 0.054 ;
    END
  END rw0_rd_out[148]
  PIN rw0_rd_out[149]
    DIRECTION OUTPUT ;
    USE SIGNAL ;
    SHAPE ABUTMENT ;
    PORT
      LAYER M3 ;
      RECT 73.107 0.000 73.125 0.054 ;
    END
  END rw0_rd_out[149]
  PIN rw0_rd_out[150]
    DIRECTION OUTPUT ;
    USE SIGNAL ;
    SHAPE ABUTMENT ;
    PORT
      LAYER M3 ;
      RECT 73.287 0.000 73.305 0.054 ;
    END
  END rw0_rd_out[150]
  PIN rw0_rd_out[151]
    DIRECTION OUTPUT ;
    USE SIGNAL ;
    SHAPE ABUTMENT ;
    PORT
      LAYER M3 ;
      RECT 73.467 0.000 73.485 0.054 ;
    END
  END rw0_rd_out[151]
  PIN rw0_rd_out[152]
    DIRECTION OUTPUT ;
    USE SIGNAL ;
    SHAPE ABUTMENT ;
    PORT
      LAYER M3 ;
      RECT 73.647 0.000 73.665 0.054 ;
    END
  END rw0_rd_out[152]
  PIN rw0_rd_out[153]
    DIRECTION OUTPUT ;
    USE SIGNAL ;
    SHAPE ABUTMENT ;
    PORT
      LAYER M3 ;
      RECT 73.827 0.000 73.845 0.054 ;
    END
  END rw0_rd_out[153]
  PIN rw0_rd_out[154]
    DIRECTION OUTPUT ;
    USE SIGNAL ;
    SHAPE ABUTMENT ;
    PORT
      LAYER M3 ;
      RECT 74.007 0.000 74.025 0.054 ;
    END
  END rw0_rd_out[154]
  PIN rw0_rd_out[155]
    DIRECTION OUTPUT ;
    USE SIGNAL ;
    SHAPE ABUTMENT ;
    PORT
      LAYER M3 ;
      RECT 74.187 0.000 74.205 0.054 ;
    END
  END rw0_rd_out[155]
  PIN rw0_rd_out[156]
    DIRECTION OUTPUT ;
    USE SIGNAL ;
    SHAPE ABUTMENT ;
    PORT
      LAYER M3 ;
      RECT 74.367 0.000 74.385 0.054 ;
    END
  END rw0_rd_out[156]
  PIN rw0_rd_out[157]
    DIRECTION OUTPUT ;
    USE SIGNAL ;
    SHAPE ABUTMENT ;
    PORT
      LAYER M3 ;
      RECT 74.547 0.000 74.565 0.054 ;
    END
  END rw0_rd_out[157]
  PIN rw0_rd_out[158]
    DIRECTION OUTPUT ;
    USE SIGNAL ;
    SHAPE ABUTMENT ;
    PORT
      LAYER M3 ;
      RECT 74.727 0.000 74.745 0.054 ;
    END
  END rw0_rd_out[158]
  PIN rw0_rd_out[159]
    DIRECTION OUTPUT ;
    USE SIGNAL ;
    SHAPE ABUTMENT ;
    PORT
      LAYER M3 ;
      RECT 74.907 0.000 74.925 0.054 ;
    END
  END rw0_rd_out[159]
  PIN rw0_rd_out[160]
    DIRECTION OUTPUT ;
    USE SIGNAL ;
    SHAPE ABUTMENT ;
    PORT
      LAYER M3 ;
      RECT 75.087 0.000 75.105 0.054 ;
    END
  END rw0_rd_out[160]
  PIN rw0_rd_out[161]
    DIRECTION OUTPUT ;
    USE SIGNAL ;
    SHAPE ABUTMENT ;
    PORT
      LAYER M3 ;
      RECT 75.267 0.000 75.285 0.054 ;
    END
  END rw0_rd_out[161]
  PIN rw0_rd_out[162]
    DIRECTION OUTPUT ;
    USE SIGNAL ;
    SHAPE ABUTMENT ;
    PORT
      LAYER M3 ;
      RECT 75.447 0.000 75.465 0.054 ;
    END
  END rw0_rd_out[162]
  PIN rw0_rd_out[163]
    DIRECTION OUTPUT ;
    USE SIGNAL ;
    SHAPE ABUTMENT ;
    PORT
      LAYER M3 ;
      RECT 75.627 0.000 75.645 0.054 ;
    END
  END rw0_rd_out[163]
  PIN rw0_rd_out[164]
    DIRECTION OUTPUT ;
    USE SIGNAL ;
    SHAPE ABUTMENT ;
    PORT
      LAYER M3 ;
      RECT 75.807 0.000 75.825 0.054 ;
    END
  END rw0_rd_out[164]
  PIN rw0_rd_out[165]
    DIRECTION OUTPUT ;
    USE SIGNAL ;
    SHAPE ABUTMENT ;
    PORT
      LAYER M3 ;
      RECT 75.987 0.000 76.005 0.054 ;
    END
  END rw0_rd_out[165]
  PIN rw0_rd_out[166]
    DIRECTION OUTPUT ;
    USE SIGNAL ;
    SHAPE ABUTMENT ;
    PORT
      LAYER M3 ;
      RECT 76.167 0.000 76.185 0.054 ;
    END
  END rw0_rd_out[166]
  PIN rw0_rd_out[167]
    DIRECTION OUTPUT ;
    USE SIGNAL ;
    SHAPE ABUTMENT ;
    PORT
      LAYER M3 ;
      RECT 76.347 0.000 76.365 0.054 ;
    END
  END rw0_rd_out[167]
  PIN rw0_rd_out[168]
    DIRECTION OUTPUT ;
    USE SIGNAL ;
    SHAPE ABUTMENT ;
    PORT
      LAYER M3 ;
      RECT 76.527 0.000 76.545 0.054 ;
    END
  END rw0_rd_out[168]
  PIN rw0_rd_out[169]
    DIRECTION OUTPUT ;
    USE SIGNAL ;
    SHAPE ABUTMENT ;
    PORT
      LAYER M3 ;
      RECT 76.707 0.000 76.725 0.054 ;
    END
  END rw0_rd_out[169]
  PIN rw0_rd_out[170]
    DIRECTION OUTPUT ;
    USE SIGNAL ;
    SHAPE ABUTMENT ;
    PORT
      LAYER M3 ;
      RECT 76.887 0.000 76.905 0.054 ;
    END
  END rw0_rd_out[170]
  PIN rw0_rd_out[171]
    DIRECTION OUTPUT ;
    USE SIGNAL ;
    SHAPE ABUTMENT ;
    PORT
      LAYER M3 ;
      RECT 77.067 0.000 77.085 0.054 ;
    END
  END rw0_rd_out[171]
  PIN rw0_rd_out[172]
    DIRECTION OUTPUT ;
    USE SIGNAL ;
    SHAPE ABUTMENT ;
    PORT
      LAYER M3 ;
      RECT 77.247 0.000 77.265 0.054 ;
    END
  END rw0_rd_out[172]
  PIN rw0_rd_out[173]
    DIRECTION OUTPUT ;
    USE SIGNAL ;
    SHAPE ABUTMENT ;
    PORT
      LAYER M3 ;
      RECT 77.427 0.000 77.445 0.054 ;
    END
  END rw0_rd_out[173]
  PIN rw0_rd_out[174]
    DIRECTION OUTPUT ;
    USE SIGNAL ;
    SHAPE ABUTMENT ;
    PORT
      LAYER M3 ;
      RECT 77.607 0.000 77.625 0.054 ;
    END
  END rw0_rd_out[174]
  PIN rw0_rd_out[175]
    DIRECTION OUTPUT ;
    USE SIGNAL ;
    SHAPE ABUTMENT ;
    PORT
      LAYER M3 ;
      RECT 77.787 0.000 77.805 0.054 ;
    END
  END rw0_rd_out[175]
  PIN rw0_rd_out[176]
    DIRECTION OUTPUT ;
    USE SIGNAL ;
    SHAPE ABUTMENT ;
    PORT
      LAYER M3 ;
      RECT 77.967 0.000 77.985 0.054 ;
    END
  END rw0_rd_out[176]
  PIN rw0_rd_out[177]
    DIRECTION OUTPUT ;
    USE SIGNAL ;
    SHAPE ABUTMENT ;
    PORT
      LAYER M3 ;
      RECT 78.147 0.000 78.165 0.054 ;
    END
  END rw0_rd_out[177]
  PIN rw0_rd_out[178]
    DIRECTION OUTPUT ;
    USE SIGNAL ;
    SHAPE ABUTMENT ;
    PORT
      LAYER M3 ;
      RECT 78.327 0.000 78.345 0.054 ;
    END
  END rw0_rd_out[178]
  PIN rw0_rd_out[179]
    DIRECTION OUTPUT ;
    USE SIGNAL ;
    SHAPE ABUTMENT ;
    PORT
      LAYER M3 ;
      RECT 78.507 0.000 78.525 0.054 ;
    END
  END rw0_rd_out[179]
  PIN rw0_rd_out[180]
    DIRECTION OUTPUT ;
    USE SIGNAL ;
    SHAPE ABUTMENT ;
    PORT
      LAYER M3 ;
      RECT 78.687 0.000 78.705 0.054 ;
    END
  END rw0_rd_out[180]
  PIN rw0_rd_out[181]
    DIRECTION OUTPUT ;
    USE SIGNAL ;
    SHAPE ABUTMENT ;
    PORT
      LAYER M3 ;
      RECT 78.867 0.000 78.885 0.054 ;
    END
  END rw0_rd_out[181]
  PIN rw0_rd_out[182]
    DIRECTION OUTPUT ;
    USE SIGNAL ;
    SHAPE ABUTMENT ;
    PORT
      LAYER M3 ;
      RECT 79.047 0.000 79.065 0.054 ;
    END
  END rw0_rd_out[182]
  PIN rw0_rd_out[183]
    DIRECTION OUTPUT ;
    USE SIGNAL ;
    SHAPE ABUTMENT ;
    PORT
      LAYER M3 ;
      RECT 79.227 0.000 79.245 0.054 ;
    END
  END rw0_rd_out[183]
  PIN rw0_rd_out[184]
    DIRECTION OUTPUT ;
    USE SIGNAL ;
    SHAPE ABUTMENT ;
    PORT
      LAYER M3 ;
      RECT 79.407 0.000 79.425 0.054 ;
    END
  END rw0_rd_out[184]
  PIN rw0_rd_out[185]
    DIRECTION OUTPUT ;
    USE SIGNAL ;
    SHAPE ABUTMENT ;
    PORT
      LAYER M3 ;
      RECT 79.587 0.000 79.605 0.054 ;
    END
  END rw0_rd_out[185]
  PIN rw0_rd_out[186]
    DIRECTION OUTPUT ;
    USE SIGNAL ;
    SHAPE ABUTMENT ;
    PORT
      LAYER M3 ;
      RECT 79.767 0.000 79.785 0.054 ;
    END
  END rw0_rd_out[186]
  PIN rw0_rd_out[187]
    DIRECTION OUTPUT ;
    USE SIGNAL ;
    SHAPE ABUTMENT ;
    PORT
      LAYER M3 ;
      RECT 79.947 0.000 79.965 0.054 ;
    END
  END rw0_rd_out[187]
  PIN rw0_rd_out[188]
    DIRECTION OUTPUT ;
    USE SIGNAL ;
    SHAPE ABUTMENT ;
    PORT
      LAYER M3 ;
      RECT 80.127 0.000 80.145 0.054 ;
    END
  END rw0_rd_out[188]
  PIN rw0_rd_out[189]
    DIRECTION OUTPUT ;
    USE SIGNAL ;
    SHAPE ABUTMENT ;
    PORT
      LAYER M3 ;
      RECT 80.307 0.000 80.325 0.054 ;
    END
  END rw0_rd_out[189]
  PIN rw0_rd_out[190]
    DIRECTION OUTPUT ;
    USE SIGNAL ;
    SHAPE ABUTMENT ;
    PORT
      LAYER M3 ;
      RECT 80.487 0.000 80.505 0.054 ;
    END
  END rw0_rd_out[190]
  PIN rw0_rd_out[191]
    DIRECTION OUTPUT ;
    USE SIGNAL ;
    SHAPE ABUTMENT ;
    PORT
      LAYER M3 ;
      RECT 80.667 0.000 80.685 0.054 ;
    END
  END rw0_rd_out[191]
  PIN rw0_rd_out[192]
    DIRECTION OUTPUT ;
    USE SIGNAL ;
    SHAPE ABUTMENT ;
    PORT
      LAYER M3 ;
      RECT 80.847 0.000 80.865 0.054 ;
    END
  END rw0_rd_out[192]
  PIN rw0_rd_out[193]
    DIRECTION OUTPUT ;
    USE SIGNAL ;
    SHAPE ABUTMENT ;
    PORT
      LAYER M3 ;
      RECT 81.027 0.000 81.045 0.054 ;
    END
  END rw0_rd_out[193]
  PIN rw0_rd_out[194]
    DIRECTION OUTPUT ;
    USE SIGNAL ;
    SHAPE ABUTMENT ;
    PORT
      LAYER M3 ;
      RECT 81.207 0.000 81.225 0.054 ;
    END
  END rw0_rd_out[194]
  PIN rw0_rd_out[195]
    DIRECTION OUTPUT ;
    USE SIGNAL ;
    SHAPE ABUTMENT ;
    PORT
      LAYER M3 ;
      RECT 81.387 0.000 81.405 0.054 ;
    END
  END rw0_rd_out[195]
  PIN rw0_rd_out[196]
    DIRECTION OUTPUT ;
    USE SIGNAL ;
    SHAPE ABUTMENT ;
    PORT
      LAYER M3 ;
      RECT 81.567 0.000 81.585 0.054 ;
    END
  END rw0_rd_out[196]
  PIN rw0_rd_out[197]
    DIRECTION OUTPUT ;
    USE SIGNAL ;
    SHAPE ABUTMENT ;
    PORT
      LAYER M3 ;
      RECT 81.747 0.000 81.765 0.054 ;
    END
  END rw0_rd_out[197]
  PIN rw0_rd_out[198]
    DIRECTION OUTPUT ;
    USE SIGNAL ;
    SHAPE ABUTMENT ;
    PORT
      LAYER M3 ;
      RECT 81.927 0.000 81.945 0.054 ;
    END
  END rw0_rd_out[198]
  PIN rw0_rd_out[199]
    DIRECTION OUTPUT ;
    USE SIGNAL ;
    SHAPE ABUTMENT ;
    PORT
      LAYER M3 ;
      RECT 82.107 0.000 82.125 0.054 ;
    END
  END rw0_rd_out[199]
  PIN rw0_rd_out[200]
    DIRECTION OUTPUT ;
    USE SIGNAL ;
    SHAPE ABUTMENT ;
    PORT
      LAYER M3 ;
      RECT 82.287 0.000 82.305 0.054 ;
    END
  END rw0_rd_out[200]
  PIN rw0_rd_out[201]
    DIRECTION OUTPUT ;
    USE SIGNAL ;
    SHAPE ABUTMENT ;
    PORT
      LAYER M3 ;
      RECT 82.467 0.000 82.485 0.054 ;
    END
  END rw0_rd_out[201]
  PIN rw0_rd_out[202]
    DIRECTION OUTPUT ;
    USE SIGNAL ;
    SHAPE ABUTMENT ;
    PORT
      LAYER M3 ;
      RECT 82.647 0.000 82.665 0.054 ;
    END
  END rw0_rd_out[202]
  PIN rw0_rd_out[203]
    DIRECTION OUTPUT ;
    USE SIGNAL ;
    SHAPE ABUTMENT ;
    PORT
      LAYER M3 ;
      RECT 82.827 0.000 82.845 0.054 ;
    END
  END rw0_rd_out[203]
  PIN rw0_rd_out[204]
    DIRECTION OUTPUT ;
    USE SIGNAL ;
    SHAPE ABUTMENT ;
    PORT
      LAYER M3 ;
      RECT 83.007 0.000 83.025 0.054 ;
    END
  END rw0_rd_out[204]
  PIN rw0_rd_out[205]
    DIRECTION OUTPUT ;
    USE SIGNAL ;
    SHAPE ABUTMENT ;
    PORT
      LAYER M3 ;
      RECT 83.187 0.000 83.205 0.054 ;
    END
  END rw0_rd_out[205]
  PIN rw0_rd_out[206]
    DIRECTION OUTPUT ;
    USE SIGNAL ;
    SHAPE ABUTMENT ;
    PORT
      LAYER M3 ;
      RECT 83.367 0.000 83.385 0.054 ;
    END
  END rw0_rd_out[206]
  PIN rw0_rd_out[207]
    DIRECTION OUTPUT ;
    USE SIGNAL ;
    SHAPE ABUTMENT ;
    PORT
      LAYER M3 ;
      RECT 83.547 0.000 83.565 0.054 ;
    END
  END rw0_rd_out[207]
  PIN rw0_rd_out[208]
    DIRECTION OUTPUT ;
    USE SIGNAL ;
    SHAPE ABUTMENT ;
    PORT
      LAYER M3 ;
      RECT 83.727 0.000 83.745 0.054 ;
    END
  END rw0_rd_out[208]
  PIN rw0_rd_out[209]
    DIRECTION OUTPUT ;
    USE SIGNAL ;
    SHAPE ABUTMENT ;
    PORT
      LAYER M3 ;
      RECT 83.907 0.000 83.925 0.054 ;
    END
  END rw0_rd_out[209]
  PIN rw0_rd_out[210]
    DIRECTION OUTPUT ;
    USE SIGNAL ;
    SHAPE ABUTMENT ;
    PORT
      LAYER M3 ;
      RECT 84.087 0.000 84.105 0.054 ;
    END
  END rw0_rd_out[210]
  PIN rw0_rd_out[211]
    DIRECTION OUTPUT ;
    USE SIGNAL ;
    SHAPE ABUTMENT ;
    PORT
      LAYER M3 ;
      RECT 84.267 0.000 84.285 0.054 ;
    END
  END rw0_rd_out[211]
  PIN rw0_rd_out[212]
    DIRECTION OUTPUT ;
    USE SIGNAL ;
    SHAPE ABUTMENT ;
    PORT
      LAYER M3 ;
      RECT 84.447 0.000 84.465 0.054 ;
    END
  END rw0_rd_out[212]
  PIN rw0_rd_out[213]
    DIRECTION OUTPUT ;
    USE SIGNAL ;
    SHAPE ABUTMENT ;
    PORT
      LAYER M3 ;
      RECT 84.627 0.000 84.645 0.054 ;
    END
  END rw0_rd_out[213]
  PIN rw0_rd_out[214]
    DIRECTION OUTPUT ;
    USE SIGNAL ;
    SHAPE ABUTMENT ;
    PORT
      LAYER M3 ;
      RECT 84.807 0.000 84.825 0.054 ;
    END
  END rw0_rd_out[214]
  PIN rw0_rd_out[215]
    DIRECTION OUTPUT ;
    USE SIGNAL ;
    SHAPE ABUTMENT ;
    PORT
      LAYER M3 ;
      RECT 84.987 0.000 85.005 0.054 ;
    END
  END rw0_rd_out[215]
  PIN rw0_rd_out[216]
    DIRECTION OUTPUT ;
    USE SIGNAL ;
    SHAPE ABUTMENT ;
    PORT
      LAYER M3 ;
      RECT 85.167 0.000 85.185 0.054 ;
    END
  END rw0_rd_out[216]
  PIN rw0_rd_out[217]
    DIRECTION OUTPUT ;
    USE SIGNAL ;
    SHAPE ABUTMENT ;
    PORT
      LAYER M3 ;
      RECT 85.347 0.000 85.365 0.054 ;
    END
  END rw0_rd_out[217]
  PIN rw0_rd_out[218]
    DIRECTION OUTPUT ;
    USE SIGNAL ;
    SHAPE ABUTMENT ;
    PORT
      LAYER M3 ;
      RECT 85.527 0.000 85.545 0.054 ;
    END
  END rw0_rd_out[218]
  PIN rw0_rd_out[219]
    DIRECTION OUTPUT ;
    USE SIGNAL ;
    SHAPE ABUTMENT ;
    PORT
      LAYER M3 ;
      RECT 85.707 0.000 85.725 0.054 ;
    END
  END rw0_rd_out[219]
  PIN rw0_rd_out[220]
    DIRECTION OUTPUT ;
    USE SIGNAL ;
    SHAPE ABUTMENT ;
    PORT
      LAYER M3 ;
      RECT 85.887 0.000 85.905 0.054 ;
    END
  END rw0_rd_out[220]
  PIN rw0_rd_out[221]
    DIRECTION OUTPUT ;
    USE SIGNAL ;
    SHAPE ABUTMENT ;
    PORT
      LAYER M3 ;
      RECT 86.067 0.000 86.085 0.054 ;
    END
  END rw0_rd_out[221]
  PIN rw0_rd_out[222]
    DIRECTION OUTPUT ;
    USE SIGNAL ;
    SHAPE ABUTMENT ;
    PORT
      LAYER M3 ;
      RECT 86.247 0.000 86.265 0.054 ;
    END
  END rw0_rd_out[222]
  PIN rw0_rd_out[223]
    DIRECTION OUTPUT ;
    USE SIGNAL ;
    SHAPE ABUTMENT ;
    PORT
      LAYER M3 ;
      RECT 86.427 0.000 86.445 0.054 ;
    END
  END rw0_rd_out[223]
  PIN rw0_rd_out[224]
    DIRECTION OUTPUT ;
    USE SIGNAL ;
    SHAPE ABUTMENT ;
    PORT
      LAYER M3 ;
      RECT 86.607 0.000 86.625 0.054 ;
    END
  END rw0_rd_out[224]
  PIN rw0_rd_out[225]
    DIRECTION OUTPUT ;
    USE SIGNAL ;
    SHAPE ABUTMENT ;
    PORT
      LAYER M3 ;
      RECT 86.787 0.000 86.805 0.054 ;
    END
  END rw0_rd_out[225]
  PIN rw0_rd_out[226]
    DIRECTION OUTPUT ;
    USE SIGNAL ;
    SHAPE ABUTMENT ;
    PORT
      LAYER M3 ;
      RECT 86.967 0.000 86.985 0.054 ;
    END
  END rw0_rd_out[226]
  PIN rw0_rd_out[227]
    DIRECTION OUTPUT ;
    USE SIGNAL ;
    SHAPE ABUTMENT ;
    PORT
      LAYER M3 ;
      RECT 87.147 0.000 87.165 0.054 ;
    END
  END rw0_rd_out[227]
  PIN rw0_rd_out[228]
    DIRECTION OUTPUT ;
    USE SIGNAL ;
    SHAPE ABUTMENT ;
    PORT
      LAYER M3 ;
      RECT 87.327 0.000 87.345 0.054 ;
    END
  END rw0_rd_out[228]
  PIN rw0_rd_out[229]
    DIRECTION OUTPUT ;
    USE SIGNAL ;
    SHAPE ABUTMENT ;
    PORT
      LAYER M3 ;
      RECT 87.507 0.000 87.525 0.054 ;
    END
  END rw0_rd_out[229]
  PIN rw0_rd_out[230]
    DIRECTION OUTPUT ;
    USE SIGNAL ;
    SHAPE ABUTMENT ;
    PORT
      LAYER M3 ;
      RECT 87.687 0.000 87.705 0.054 ;
    END
  END rw0_rd_out[230]
  PIN rw0_rd_out[231]
    DIRECTION OUTPUT ;
    USE SIGNAL ;
    SHAPE ABUTMENT ;
    PORT
      LAYER M3 ;
      RECT 87.867 0.000 87.885 0.054 ;
    END
  END rw0_rd_out[231]
  PIN rw0_rd_out[232]
    DIRECTION OUTPUT ;
    USE SIGNAL ;
    SHAPE ABUTMENT ;
    PORT
      LAYER M3 ;
      RECT 88.047 0.000 88.065 0.054 ;
    END
  END rw0_rd_out[232]
  PIN rw0_rd_out[233]
    DIRECTION OUTPUT ;
    USE SIGNAL ;
    SHAPE ABUTMENT ;
    PORT
      LAYER M3 ;
      RECT 88.227 0.000 88.245 0.054 ;
    END
  END rw0_rd_out[233]
  PIN rw0_rd_out[234]
    DIRECTION OUTPUT ;
    USE SIGNAL ;
    SHAPE ABUTMENT ;
    PORT
      LAYER M3 ;
      RECT 88.407 0.000 88.425 0.054 ;
    END
  END rw0_rd_out[234]
  PIN rw0_rd_out[235]
    DIRECTION OUTPUT ;
    USE SIGNAL ;
    SHAPE ABUTMENT ;
    PORT
      LAYER M3 ;
      RECT 88.587 0.000 88.605 0.054 ;
    END
  END rw0_rd_out[235]
  PIN rw0_rd_out[236]
    DIRECTION OUTPUT ;
    USE SIGNAL ;
    SHAPE ABUTMENT ;
    PORT
      LAYER M3 ;
      RECT 88.767 0.000 88.785 0.054 ;
    END
  END rw0_rd_out[236]
  PIN rw0_rd_out[237]
    DIRECTION OUTPUT ;
    USE SIGNAL ;
    SHAPE ABUTMENT ;
    PORT
      LAYER M3 ;
      RECT 88.947 0.000 88.965 0.054 ;
    END
  END rw0_rd_out[237]
  PIN rw0_rd_out[238]
    DIRECTION OUTPUT ;
    USE SIGNAL ;
    SHAPE ABUTMENT ;
    PORT
      LAYER M3 ;
      RECT 89.127 0.000 89.145 0.054 ;
    END
  END rw0_rd_out[238]
  PIN rw0_rd_out[239]
    DIRECTION OUTPUT ;
    USE SIGNAL ;
    SHAPE ABUTMENT ;
    PORT
      LAYER M3 ;
      RECT 89.307 0.000 89.325 0.054 ;
    END
  END rw0_rd_out[239]
  PIN rw0_rd_out[240]
    DIRECTION OUTPUT ;
    USE SIGNAL ;
    SHAPE ABUTMENT ;
    PORT
      LAYER M3 ;
      RECT 89.487 0.000 89.505 0.054 ;
    END
  END rw0_rd_out[240]
  PIN rw0_rd_out[241]
    DIRECTION OUTPUT ;
    USE SIGNAL ;
    SHAPE ABUTMENT ;
    PORT
      LAYER M3 ;
      RECT 89.667 0.000 89.685 0.054 ;
    END
  END rw0_rd_out[241]
  PIN rw0_rd_out[242]
    DIRECTION OUTPUT ;
    USE SIGNAL ;
    SHAPE ABUTMENT ;
    PORT
      LAYER M3 ;
      RECT 89.847 0.000 89.865 0.054 ;
    END
  END rw0_rd_out[242]
  PIN rw0_rd_out[243]
    DIRECTION OUTPUT ;
    USE SIGNAL ;
    SHAPE ABUTMENT ;
    PORT
      LAYER M3 ;
      RECT 90.027 0.000 90.045 0.054 ;
    END
  END rw0_rd_out[243]
  PIN rw0_rd_out[244]
    DIRECTION OUTPUT ;
    USE SIGNAL ;
    SHAPE ABUTMENT ;
    PORT
      LAYER M3 ;
      RECT 90.207 0.000 90.225 0.054 ;
    END
  END rw0_rd_out[244]
  PIN rw0_rd_out[245]
    DIRECTION OUTPUT ;
    USE SIGNAL ;
    SHAPE ABUTMENT ;
    PORT
      LAYER M3 ;
      RECT 90.387 0.000 90.405 0.054 ;
    END
  END rw0_rd_out[245]
  PIN rw0_rd_out[246]
    DIRECTION OUTPUT ;
    USE SIGNAL ;
    SHAPE ABUTMENT ;
    PORT
      LAYER M3 ;
      RECT 90.567 0.000 90.585 0.054 ;
    END
  END rw0_rd_out[246]
  PIN rw0_rd_out[247]
    DIRECTION OUTPUT ;
    USE SIGNAL ;
    SHAPE ABUTMENT ;
    PORT
      LAYER M3 ;
      RECT 90.747 0.000 90.765 0.054 ;
    END
  END rw0_rd_out[247]
  PIN rw0_rd_out[248]
    DIRECTION OUTPUT ;
    USE SIGNAL ;
    SHAPE ABUTMENT ;
    PORT
      LAYER M3 ;
      RECT 90.927 0.000 90.945 0.054 ;
    END
  END rw0_rd_out[248]
  PIN rw0_rd_out[249]
    DIRECTION OUTPUT ;
    USE SIGNAL ;
    SHAPE ABUTMENT ;
    PORT
      LAYER M3 ;
      RECT 91.107 0.000 91.125 0.054 ;
    END
  END rw0_rd_out[249]
  PIN rw0_rd_out[250]
    DIRECTION OUTPUT ;
    USE SIGNAL ;
    SHAPE ABUTMENT ;
    PORT
      LAYER M3 ;
      RECT 91.287 0.000 91.305 0.054 ;
    END
  END rw0_rd_out[250]
  PIN rw0_rd_out[251]
    DIRECTION OUTPUT ;
    USE SIGNAL ;
    SHAPE ABUTMENT ;
    PORT
      LAYER M3 ;
      RECT 91.467 0.000 91.485 0.054 ;
    END
  END rw0_rd_out[251]
  PIN rw0_rd_out[252]
    DIRECTION OUTPUT ;
    USE SIGNAL ;
    SHAPE ABUTMENT ;
    PORT
      LAYER M3 ;
      RECT 91.647 0.000 91.665 0.054 ;
    END
  END rw0_rd_out[252]
  PIN rw0_rd_out[253]
    DIRECTION OUTPUT ;
    USE SIGNAL ;
    SHAPE ABUTMENT ;
    PORT
      LAYER M3 ;
      RECT 91.827 0.000 91.845 0.054 ;
    END
  END rw0_rd_out[253]
  PIN rw0_rd_out[254]
    DIRECTION OUTPUT ;
    USE SIGNAL ;
    SHAPE ABUTMENT ;
    PORT
      LAYER M3 ;
      RECT 92.007 0.000 92.025 0.054 ;
    END
  END rw0_rd_out[254]
  PIN rw0_rd_out[255]
    DIRECTION OUTPUT ;
    USE SIGNAL ;
    SHAPE ABUTMENT ;
    PORT
      LAYER M3 ;
      RECT 92.187 0.000 92.205 0.054 ;
    END
  END rw0_rd_out[255]
  PIN rw0_rd_out[256]
    DIRECTION OUTPUT ;
    USE SIGNAL ;
    SHAPE ABUTMENT ;
    PORT
      LAYER M3 ;
      RECT 0.207 34.506 0.225 34.560 ;
    END
  END rw0_rd_out[256]
  PIN rw0_rd_out[257]
    DIRECTION OUTPUT ;
    USE SIGNAL ;
    SHAPE ABUTMENT ;
    PORT
      LAYER M3 ;
      RECT 0.567 34.506 0.585 34.560 ;
    END
  END rw0_rd_out[257]
  PIN rw0_rd_out[258]
    DIRECTION OUTPUT ;
    USE SIGNAL ;
    SHAPE ABUTMENT ;
    PORT
      LAYER M3 ;
      RECT 0.927 34.506 0.945 34.560 ;
    END
  END rw0_rd_out[258]
  PIN rw0_rd_out[259]
    DIRECTION OUTPUT ;
    USE SIGNAL ;
    SHAPE ABUTMENT ;
    PORT
      LAYER M3 ;
      RECT 1.287 34.506 1.305 34.560 ;
    END
  END rw0_rd_out[259]
  PIN rw0_rd_out[260]
    DIRECTION OUTPUT ;
    USE SIGNAL ;
    SHAPE ABUTMENT ;
    PORT
      LAYER M3 ;
      RECT 1.647 34.506 1.665 34.560 ;
    END
  END rw0_rd_out[260]
  PIN rw0_rd_out[261]
    DIRECTION OUTPUT ;
    USE SIGNAL ;
    SHAPE ABUTMENT ;
    PORT
      LAYER M3 ;
      RECT 2.007 34.506 2.025 34.560 ;
    END
  END rw0_rd_out[261]
  PIN rw0_rd_out[262]
    DIRECTION OUTPUT ;
    USE SIGNAL ;
    SHAPE ABUTMENT ;
    PORT
      LAYER M3 ;
      RECT 2.367 34.506 2.385 34.560 ;
    END
  END rw0_rd_out[262]
  PIN rw0_rd_out[263]
    DIRECTION OUTPUT ;
    USE SIGNAL ;
    SHAPE ABUTMENT ;
    PORT
      LAYER M3 ;
      RECT 2.727 34.506 2.745 34.560 ;
    END
  END rw0_rd_out[263]
  PIN rw0_rd_out[264]
    DIRECTION OUTPUT ;
    USE SIGNAL ;
    SHAPE ABUTMENT ;
    PORT
      LAYER M3 ;
      RECT 3.087 34.506 3.105 34.560 ;
    END
  END rw0_rd_out[264]
  PIN rw0_rd_out[265]
    DIRECTION OUTPUT ;
    USE SIGNAL ;
    SHAPE ABUTMENT ;
    PORT
      LAYER M3 ;
      RECT 3.447 34.506 3.465 34.560 ;
    END
  END rw0_rd_out[265]
  PIN rw0_rd_out[266]
    DIRECTION OUTPUT ;
    USE SIGNAL ;
    SHAPE ABUTMENT ;
    PORT
      LAYER M3 ;
      RECT 3.807 34.506 3.825 34.560 ;
    END
  END rw0_rd_out[266]
  PIN rw0_rd_out[267]
    DIRECTION OUTPUT ;
    USE SIGNAL ;
    SHAPE ABUTMENT ;
    PORT
      LAYER M3 ;
      RECT 4.167 34.506 4.185 34.560 ;
    END
  END rw0_rd_out[267]
  PIN rw0_rd_out[268]
    DIRECTION OUTPUT ;
    USE SIGNAL ;
    SHAPE ABUTMENT ;
    PORT
      LAYER M3 ;
      RECT 4.527 34.506 4.545 34.560 ;
    END
  END rw0_rd_out[268]
  PIN rw0_rd_out[269]
    DIRECTION OUTPUT ;
    USE SIGNAL ;
    SHAPE ABUTMENT ;
    PORT
      LAYER M3 ;
      RECT 4.887 34.506 4.905 34.560 ;
    END
  END rw0_rd_out[269]
  PIN rw0_rd_out[270]
    DIRECTION OUTPUT ;
    USE SIGNAL ;
    SHAPE ABUTMENT ;
    PORT
      LAYER M3 ;
      RECT 5.247 34.506 5.265 34.560 ;
    END
  END rw0_rd_out[270]
  PIN rw0_rd_out[271]
    DIRECTION OUTPUT ;
    USE SIGNAL ;
    SHAPE ABUTMENT ;
    PORT
      LAYER M3 ;
      RECT 5.607 34.506 5.625 34.560 ;
    END
  END rw0_rd_out[271]
  PIN rw0_rd_out[272]
    DIRECTION OUTPUT ;
    USE SIGNAL ;
    SHAPE ABUTMENT ;
    PORT
      LAYER M3 ;
      RECT 5.967 34.506 5.985 34.560 ;
    END
  END rw0_rd_out[272]
  PIN rw0_rd_out[273]
    DIRECTION OUTPUT ;
    USE SIGNAL ;
    SHAPE ABUTMENT ;
    PORT
      LAYER M3 ;
      RECT 6.327 34.506 6.345 34.560 ;
    END
  END rw0_rd_out[273]
  PIN rw0_rd_out[274]
    DIRECTION OUTPUT ;
    USE SIGNAL ;
    SHAPE ABUTMENT ;
    PORT
      LAYER M3 ;
      RECT 6.687 34.506 6.705 34.560 ;
    END
  END rw0_rd_out[274]
  PIN rw0_rd_out[275]
    DIRECTION OUTPUT ;
    USE SIGNAL ;
    SHAPE ABUTMENT ;
    PORT
      LAYER M3 ;
      RECT 7.047 34.506 7.065 34.560 ;
    END
  END rw0_rd_out[275]
  PIN rw0_rd_out[276]
    DIRECTION OUTPUT ;
    USE SIGNAL ;
    SHAPE ABUTMENT ;
    PORT
      LAYER M3 ;
      RECT 7.407 34.506 7.425 34.560 ;
    END
  END rw0_rd_out[276]
  PIN rw0_rd_out[277]
    DIRECTION OUTPUT ;
    USE SIGNAL ;
    SHAPE ABUTMENT ;
    PORT
      LAYER M3 ;
      RECT 7.767 34.506 7.785 34.560 ;
    END
  END rw0_rd_out[277]
  PIN rw0_rd_out[278]
    DIRECTION OUTPUT ;
    USE SIGNAL ;
    SHAPE ABUTMENT ;
    PORT
      LAYER M3 ;
      RECT 8.127 34.506 8.145 34.560 ;
    END
  END rw0_rd_out[278]
  PIN rw0_rd_out[279]
    DIRECTION OUTPUT ;
    USE SIGNAL ;
    SHAPE ABUTMENT ;
    PORT
      LAYER M3 ;
      RECT 8.487 34.506 8.505 34.560 ;
    END
  END rw0_rd_out[279]
  PIN rw0_rd_out[280]
    DIRECTION OUTPUT ;
    USE SIGNAL ;
    SHAPE ABUTMENT ;
    PORT
      LAYER M3 ;
      RECT 8.847 34.506 8.865 34.560 ;
    END
  END rw0_rd_out[280]
  PIN rw0_rd_out[281]
    DIRECTION OUTPUT ;
    USE SIGNAL ;
    SHAPE ABUTMENT ;
    PORT
      LAYER M3 ;
      RECT 9.207 34.506 9.225 34.560 ;
    END
  END rw0_rd_out[281]
  PIN rw0_rd_out[282]
    DIRECTION OUTPUT ;
    USE SIGNAL ;
    SHAPE ABUTMENT ;
    PORT
      LAYER M3 ;
      RECT 9.567 34.506 9.585 34.560 ;
    END
  END rw0_rd_out[282]
  PIN rw0_rd_out[283]
    DIRECTION OUTPUT ;
    USE SIGNAL ;
    SHAPE ABUTMENT ;
    PORT
      LAYER M3 ;
      RECT 9.927 34.506 9.945 34.560 ;
    END
  END rw0_rd_out[283]
  PIN rw0_rd_out[284]
    DIRECTION OUTPUT ;
    USE SIGNAL ;
    SHAPE ABUTMENT ;
    PORT
      LAYER M3 ;
      RECT 10.287 34.506 10.305 34.560 ;
    END
  END rw0_rd_out[284]
  PIN rw0_rd_out[285]
    DIRECTION OUTPUT ;
    USE SIGNAL ;
    SHAPE ABUTMENT ;
    PORT
      LAYER M3 ;
      RECT 10.647 34.506 10.665 34.560 ;
    END
  END rw0_rd_out[285]
  PIN rw0_rd_out[286]
    DIRECTION OUTPUT ;
    USE SIGNAL ;
    SHAPE ABUTMENT ;
    PORT
      LAYER M3 ;
      RECT 11.007 34.506 11.025 34.560 ;
    END
  END rw0_rd_out[286]
  PIN rw0_rd_out[287]
    DIRECTION OUTPUT ;
    USE SIGNAL ;
    SHAPE ABUTMENT ;
    PORT
      LAYER M3 ;
      RECT 11.367 34.506 11.385 34.560 ;
    END
  END rw0_rd_out[287]
  PIN rw0_rd_out[288]
    DIRECTION OUTPUT ;
    USE SIGNAL ;
    SHAPE ABUTMENT ;
    PORT
      LAYER M3 ;
      RECT 11.727 34.506 11.745 34.560 ;
    END
  END rw0_rd_out[288]
  PIN rw0_rd_out[289]
    DIRECTION OUTPUT ;
    USE SIGNAL ;
    SHAPE ABUTMENT ;
    PORT
      LAYER M3 ;
      RECT 12.087 34.506 12.105 34.560 ;
    END
  END rw0_rd_out[289]
  PIN rw0_rd_out[290]
    DIRECTION OUTPUT ;
    USE SIGNAL ;
    SHAPE ABUTMENT ;
    PORT
      LAYER M3 ;
      RECT 12.447 34.506 12.465 34.560 ;
    END
  END rw0_rd_out[290]
  PIN rw0_rd_out[291]
    DIRECTION OUTPUT ;
    USE SIGNAL ;
    SHAPE ABUTMENT ;
    PORT
      LAYER M3 ;
      RECT 12.807 34.506 12.825 34.560 ;
    END
  END rw0_rd_out[291]
  PIN rw0_rd_out[292]
    DIRECTION OUTPUT ;
    USE SIGNAL ;
    SHAPE ABUTMENT ;
    PORT
      LAYER M3 ;
      RECT 13.167 34.506 13.185 34.560 ;
    END
  END rw0_rd_out[292]
  PIN rw0_rd_out[293]
    DIRECTION OUTPUT ;
    USE SIGNAL ;
    SHAPE ABUTMENT ;
    PORT
      LAYER M3 ;
      RECT 13.527 34.506 13.545 34.560 ;
    END
  END rw0_rd_out[293]
  PIN rw0_rd_out[294]
    DIRECTION OUTPUT ;
    USE SIGNAL ;
    SHAPE ABUTMENT ;
    PORT
      LAYER M3 ;
      RECT 13.887 34.506 13.905 34.560 ;
    END
  END rw0_rd_out[294]
  PIN rw0_rd_out[295]
    DIRECTION OUTPUT ;
    USE SIGNAL ;
    SHAPE ABUTMENT ;
    PORT
      LAYER M3 ;
      RECT 14.247 34.506 14.265 34.560 ;
    END
  END rw0_rd_out[295]
  PIN rw0_rd_out[296]
    DIRECTION OUTPUT ;
    USE SIGNAL ;
    SHAPE ABUTMENT ;
    PORT
      LAYER M3 ;
      RECT 14.607 34.506 14.625 34.560 ;
    END
  END rw0_rd_out[296]
  PIN rw0_rd_out[297]
    DIRECTION OUTPUT ;
    USE SIGNAL ;
    SHAPE ABUTMENT ;
    PORT
      LAYER M3 ;
      RECT 14.967 34.506 14.985 34.560 ;
    END
  END rw0_rd_out[297]
  PIN rw0_rd_out[298]
    DIRECTION OUTPUT ;
    USE SIGNAL ;
    SHAPE ABUTMENT ;
    PORT
      LAYER M3 ;
      RECT 15.327 34.506 15.345 34.560 ;
    END
  END rw0_rd_out[298]
  PIN rw0_rd_out[299]
    DIRECTION OUTPUT ;
    USE SIGNAL ;
    SHAPE ABUTMENT ;
    PORT
      LAYER M3 ;
      RECT 15.687 34.506 15.705 34.560 ;
    END
  END rw0_rd_out[299]
  PIN rw0_rd_out[300]
    DIRECTION OUTPUT ;
    USE SIGNAL ;
    SHAPE ABUTMENT ;
    PORT
      LAYER M3 ;
      RECT 16.047 34.506 16.065 34.560 ;
    END
  END rw0_rd_out[300]
  PIN rw0_rd_out[301]
    DIRECTION OUTPUT ;
    USE SIGNAL ;
    SHAPE ABUTMENT ;
    PORT
      LAYER M3 ;
      RECT 16.407 34.506 16.425 34.560 ;
    END
  END rw0_rd_out[301]
  PIN rw0_rd_out[302]
    DIRECTION OUTPUT ;
    USE SIGNAL ;
    SHAPE ABUTMENT ;
    PORT
      LAYER M3 ;
      RECT 16.767 34.506 16.785 34.560 ;
    END
  END rw0_rd_out[302]
  PIN rw0_rd_out[303]
    DIRECTION OUTPUT ;
    USE SIGNAL ;
    SHAPE ABUTMENT ;
    PORT
      LAYER M3 ;
      RECT 17.127 34.506 17.145 34.560 ;
    END
  END rw0_rd_out[303]
  PIN rw0_rd_out[304]
    DIRECTION OUTPUT ;
    USE SIGNAL ;
    SHAPE ABUTMENT ;
    PORT
      LAYER M3 ;
      RECT 17.487 34.506 17.505 34.560 ;
    END
  END rw0_rd_out[304]
  PIN rw0_rd_out[305]
    DIRECTION OUTPUT ;
    USE SIGNAL ;
    SHAPE ABUTMENT ;
    PORT
      LAYER M3 ;
      RECT 17.847 34.506 17.865 34.560 ;
    END
  END rw0_rd_out[305]
  PIN rw0_rd_out[306]
    DIRECTION OUTPUT ;
    USE SIGNAL ;
    SHAPE ABUTMENT ;
    PORT
      LAYER M3 ;
      RECT 18.207 34.506 18.225 34.560 ;
    END
  END rw0_rd_out[306]
  PIN rw0_rd_out[307]
    DIRECTION OUTPUT ;
    USE SIGNAL ;
    SHAPE ABUTMENT ;
    PORT
      LAYER M3 ;
      RECT 18.567 34.506 18.585 34.560 ;
    END
  END rw0_rd_out[307]
  PIN rw0_rd_out[308]
    DIRECTION OUTPUT ;
    USE SIGNAL ;
    SHAPE ABUTMENT ;
    PORT
      LAYER M3 ;
      RECT 18.927 34.506 18.945 34.560 ;
    END
  END rw0_rd_out[308]
  PIN rw0_rd_out[309]
    DIRECTION OUTPUT ;
    USE SIGNAL ;
    SHAPE ABUTMENT ;
    PORT
      LAYER M3 ;
      RECT 19.287 34.506 19.305 34.560 ;
    END
  END rw0_rd_out[309]
  PIN rw0_rd_out[310]
    DIRECTION OUTPUT ;
    USE SIGNAL ;
    SHAPE ABUTMENT ;
    PORT
      LAYER M3 ;
      RECT 19.647 34.506 19.665 34.560 ;
    END
  END rw0_rd_out[310]
  PIN rw0_rd_out[311]
    DIRECTION OUTPUT ;
    USE SIGNAL ;
    SHAPE ABUTMENT ;
    PORT
      LAYER M3 ;
      RECT 20.007 34.506 20.025 34.560 ;
    END
  END rw0_rd_out[311]
  PIN rw0_rd_out[312]
    DIRECTION OUTPUT ;
    USE SIGNAL ;
    SHAPE ABUTMENT ;
    PORT
      LAYER M3 ;
      RECT 20.367 34.506 20.385 34.560 ;
    END
  END rw0_rd_out[312]
  PIN rw0_rd_out[313]
    DIRECTION OUTPUT ;
    USE SIGNAL ;
    SHAPE ABUTMENT ;
    PORT
      LAYER M3 ;
      RECT 20.727 34.506 20.745 34.560 ;
    END
  END rw0_rd_out[313]
  PIN rw0_rd_out[314]
    DIRECTION OUTPUT ;
    USE SIGNAL ;
    SHAPE ABUTMENT ;
    PORT
      LAYER M3 ;
      RECT 21.087 34.506 21.105 34.560 ;
    END
  END rw0_rd_out[314]
  PIN rw0_rd_out[315]
    DIRECTION OUTPUT ;
    USE SIGNAL ;
    SHAPE ABUTMENT ;
    PORT
      LAYER M3 ;
      RECT 21.447 34.506 21.465 34.560 ;
    END
  END rw0_rd_out[315]
  PIN rw0_rd_out[316]
    DIRECTION OUTPUT ;
    USE SIGNAL ;
    SHAPE ABUTMENT ;
    PORT
      LAYER M3 ;
      RECT 21.807 34.506 21.825 34.560 ;
    END
  END rw0_rd_out[316]
  PIN rw0_rd_out[317]
    DIRECTION OUTPUT ;
    USE SIGNAL ;
    SHAPE ABUTMENT ;
    PORT
      LAYER M3 ;
      RECT 22.167 34.506 22.185 34.560 ;
    END
  END rw0_rd_out[317]
  PIN rw0_rd_out[318]
    DIRECTION OUTPUT ;
    USE SIGNAL ;
    SHAPE ABUTMENT ;
    PORT
      LAYER M3 ;
      RECT 22.527 34.506 22.545 34.560 ;
    END
  END rw0_rd_out[318]
  PIN rw0_rd_out[319]
    DIRECTION OUTPUT ;
    USE SIGNAL ;
    SHAPE ABUTMENT ;
    PORT
      LAYER M3 ;
      RECT 22.887 34.506 22.905 34.560 ;
    END
  END rw0_rd_out[319]
  PIN rw0_rd_out[320]
    DIRECTION OUTPUT ;
    USE SIGNAL ;
    SHAPE ABUTMENT ;
    PORT
      LAYER M3 ;
      RECT 23.247 34.506 23.265 34.560 ;
    END
  END rw0_rd_out[320]
  PIN rw0_rd_out[321]
    DIRECTION OUTPUT ;
    USE SIGNAL ;
    SHAPE ABUTMENT ;
    PORT
      LAYER M3 ;
      RECT 23.607 34.506 23.625 34.560 ;
    END
  END rw0_rd_out[321]
  PIN rw0_rd_out[322]
    DIRECTION OUTPUT ;
    USE SIGNAL ;
    SHAPE ABUTMENT ;
    PORT
      LAYER M3 ;
      RECT 23.967 34.506 23.985 34.560 ;
    END
  END rw0_rd_out[322]
  PIN rw0_rd_out[323]
    DIRECTION OUTPUT ;
    USE SIGNAL ;
    SHAPE ABUTMENT ;
    PORT
      LAYER M3 ;
      RECT 24.327 34.506 24.345 34.560 ;
    END
  END rw0_rd_out[323]
  PIN rw0_rd_out[324]
    DIRECTION OUTPUT ;
    USE SIGNAL ;
    SHAPE ABUTMENT ;
    PORT
      LAYER M3 ;
      RECT 24.687 34.506 24.705 34.560 ;
    END
  END rw0_rd_out[324]
  PIN rw0_rd_out[325]
    DIRECTION OUTPUT ;
    USE SIGNAL ;
    SHAPE ABUTMENT ;
    PORT
      LAYER M3 ;
      RECT 25.047 34.506 25.065 34.560 ;
    END
  END rw0_rd_out[325]
  PIN rw0_rd_out[326]
    DIRECTION OUTPUT ;
    USE SIGNAL ;
    SHAPE ABUTMENT ;
    PORT
      LAYER M3 ;
      RECT 25.407 34.506 25.425 34.560 ;
    END
  END rw0_rd_out[326]
  PIN rw0_rd_out[327]
    DIRECTION OUTPUT ;
    USE SIGNAL ;
    SHAPE ABUTMENT ;
    PORT
      LAYER M3 ;
      RECT 25.767 34.506 25.785 34.560 ;
    END
  END rw0_rd_out[327]
  PIN rw0_rd_out[328]
    DIRECTION OUTPUT ;
    USE SIGNAL ;
    SHAPE ABUTMENT ;
    PORT
      LAYER M3 ;
      RECT 26.127 34.506 26.145 34.560 ;
    END
  END rw0_rd_out[328]
  PIN rw0_rd_out[329]
    DIRECTION OUTPUT ;
    USE SIGNAL ;
    SHAPE ABUTMENT ;
    PORT
      LAYER M3 ;
      RECT 26.487 34.506 26.505 34.560 ;
    END
  END rw0_rd_out[329]
  PIN rw0_rd_out[330]
    DIRECTION OUTPUT ;
    USE SIGNAL ;
    SHAPE ABUTMENT ;
    PORT
      LAYER M3 ;
      RECT 26.847 34.506 26.865 34.560 ;
    END
  END rw0_rd_out[330]
  PIN rw0_rd_out[331]
    DIRECTION OUTPUT ;
    USE SIGNAL ;
    SHAPE ABUTMENT ;
    PORT
      LAYER M3 ;
      RECT 27.207 34.506 27.225 34.560 ;
    END
  END rw0_rd_out[331]
  PIN rw0_rd_out[332]
    DIRECTION OUTPUT ;
    USE SIGNAL ;
    SHAPE ABUTMENT ;
    PORT
      LAYER M3 ;
      RECT 27.567 34.506 27.585 34.560 ;
    END
  END rw0_rd_out[332]
  PIN rw0_rd_out[333]
    DIRECTION OUTPUT ;
    USE SIGNAL ;
    SHAPE ABUTMENT ;
    PORT
      LAYER M3 ;
      RECT 27.927 34.506 27.945 34.560 ;
    END
  END rw0_rd_out[333]
  PIN rw0_rd_out[334]
    DIRECTION OUTPUT ;
    USE SIGNAL ;
    SHAPE ABUTMENT ;
    PORT
      LAYER M3 ;
      RECT 28.287 34.506 28.305 34.560 ;
    END
  END rw0_rd_out[334]
  PIN rw0_rd_out[335]
    DIRECTION OUTPUT ;
    USE SIGNAL ;
    SHAPE ABUTMENT ;
    PORT
      LAYER M3 ;
      RECT 28.647 34.506 28.665 34.560 ;
    END
  END rw0_rd_out[335]
  PIN rw0_rd_out[336]
    DIRECTION OUTPUT ;
    USE SIGNAL ;
    SHAPE ABUTMENT ;
    PORT
      LAYER M3 ;
      RECT 29.007 34.506 29.025 34.560 ;
    END
  END rw0_rd_out[336]
  PIN rw0_rd_out[337]
    DIRECTION OUTPUT ;
    USE SIGNAL ;
    SHAPE ABUTMENT ;
    PORT
      LAYER M3 ;
      RECT 29.367 34.506 29.385 34.560 ;
    END
  END rw0_rd_out[337]
  PIN rw0_rd_out[338]
    DIRECTION OUTPUT ;
    USE SIGNAL ;
    SHAPE ABUTMENT ;
    PORT
      LAYER M3 ;
      RECT 29.727 34.506 29.745 34.560 ;
    END
  END rw0_rd_out[338]
  PIN rw0_rd_out[339]
    DIRECTION OUTPUT ;
    USE SIGNAL ;
    SHAPE ABUTMENT ;
    PORT
      LAYER M3 ;
      RECT 30.087 34.506 30.105 34.560 ;
    END
  END rw0_rd_out[339]
  PIN rw0_rd_out[340]
    DIRECTION OUTPUT ;
    USE SIGNAL ;
    SHAPE ABUTMENT ;
    PORT
      LAYER M3 ;
      RECT 30.447 34.506 30.465 34.560 ;
    END
  END rw0_rd_out[340]
  PIN rw0_rd_out[341]
    DIRECTION OUTPUT ;
    USE SIGNAL ;
    SHAPE ABUTMENT ;
    PORT
      LAYER M3 ;
      RECT 30.807 34.506 30.825 34.560 ;
    END
  END rw0_rd_out[341]
  PIN rw0_rd_out[342]
    DIRECTION OUTPUT ;
    USE SIGNAL ;
    SHAPE ABUTMENT ;
    PORT
      LAYER M3 ;
      RECT 31.167 34.506 31.185 34.560 ;
    END
  END rw0_rd_out[342]
  PIN rw0_rd_out[343]
    DIRECTION OUTPUT ;
    USE SIGNAL ;
    SHAPE ABUTMENT ;
    PORT
      LAYER M3 ;
      RECT 31.527 34.506 31.545 34.560 ;
    END
  END rw0_rd_out[343]
  PIN rw0_rd_out[344]
    DIRECTION OUTPUT ;
    USE SIGNAL ;
    SHAPE ABUTMENT ;
    PORT
      LAYER M3 ;
      RECT 31.887 34.506 31.905 34.560 ;
    END
  END rw0_rd_out[344]
  PIN rw0_rd_out[345]
    DIRECTION OUTPUT ;
    USE SIGNAL ;
    SHAPE ABUTMENT ;
    PORT
      LAYER M3 ;
      RECT 32.247 34.506 32.265 34.560 ;
    END
  END rw0_rd_out[345]
  PIN rw0_rd_out[346]
    DIRECTION OUTPUT ;
    USE SIGNAL ;
    SHAPE ABUTMENT ;
    PORT
      LAYER M3 ;
      RECT 32.607 34.506 32.625 34.560 ;
    END
  END rw0_rd_out[346]
  PIN rw0_rd_out[347]
    DIRECTION OUTPUT ;
    USE SIGNAL ;
    SHAPE ABUTMENT ;
    PORT
      LAYER M3 ;
      RECT 32.967 34.506 32.985 34.560 ;
    END
  END rw0_rd_out[347]
  PIN rw0_rd_out[348]
    DIRECTION OUTPUT ;
    USE SIGNAL ;
    SHAPE ABUTMENT ;
    PORT
      LAYER M3 ;
      RECT 33.327 34.506 33.345 34.560 ;
    END
  END rw0_rd_out[348]
  PIN rw0_rd_out[349]
    DIRECTION OUTPUT ;
    USE SIGNAL ;
    SHAPE ABUTMENT ;
    PORT
      LAYER M3 ;
      RECT 33.687 34.506 33.705 34.560 ;
    END
  END rw0_rd_out[349]
  PIN rw0_rd_out[350]
    DIRECTION OUTPUT ;
    USE SIGNAL ;
    SHAPE ABUTMENT ;
    PORT
      LAYER M3 ;
      RECT 34.047 34.506 34.065 34.560 ;
    END
  END rw0_rd_out[350]
  PIN rw0_rd_out[351]
    DIRECTION OUTPUT ;
    USE SIGNAL ;
    SHAPE ABUTMENT ;
    PORT
      LAYER M3 ;
      RECT 34.407 34.506 34.425 34.560 ;
    END
  END rw0_rd_out[351]
  PIN rw0_rd_out[352]
    DIRECTION OUTPUT ;
    USE SIGNAL ;
    SHAPE ABUTMENT ;
    PORT
      LAYER M3 ;
      RECT 34.767 34.506 34.785 34.560 ;
    END
  END rw0_rd_out[352]
  PIN rw0_rd_out[353]
    DIRECTION OUTPUT ;
    USE SIGNAL ;
    SHAPE ABUTMENT ;
    PORT
      LAYER M3 ;
      RECT 35.127 34.506 35.145 34.560 ;
    END
  END rw0_rd_out[353]
  PIN rw0_rd_out[354]
    DIRECTION OUTPUT ;
    USE SIGNAL ;
    SHAPE ABUTMENT ;
    PORT
      LAYER M3 ;
      RECT 35.487 34.506 35.505 34.560 ;
    END
  END rw0_rd_out[354]
  PIN rw0_rd_out[355]
    DIRECTION OUTPUT ;
    USE SIGNAL ;
    SHAPE ABUTMENT ;
    PORT
      LAYER M3 ;
      RECT 35.847 34.506 35.865 34.560 ;
    END
  END rw0_rd_out[355]
  PIN rw0_rd_out[356]
    DIRECTION OUTPUT ;
    USE SIGNAL ;
    SHAPE ABUTMENT ;
    PORT
      LAYER M3 ;
      RECT 36.207 34.506 36.225 34.560 ;
    END
  END rw0_rd_out[356]
  PIN rw0_rd_out[357]
    DIRECTION OUTPUT ;
    USE SIGNAL ;
    SHAPE ABUTMENT ;
    PORT
      LAYER M3 ;
      RECT 36.567 34.506 36.585 34.560 ;
    END
  END rw0_rd_out[357]
  PIN rw0_rd_out[358]
    DIRECTION OUTPUT ;
    USE SIGNAL ;
    SHAPE ABUTMENT ;
    PORT
      LAYER M3 ;
      RECT 36.927 34.506 36.945 34.560 ;
    END
  END rw0_rd_out[358]
  PIN rw0_rd_out[359]
    DIRECTION OUTPUT ;
    USE SIGNAL ;
    SHAPE ABUTMENT ;
    PORT
      LAYER M3 ;
      RECT 37.287 34.506 37.305 34.560 ;
    END
  END rw0_rd_out[359]
  PIN rw0_rd_out[360]
    DIRECTION OUTPUT ;
    USE SIGNAL ;
    SHAPE ABUTMENT ;
    PORT
      LAYER M3 ;
      RECT 37.647 34.506 37.665 34.560 ;
    END
  END rw0_rd_out[360]
  PIN rw0_rd_out[361]
    DIRECTION OUTPUT ;
    USE SIGNAL ;
    SHAPE ABUTMENT ;
    PORT
      LAYER M3 ;
      RECT 38.007 34.506 38.025 34.560 ;
    END
  END rw0_rd_out[361]
  PIN rw0_rd_out[362]
    DIRECTION OUTPUT ;
    USE SIGNAL ;
    SHAPE ABUTMENT ;
    PORT
      LAYER M3 ;
      RECT 38.367 34.506 38.385 34.560 ;
    END
  END rw0_rd_out[362]
  PIN rw0_rd_out[363]
    DIRECTION OUTPUT ;
    USE SIGNAL ;
    SHAPE ABUTMENT ;
    PORT
      LAYER M3 ;
      RECT 38.727 34.506 38.745 34.560 ;
    END
  END rw0_rd_out[363]
  PIN rw0_rd_out[364]
    DIRECTION OUTPUT ;
    USE SIGNAL ;
    SHAPE ABUTMENT ;
    PORT
      LAYER M3 ;
      RECT 39.087 34.506 39.105 34.560 ;
    END
  END rw0_rd_out[364]
  PIN rw0_rd_out[365]
    DIRECTION OUTPUT ;
    USE SIGNAL ;
    SHAPE ABUTMENT ;
    PORT
      LAYER M3 ;
      RECT 39.447 34.506 39.465 34.560 ;
    END
  END rw0_rd_out[365]
  PIN rw0_rd_out[366]
    DIRECTION OUTPUT ;
    USE SIGNAL ;
    SHAPE ABUTMENT ;
    PORT
      LAYER M3 ;
      RECT 39.807 34.506 39.825 34.560 ;
    END
  END rw0_rd_out[366]
  PIN rw0_rd_out[367]
    DIRECTION OUTPUT ;
    USE SIGNAL ;
    SHAPE ABUTMENT ;
    PORT
      LAYER M3 ;
      RECT 40.167 34.506 40.185 34.560 ;
    END
  END rw0_rd_out[367]
  PIN rw0_rd_out[368]
    DIRECTION OUTPUT ;
    USE SIGNAL ;
    SHAPE ABUTMENT ;
    PORT
      LAYER M3 ;
      RECT 40.527 34.506 40.545 34.560 ;
    END
  END rw0_rd_out[368]
  PIN rw0_rd_out[369]
    DIRECTION OUTPUT ;
    USE SIGNAL ;
    SHAPE ABUTMENT ;
    PORT
      LAYER M3 ;
      RECT 40.887 34.506 40.905 34.560 ;
    END
  END rw0_rd_out[369]
  PIN rw0_rd_out[370]
    DIRECTION OUTPUT ;
    USE SIGNAL ;
    SHAPE ABUTMENT ;
    PORT
      LAYER M3 ;
      RECT 41.247 34.506 41.265 34.560 ;
    END
  END rw0_rd_out[370]
  PIN rw0_rd_out[371]
    DIRECTION OUTPUT ;
    USE SIGNAL ;
    SHAPE ABUTMENT ;
    PORT
      LAYER M3 ;
      RECT 41.607 34.506 41.625 34.560 ;
    END
  END rw0_rd_out[371]
  PIN rw0_rd_out[372]
    DIRECTION OUTPUT ;
    USE SIGNAL ;
    SHAPE ABUTMENT ;
    PORT
      LAYER M3 ;
      RECT 41.967 34.506 41.985 34.560 ;
    END
  END rw0_rd_out[372]
  PIN rw0_rd_out[373]
    DIRECTION OUTPUT ;
    USE SIGNAL ;
    SHAPE ABUTMENT ;
    PORT
      LAYER M3 ;
      RECT 42.327 34.506 42.345 34.560 ;
    END
  END rw0_rd_out[373]
  PIN rw0_rd_out[374]
    DIRECTION OUTPUT ;
    USE SIGNAL ;
    SHAPE ABUTMENT ;
    PORT
      LAYER M3 ;
      RECT 42.687 34.506 42.705 34.560 ;
    END
  END rw0_rd_out[374]
  PIN rw0_rd_out[375]
    DIRECTION OUTPUT ;
    USE SIGNAL ;
    SHAPE ABUTMENT ;
    PORT
      LAYER M3 ;
      RECT 43.047 34.506 43.065 34.560 ;
    END
  END rw0_rd_out[375]
  PIN rw0_rd_out[376]
    DIRECTION OUTPUT ;
    USE SIGNAL ;
    SHAPE ABUTMENT ;
    PORT
      LAYER M3 ;
      RECT 43.407 34.506 43.425 34.560 ;
    END
  END rw0_rd_out[376]
  PIN rw0_rd_out[377]
    DIRECTION OUTPUT ;
    USE SIGNAL ;
    SHAPE ABUTMENT ;
    PORT
      LAYER M3 ;
      RECT 43.767 34.506 43.785 34.560 ;
    END
  END rw0_rd_out[377]
  PIN rw0_rd_out[378]
    DIRECTION OUTPUT ;
    USE SIGNAL ;
    SHAPE ABUTMENT ;
    PORT
      LAYER M3 ;
      RECT 44.127 34.506 44.145 34.560 ;
    END
  END rw0_rd_out[378]
  PIN rw0_rd_out[379]
    DIRECTION OUTPUT ;
    USE SIGNAL ;
    SHAPE ABUTMENT ;
    PORT
      LAYER M3 ;
      RECT 44.487 34.506 44.505 34.560 ;
    END
  END rw0_rd_out[379]
  PIN rw0_rd_out[380]
    DIRECTION OUTPUT ;
    USE SIGNAL ;
    SHAPE ABUTMENT ;
    PORT
      LAYER M3 ;
      RECT 44.847 34.506 44.865 34.560 ;
    END
  END rw0_rd_out[380]
  PIN rw0_rd_out[381]
    DIRECTION OUTPUT ;
    USE SIGNAL ;
    SHAPE ABUTMENT ;
    PORT
      LAYER M3 ;
      RECT 45.207 34.506 45.225 34.560 ;
    END
  END rw0_rd_out[381]
  PIN rw0_rd_out[382]
    DIRECTION OUTPUT ;
    USE SIGNAL ;
    SHAPE ABUTMENT ;
    PORT
      LAYER M3 ;
      RECT 45.567 34.506 45.585 34.560 ;
    END
  END rw0_rd_out[382]
  PIN rw0_rd_out[383]
    DIRECTION OUTPUT ;
    USE SIGNAL ;
    SHAPE ABUTMENT ;
    PORT
      LAYER M3 ;
      RECT 45.927 34.506 45.945 34.560 ;
    END
  END rw0_rd_out[383]
  PIN rw0_rd_out[384]
    DIRECTION OUTPUT ;
    USE SIGNAL ;
    SHAPE ABUTMENT ;
    PORT
      LAYER M3 ;
      RECT 46.287 34.506 46.305 34.560 ;
    END
  END rw0_rd_out[384]
  PIN rw0_rd_out[385]
    DIRECTION OUTPUT ;
    USE SIGNAL ;
    SHAPE ABUTMENT ;
    PORT
      LAYER M3 ;
      RECT 46.647 34.506 46.665 34.560 ;
    END
  END rw0_rd_out[385]
  PIN rw0_rd_out[386]
    DIRECTION OUTPUT ;
    USE SIGNAL ;
    SHAPE ABUTMENT ;
    PORT
      LAYER M3 ;
      RECT 47.007 34.506 47.025 34.560 ;
    END
  END rw0_rd_out[386]
  PIN rw0_rd_out[387]
    DIRECTION OUTPUT ;
    USE SIGNAL ;
    SHAPE ABUTMENT ;
    PORT
      LAYER M3 ;
      RECT 47.367 34.506 47.385 34.560 ;
    END
  END rw0_rd_out[387]
  PIN rw0_rd_out[388]
    DIRECTION OUTPUT ;
    USE SIGNAL ;
    SHAPE ABUTMENT ;
    PORT
      LAYER M3 ;
      RECT 47.727 34.506 47.745 34.560 ;
    END
  END rw0_rd_out[388]
  PIN rw0_rd_out[389]
    DIRECTION OUTPUT ;
    USE SIGNAL ;
    SHAPE ABUTMENT ;
    PORT
      LAYER M3 ;
      RECT 48.087 34.506 48.105 34.560 ;
    END
  END rw0_rd_out[389]
  PIN rw0_rd_out[390]
    DIRECTION OUTPUT ;
    USE SIGNAL ;
    SHAPE ABUTMENT ;
    PORT
      LAYER M3 ;
      RECT 48.447 34.506 48.465 34.560 ;
    END
  END rw0_rd_out[390]
  PIN rw0_rd_out[391]
    DIRECTION OUTPUT ;
    USE SIGNAL ;
    SHAPE ABUTMENT ;
    PORT
      LAYER M3 ;
      RECT 48.807 34.506 48.825 34.560 ;
    END
  END rw0_rd_out[391]
  PIN rw0_rd_out[392]
    DIRECTION OUTPUT ;
    USE SIGNAL ;
    SHAPE ABUTMENT ;
    PORT
      LAYER M3 ;
      RECT 49.167 34.506 49.185 34.560 ;
    END
  END rw0_rd_out[392]
  PIN rw0_rd_out[393]
    DIRECTION OUTPUT ;
    USE SIGNAL ;
    SHAPE ABUTMENT ;
    PORT
      LAYER M3 ;
      RECT 49.527 34.506 49.545 34.560 ;
    END
  END rw0_rd_out[393]
  PIN rw0_rd_out[394]
    DIRECTION OUTPUT ;
    USE SIGNAL ;
    SHAPE ABUTMENT ;
    PORT
      LAYER M3 ;
      RECT 49.887 34.506 49.905 34.560 ;
    END
  END rw0_rd_out[394]
  PIN rw0_rd_out[395]
    DIRECTION OUTPUT ;
    USE SIGNAL ;
    SHAPE ABUTMENT ;
    PORT
      LAYER M3 ;
      RECT 50.247 34.506 50.265 34.560 ;
    END
  END rw0_rd_out[395]
  PIN rw0_rd_out[396]
    DIRECTION OUTPUT ;
    USE SIGNAL ;
    SHAPE ABUTMENT ;
    PORT
      LAYER M3 ;
      RECT 50.607 34.506 50.625 34.560 ;
    END
  END rw0_rd_out[396]
  PIN rw0_rd_out[397]
    DIRECTION OUTPUT ;
    USE SIGNAL ;
    SHAPE ABUTMENT ;
    PORT
      LAYER M3 ;
      RECT 50.967 34.506 50.985 34.560 ;
    END
  END rw0_rd_out[397]
  PIN rw0_rd_out[398]
    DIRECTION OUTPUT ;
    USE SIGNAL ;
    SHAPE ABUTMENT ;
    PORT
      LAYER M3 ;
      RECT 51.327 34.506 51.345 34.560 ;
    END
  END rw0_rd_out[398]
  PIN rw0_rd_out[399]
    DIRECTION OUTPUT ;
    USE SIGNAL ;
    SHAPE ABUTMENT ;
    PORT
      LAYER M3 ;
      RECT 51.687 34.506 51.705 34.560 ;
    END
  END rw0_rd_out[399]
  PIN rw0_rd_out[400]
    DIRECTION OUTPUT ;
    USE SIGNAL ;
    SHAPE ABUTMENT ;
    PORT
      LAYER M3 ;
      RECT 52.047 34.506 52.065 34.560 ;
    END
  END rw0_rd_out[400]
  PIN rw0_rd_out[401]
    DIRECTION OUTPUT ;
    USE SIGNAL ;
    SHAPE ABUTMENT ;
    PORT
      LAYER M3 ;
      RECT 52.407 34.506 52.425 34.560 ;
    END
  END rw0_rd_out[401]
  PIN rw0_rd_out[402]
    DIRECTION OUTPUT ;
    USE SIGNAL ;
    SHAPE ABUTMENT ;
    PORT
      LAYER M3 ;
      RECT 52.767 34.506 52.785 34.560 ;
    END
  END rw0_rd_out[402]
  PIN rw0_rd_out[403]
    DIRECTION OUTPUT ;
    USE SIGNAL ;
    SHAPE ABUTMENT ;
    PORT
      LAYER M3 ;
      RECT 53.127 34.506 53.145 34.560 ;
    END
  END rw0_rd_out[403]
  PIN rw0_rd_out[404]
    DIRECTION OUTPUT ;
    USE SIGNAL ;
    SHAPE ABUTMENT ;
    PORT
      LAYER M3 ;
      RECT 53.487 34.506 53.505 34.560 ;
    END
  END rw0_rd_out[404]
  PIN rw0_rd_out[405]
    DIRECTION OUTPUT ;
    USE SIGNAL ;
    SHAPE ABUTMENT ;
    PORT
      LAYER M3 ;
      RECT 53.847 34.506 53.865 34.560 ;
    END
  END rw0_rd_out[405]
  PIN rw0_rd_out[406]
    DIRECTION OUTPUT ;
    USE SIGNAL ;
    SHAPE ABUTMENT ;
    PORT
      LAYER M3 ;
      RECT 54.207 34.506 54.225 34.560 ;
    END
  END rw0_rd_out[406]
  PIN rw0_rd_out[407]
    DIRECTION OUTPUT ;
    USE SIGNAL ;
    SHAPE ABUTMENT ;
    PORT
      LAYER M3 ;
      RECT 54.567 34.506 54.585 34.560 ;
    END
  END rw0_rd_out[407]
  PIN rw0_rd_out[408]
    DIRECTION OUTPUT ;
    USE SIGNAL ;
    SHAPE ABUTMENT ;
    PORT
      LAYER M3 ;
      RECT 54.927 34.506 54.945 34.560 ;
    END
  END rw0_rd_out[408]
  PIN rw0_rd_out[409]
    DIRECTION OUTPUT ;
    USE SIGNAL ;
    SHAPE ABUTMENT ;
    PORT
      LAYER M3 ;
      RECT 55.287 34.506 55.305 34.560 ;
    END
  END rw0_rd_out[409]
  PIN rw0_rd_out[410]
    DIRECTION OUTPUT ;
    USE SIGNAL ;
    SHAPE ABUTMENT ;
    PORT
      LAYER M3 ;
      RECT 55.647 34.506 55.665 34.560 ;
    END
  END rw0_rd_out[410]
  PIN rw0_rd_out[411]
    DIRECTION OUTPUT ;
    USE SIGNAL ;
    SHAPE ABUTMENT ;
    PORT
      LAYER M3 ;
      RECT 56.007 34.506 56.025 34.560 ;
    END
  END rw0_rd_out[411]
  PIN rw0_rd_out[412]
    DIRECTION OUTPUT ;
    USE SIGNAL ;
    SHAPE ABUTMENT ;
    PORT
      LAYER M3 ;
      RECT 56.367 34.506 56.385 34.560 ;
    END
  END rw0_rd_out[412]
  PIN rw0_rd_out[413]
    DIRECTION OUTPUT ;
    USE SIGNAL ;
    SHAPE ABUTMENT ;
    PORT
      LAYER M3 ;
      RECT 56.727 34.506 56.745 34.560 ;
    END
  END rw0_rd_out[413]
  PIN rw0_rd_out[414]
    DIRECTION OUTPUT ;
    USE SIGNAL ;
    SHAPE ABUTMENT ;
    PORT
      LAYER M3 ;
      RECT 57.087 34.506 57.105 34.560 ;
    END
  END rw0_rd_out[414]
  PIN rw0_rd_out[415]
    DIRECTION OUTPUT ;
    USE SIGNAL ;
    SHAPE ABUTMENT ;
    PORT
      LAYER M3 ;
      RECT 57.447 34.506 57.465 34.560 ;
    END
  END rw0_rd_out[415]
  PIN rw0_rd_out[416]
    DIRECTION OUTPUT ;
    USE SIGNAL ;
    SHAPE ABUTMENT ;
    PORT
      LAYER M3 ;
      RECT 57.807 34.506 57.825 34.560 ;
    END
  END rw0_rd_out[416]
  PIN rw0_rd_out[417]
    DIRECTION OUTPUT ;
    USE SIGNAL ;
    SHAPE ABUTMENT ;
    PORT
      LAYER M3 ;
      RECT 58.167 34.506 58.185 34.560 ;
    END
  END rw0_rd_out[417]
  PIN rw0_rd_out[418]
    DIRECTION OUTPUT ;
    USE SIGNAL ;
    SHAPE ABUTMENT ;
    PORT
      LAYER M3 ;
      RECT 58.527 34.506 58.545 34.560 ;
    END
  END rw0_rd_out[418]
  PIN rw0_rd_out[419]
    DIRECTION OUTPUT ;
    USE SIGNAL ;
    SHAPE ABUTMENT ;
    PORT
      LAYER M3 ;
      RECT 58.887 34.506 58.905 34.560 ;
    END
  END rw0_rd_out[419]
  PIN rw0_rd_out[420]
    DIRECTION OUTPUT ;
    USE SIGNAL ;
    SHAPE ABUTMENT ;
    PORT
      LAYER M3 ;
      RECT 59.247 34.506 59.265 34.560 ;
    END
  END rw0_rd_out[420]
  PIN rw0_rd_out[421]
    DIRECTION OUTPUT ;
    USE SIGNAL ;
    SHAPE ABUTMENT ;
    PORT
      LAYER M3 ;
      RECT 59.607 34.506 59.625 34.560 ;
    END
  END rw0_rd_out[421]
  PIN rw0_rd_out[422]
    DIRECTION OUTPUT ;
    USE SIGNAL ;
    SHAPE ABUTMENT ;
    PORT
      LAYER M3 ;
      RECT 59.967 34.506 59.985 34.560 ;
    END
  END rw0_rd_out[422]
  PIN rw0_rd_out[423]
    DIRECTION OUTPUT ;
    USE SIGNAL ;
    SHAPE ABUTMENT ;
    PORT
      LAYER M3 ;
      RECT 60.327 34.506 60.345 34.560 ;
    END
  END rw0_rd_out[423]
  PIN rw0_rd_out[424]
    DIRECTION OUTPUT ;
    USE SIGNAL ;
    SHAPE ABUTMENT ;
    PORT
      LAYER M3 ;
      RECT 60.687 34.506 60.705 34.560 ;
    END
  END rw0_rd_out[424]
  PIN rw0_rd_out[425]
    DIRECTION OUTPUT ;
    USE SIGNAL ;
    SHAPE ABUTMENT ;
    PORT
      LAYER M3 ;
      RECT 61.047 34.506 61.065 34.560 ;
    END
  END rw0_rd_out[425]
  PIN rw0_rd_out[426]
    DIRECTION OUTPUT ;
    USE SIGNAL ;
    SHAPE ABUTMENT ;
    PORT
      LAYER M3 ;
      RECT 61.407 34.506 61.425 34.560 ;
    END
  END rw0_rd_out[426]
  PIN rw0_rd_out[427]
    DIRECTION OUTPUT ;
    USE SIGNAL ;
    SHAPE ABUTMENT ;
    PORT
      LAYER M3 ;
      RECT 61.767 34.506 61.785 34.560 ;
    END
  END rw0_rd_out[427]
  PIN rw0_rd_out[428]
    DIRECTION OUTPUT ;
    USE SIGNAL ;
    SHAPE ABUTMENT ;
    PORT
      LAYER M3 ;
      RECT 62.127 34.506 62.145 34.560 ;
    END
  END rw0_rd_out[428]
  PIN rw0_rd_out[429]
    DIRECTION OUTPUT ;
    USE SIGNAL ;
    SHAPE ABUTMENT ;
    PORT
      LAYER M3 ;
      RECT 62.487 34.506 62.505 34.560 ;
    END
  END rw0_rd_out[429]
  PIN rw0_rd_out[430]
    DIRECTION OUTPUT ;
    USE SIGNAL ;
    SHAPE ABUTMENT ;
    PORT
      LAYER M3 ;
      RECT 62.847 34.506 62.865 34.560 ;
    END
  END rw0_rd_out[430]
  PIN rw0_rd_out[431]
    DIRECTION OUTPUT ;
    USE SIGNAL ;
    SHAPE ABUTMENT ;
    PORT
      LAYER M3 ;
      RECT 63.207 34.506 63.225 34.560 ;
    END
  END rw0_rd_out[431]
  PIN rw0_rd_out[432]
    DIRECTION OUTPUT ;
    USE SIGNAL ;
    SHAPE ABUTMENT ;
    PORT
      LAYER M3 ;
      RECT 63.567 34.506 63.585 34.560 ;
    END
  END rw0_rd_out[432]
  PIN rw0_rd_out[433]
    DIRECTION OUTPUT ;
    USE SIGNAL ;
    SHAPE ABUTMENT ;
    PORT
      LAYER M3 ;
      RECT 63.927 34.506 63.945 34.560 ;
    END
  END rw0_rd_out[433]
  PIN rw0_rd_out[434]
    DIRECTION OUTPUT ;
    USE SIGNAL ;
    SHAPE ABUTMENT ;
    PORT
      LAYER M3 ;
      RECT 64.287 34.506 64.305 34.560 ;
    END
  END rw0_rd_out[434]
  PIN rw0_rd_out[435]
    DIRECTION OUTPUT ;
    USE SIGNAL ;
    SHAPE ABUTMENT ;
    PORT
      LAYER M3 ;
      RECT 64.647 34.506 64.665 34.560 ;
    END
  END rw0_rd_out[435]
  PIN rw0_rd_out[436]
    DIRECTION OUTPUT ;
    USE SIGNAL ;
    SHAPE ABUTMENT ;
    PORT
      LAYER M3 ;
      RECT 65.007 34.506 65.025 34.560 ;
    END
  END rw0_rd_out[436]
  PIN rw0_rd_out[437]
    DIRECTION OUTPUT ;
    USE SIGNAL ;
    SHAPE ABUTMENT ;
    PORT
      LAYER M3 ;
      RECT 65.367 34.506 65.385 34.560 ;
    END
  END rw0_rd_out[437]
  PIN rw0_rd_out[438]
    DIRECTION OUTPUT ;
    USE SIGNAL ;
    SHAPE ABUTMENT ;
    PORT
      LAYER M3 ;
      RECT 65.727 34.506 65.745 34.560 ;
    END
  END rw0_rd_out[438]
  PIN rw0_rd_out[439]
    DIRECTION OUTPUT ;
    USE SIGNAL ;
    SHAPE ABUTMENT ;
    PORT
      LAYER M3 ;
      RECT 66.087 34.506 66.105 34.560 ;
    END
  END rw0_rd_out[439]
  PIN rw0_rd_out[440]
    DIRECTION OUTPUT ;
    USE SIGNAL ;
    SHAPE ABUTMENT ;
    PORT
      LAYER M3 ;
      RECT 66.447 34.506 66.465 34.560 ;
    END
  END rw0_rd_out[440]
  PIN rw0_rd_out[441]
    DIRECTION OUTPUT ;
    USE SIGNAL ;
    SHAPE ABUTMENT ;
    PORT
      LAYER M3 ;
      RECT 66.807 34.506 66.825 34.560 ;
    END
  END rw0_rd_out[441]
  PIN rw0_rd_out[442]
    DIRECTION OUTPUT ;
    USE SIGNAL ;
    SHAPE ABUTMENT ;
    PORT
      LAYER M3 ;
      RECT 67.167 34.506 67.185 34.560 ;
    END
  END rw0_rd_out[442]
  PIN rw0_rd_out[443]
    DIRECTION OUTPUT ;
    USE SIGNAL ;
    SHAPE ABUTMENT ;
    PORT
      LAYER M3 ;
      RECT 67.527 34.506 67.545 34.560 ;
    END
  END rw0_rd_out[443]
  PIN rw0_rd_out[444]
    DIRECTION OUTPUT ;
    USE SIGNAL ;
    SHAPE ABUTMENT ;
    PORT
      LAYER M3 ;
      RECT 67.887 34.506 67.905 34.560 ;
    END
  END rw0_rd_out[444]
  PIN rw0_rd_out[445]
    DIRECTION OUTPUT ;
    USE SIGNAL ;
    SHAPE ABUTMENT ;
    PORT
      LAYER M3 ;
      RECT 68.247 34.506 68.265 34.560 ;
    END
  END rw0_rd_out[445]
  PIN rw0_rd_out[446]
    DIRECTION OUTPUT ;
    USE SIGNAL ;
    SHAPE ABUTMENT ;
    PORT
      LAYER M3 ;
      RECT 68.607 34.506 68.625 34.560 ;
    END
  END rw0_rd_out[446]
  PIN rw0_rd_out[447]
    DIRECTION OUTPUT ;
    USE SIGNAL ;
    SHAPE ABUTMENT ;
    PORT
      LAYER M3 ;
      RECT 68.967 34.506 68.985 34.560 ;
    END
  END rw0_rd_out[447]
  PIN rw0_rd_out[448]
    DIRECTION OUTPUT ;
    USE SIGNAL ;
    SHAPE ABUTMENT ;
    PORT
      LAYER M3 ;
      RECT 69.327 34.506 69.345 34.560 ;
    END
  END rw0_rd_out[448]
  PIN rw0_rd_out[449]
    DIRECTION OUTPUT ;
    USE SIGNAL ;
    SHAPE ABUTMENT ;
    PORT
      LAYER M3 ;
      RECT 69.687 34.506 69.705 34.560 ;
    END
  END rw0_rd_out[449]
  PIN rw0_rd_out[450]
    DIRECTION OUTPUT ;
    USE SIGNAL ;
    SHAPE ABUTMENT ;
    PORT
      LAYER M3 ;
      RECT 70.047 34.506 70.065 34.560 ;
    END
  END rw0_rd_out[450]
  PIN rw0_rd_out[451]
    DIRECTION OUTPUT ;
    USE SIGNAL ;
    SHAPE ABUTMENT ;
    PORT
      LAYER M3 ;
      RECT 70.407 34.506 70.425 34.560 ;
    END
  END rw0_rd_out[451]
  PIN rw0_rd_out[452]
    DIRECTION OUTPUT ;
    USE SIGNAL ;
    SHAPE ABUTMENT ;
    PORT
      LAYER M3 ;
      RECT 70.767 34.506 70.785 34.560 ;
    END
  END rw0_rd_out[452]
  PIN rw0_rd_out[453]
    DIRECTION OUTPUT ;
    USE SIGNAL ;
    SHAPE ABUTMENT ;
    PORT
      LAYER M3 ;
      RECT 71.127 34.506 71.145 34.560 ;
    END
  END rw0_rd_out[453]
  PIN rw0_rd_out[454]
    DIRECTION OUTPUT ;
    USE SIGNAL ;
    SHAPE ABUTMENT ;
    PORT
      LAYER M3 ;
      RECT 71.487 34.506 71.505 34.560 ;
    END
  END rw0_rd_out[454]
  PIN rw0_rd_out[455]
    DIRECTION OUTPUT ;
    USE SIGNAL ;
    SHAPE ABUTMENT ;
    PORT
      LAYER M3 ;
      RECT 71.847 34.506 71.865 34.560 ;
    END
  END rw0_rd_out[455]
  PIN rw0_rd_out[456]
    DIRECTION OUTPUT ;
    USE SIGNAL ;
    SHAPE ABUTMENT ;
    PORT
      LAYER M3 ;
      RECT 72.207 34.506 72.225 34.560 ;
    END
  END rw0_rd_out[456]
  PIN rw0_rd_out[457]
    DIRECTION OUTPUT ;
    USE SIGNAL ;
    SHAPE ABUTMENT ;
    PORT
      LAYER M3 ;
      RECT 72.567 34.506 72.585 34.560 ;
    END
  END rw0_rd_out[457]
  PIN rw0_rd_out[458]
    DIRECTION OUTPUT ;
    USE SIGNAL ;
    SHAPE ABUTMENT ;
    PORT
      LAYER M3 ;
      RECT 72.927 34.506 72.945 34.560 ;
    END
  END rw0_rd_out[458]
  PIN rw0_rd_out[459]
    DIRECTION OUTPUT ;
    USE SIGNAL ;
    SHAPE ABUTMENT ;
    PORT
      LAYER M3 ;
      RECT 73.287 34.506 73.305 34.560 ;
    END
  END rw0_rd_out[459]
  PIN rw0_rd_out[460]
    DIRECTION OUTPUT ;
    USE SIGNAL ;
    SHAPE ABUTMENT ;
    PORT
      LAYER M3 ;
      RECT 73.647 34.506 73.665 34.560 ;
    END
  END rw0_rd_out[460]
  PIN rw0_rd_out[461]
    DIRECTION OUTPUT ;
    USE SIGNAL ;
    SHAPE ABUTMENT ;
    PORT
      LAYER M3 ;
      RECT 74.007 34.506 74.025 34.560 ;
    END
  END rw0_rd_out[461]
  PIN rw0_rd_out[462]
    DIRECTION OUTPUT ;
    USE SIGNAL ;
    SHAPE ABUTMENT ;
    PORT
      LAYER M3 ;
      RECT 74.367 34.506 74.385 34.560 ;
    END
  END rw0_rd_out[462]
  PIN rw0_rd_out[463]
    DIRECTION OUTPUT ;
    USE SIGNAL ;
    SHAPE ABUTMENT ;
    PORT
      LAYER M3 ;
      RECT 74.727 34.506 74.745 34.560 ;
    END
  END rw0_rd_out[463]
  PIN rw0_rd_out[464]
    DIRECTION OUTPUT ;
    USE SIGNAL ;
    SHAPE ABUTMENT ;
    PORT
      LAYER M3 ;
      RECT 75.087 34.506 75.105 34.560 ;
    END
  END rw0_rd_out[464]
  PIN rw0_rd_out[465]
    DIRECTION OUTPUT ;
    USE SIGNAL ;
    SHAPE ABUTMENT ;
    PORT
      LAYER M3 ;
      RECT 75.447 34.506 75.465 34.560 ;
    END
  END rw0_rd_out[465]
  PIN rw0_rd_out[466]
    DIRECTION OUTPUT ;
    USE SIGNAL ;
    SHAPE ABUTMENT ;
    PORT
      LAYER M3 ;
      RECT 75.807 34.506 75.825 34.560 ;
    END
  END rw0_rd_out[466]
  PIN rw0_rd_out[467]
    DIRECTION OUTPUT ;
    USE SIGNAL ;
    SHAPE ABUTMENT ;
    PORT
      LAYER M3 ;
      RECT 76.167 34.506 76.185 34.560 ;
    END
  END rw0_rd_out[467]
  PIN rw0_rd_out[468]
    DIRECTION OUTPUT ;
    USE SIGNAL ;
    SHAPE ABUTMENT ;
    PORT
      LAYER M3 ;
      RECT 76.527 34.506 76.545 34.560 ;
    END
  END rw0_rd_out[468]
  PIN rw0_rd_out[469]
    DIRECTION OUTPUT ;
    USE SIGNAL ;
    SHAPE ABUTMENT ;
    PORT
      LAYER M3 ;
      RECT 76.887 34.506 76.905 34.560 ;
    END
  END rw0_rd_out[469]
  PIN rw0_rd_out[470]
    DIRECTION OUTPUT ;
    USE SIGNAL ;
    SHAPE ABUTMENT ;
    PORT
      LAYER M3 ;
      RECT 77.247 34.506 77.265 34.560 ;
    END
  END rw0_rd_out[470]
  PIN rw0_rd_out[471]
    DIRECTION OUTPUT ;
    USE SIGNAL ;
    SHAPE ABUTMENT ;
    PORT
      LAYER M3 ;
      RECT 77.607 34.506 77.625 34.560 ;
    END
  END rw0_rd_out[471]
  PIN rw0_rd_out[472]
    DIRECTION OUTPUT ;
    USE SIGNAL ;
    SHAPE ABUTMENT ;
    PORT
      LAYER M3 ;
      RECT 77.967 34.506 77.985 34.560 ;
    END
  END rw0_rd_out[472]
  PIN rw0_rd_out[473]
    DIRECTION OUTPUT ;
    USE SIGNAL ;
    SHAPE ABUTMENT ;
    PORT
      LAYER M3 ;
      RECT 78.327 34.506 78.345 34.560 ;
    END
  END rw0_rd_out[473]
  PIN rw0_rd_out[474]
    DIRECTION OUTPUT ;
    USE SIGNAL ;
    SHAPE ABUTMENT ;
    PORT
      LAYER M3 ;
      RECT 78.687 34.506 78.705 34.560 ;
    END
  END rw0_rd_out[474]
  PIN rw0_rd_out[475]
    DIRECTION OUTPUT ;
    USE SIGNAL ;
    SHAPE ABUTMENT ;
    PORT
      LAYER M3 ;
      RECT 79.047 34.506 79.065 34.560 ;
    END
  END rw0_rd_out[475]
  PIN rw0_rd_out[476]
    DIRECTION OUTPUT ;
    USE SIGNAL ;
    SHAPE ABUTMENT ;
    PORT
      LAYER M3 ;
      RECT 79.407 34.506 79.425 34.560 ;
    END
  END rw0_rd_out[476]
  PIN rw0_rd_out[477]
    DIRECTION OUTPUT ;
    USE SIGNAL ;
    SHAPE ABUTMENT ;
    PORT
      LAYER M3 ;
      RECT 79.767 34.506 79.785 34.560 ;
    END
  END rw0_rd_out[477]
  PIN rw0_rd_out[478]
    DIRECTION OUTPUT ;
    USE SIGNAL ;
    SHAPE ABUTMENT ;
    PORT
      LAYER M3 ;
      RECT 80.127 34.506 80.145 34.560 ;
    END
  END rw0_rd_out[478]
  PIN rw0_rd_out[479]
    DIRECTION OUTPUT ;
    USE SIGNAL ;
    SHAPE ABUTMENT ;
    PORT
      LAYER M3 ;
      RECT 80.487 34.506 80.505 34.560 ;
    END
  END rw0_rd_out[479]
  PIN rw0_rd_out[480]
    DIRECTION OUTPUT ;
    USE SIGNAL ;
    SHAPE ABUTMENT ;
    PORT
      LAYER M3 ;
      RECT 80.847 34.506 80.865 34.560 ;
    END
  END rw0_rd_out[480]
  PIN rw0_rd_out[481]
    DIRECTION OUTPUT ;
    USE SIGNAL ;
    SHAPE ABUTMENT ;
    PORT
      LAYER M3 ;
      RECT 81.207 34.506 81.225 34.560 ;
    END
  END rw0_rd_out[481]
  PIN rw0_rd_out[482]
    DIRECTION OUTPUT ;
    USE SIGNAL ;
    SHAPE ABUTMENT ;
    PORT
      LAYER M3 ;
      RECT 81.567 34.506 81.585 34.560 ;
    END
  END rw0_rd_out[482]
  PIN rw0_rd_out[483]
    DIRECTION OUTPUT ;
    USE SIGNAL ;
    SHAPE ABUTMENT ;
    PORT
      LAYER M3 ;
      RECT 81.927 34.506 81.945 34.560 ;
    END
  END rw0_rd_out[483]
  PIN rw0_rd_out[484]
    DIRECTION OUTPUT ;
    USE SIGNAL ;
    SHAPE ABUTMENT ;
    PORT
      LAYER M3 ;
      RECT 82.287 34.506 82.305 34.560 ;
    END
  END rw0_rd_out[484]
  PIN rw0_rd_out[485]
    DIRECTION OUTPUT ;
    USE SIGNAL ;
    SHAPE ABUTMENT ;
    PORT
      LAYER M3 ;
      RECT 82.647 34.506 82.665 34.560 ;
    END
  END rw0_rd_out[485]
  PIN rw0_rd_out[486]
    DIRECTION OUTPUT ;
    USE SIGNAL ;
    SHAPE ABUTMENT ;
    PORT
      LAYER M3 ;
      RECT 83.007 34.506 83.025 34.560 ;
    END
  END rw0_rd_out[486]
  PIN rw0_rd_out[487]
    DIRECTION OUTPUT ;
    USE SIGNAL ;
    SHAPE ABUTMENT ;
    PORT
      LAYER M3 ;
      RECT 83.367 34.506 83.385 34.560 ;
    END
  END rw0_rd_out[487]
  PIN rw0_rd_out[488]
    DIRECTION OUTPUT ;
    USE SIGNAL ;
    SHAPE ABUTMENT ;
    PORT
      LAYER M3 ;
      RECT 83.727 34.506 83.745 34.560 ;
    END
  END rw0_rd_out[488]
  PIN rw0_rd_out[489]
    DIRECTION OUTPUT ;
    USE SIGNAL ;
    SHAPE ABUTMENT ;
    PORT
      LAYER M3 ;
      RECT 84.087 34.506 84.105 34.560 ;
    END
  END rw0_rd_out[489]
  PIN rw0_rd_out[490]
    DIRECTION OUTPUT ;
    USE SIGNAL ;
    SHAPE ABUTMENT ;
    PORT
      LAYER M3 ;
      RECT 84.447 34.506 84.465 34.560 ;
    END
  END rw0_rd_out[490]
  PIN rw0_rd_out[491]
    DIRECTION OUTPUT ;
    USE SIGNAL ;
    SHAPE ABUTMENT ;
    PORT
      LAYER M3 ;
      RECT 84.807 34.506 84.825 34.560 ;
    END
  END rw0_rd_out[491]
  PIN rw0_rd_out[492]
    DIRECTION OUTPUT ;
    USE SIGNAL ;
    SHAPE ABUTMENT ;
    PORT
      LAYER M3 ;
      RECT 85.167 34.506 85.185 34.560 ;
    END
  END rw0_rd_out[492]
  PIN rw0_rd_out[493]
    DIRECTION OUTPUT ;
    USE SIGNAL ;
    SHAPE ABUTMENT ;
    PORT
      LAYER M3 ;
      RECT 85.527 34.506 85.545 34.560 ;
    END
  END rw0_rd_out[493]
  PIN rw0_rd_out[494]
    DIRECTION OUTPUT ;
    USE SIGNAL ;
    SHAPE ABUTMENT ;
    PORT
      LAYER M3 ;
      RECT 85.887 34.506 85.905 34.560 ;
    END
  END rw0_rd_out[494]
  PIN rw0_rd_out[495]
    DIRECTION OUTPUT ;
    USE SIGNAL ;
    SHAPE ABUTMENT ;
    PORT
      LAYER M3 ;
      RECT 86.247 34.506 86.265 34.560 ;
    END
  END rw0_rd_out[495]
  PIN rw0_rd_out[496]
    DIRECTION OUTPUT ;
    USE SIGNAL ;
    SHAPE ABUTMENT ;
    PORT
      LAYER M3 ;
      RECT 86.607 34.506 86.625 34.560 ;
    END
  END rw0_rd_out[496]
  PIN rw0_rd_out[497]
    DIRECTION OUTPUT ;
    USE SIGNAL ;
    SHAPE ABUTMENT ;
    PORT
      LAYER M3 ;
      RECT 86.967 34.506 86.985 34.560 ;
    END
  END rw0_rd_out[497]
  PIN rw0_rd_out[498]
    DIRECTION OUTPUT ;
    USE SIGNAL ;
    SHAPE ABUTMENT ;
    PORT
      LAYER M3 ;
      RECT 87.327 34.506 87.345 34.560 ;
    END
  END rw0_rd_out[498]
  PIN rw0_rd_out[499]
    DIRECTION OUTPUT ;
    USE SIGNAL ;
    SHAPE ABUTMENT ;
    PORT
      LAYER M3 ;
      RECT 87.687 34.506 87.705 34.560 ;
    END
  END rw0_rd_out[499]
  PIN rw0_rd_out[500]
    DIRECTION OUTPUT ;
    USE SIGNAL ;
    SHAPE ABUTMENT ;
    PORT
      LAYER M3 ;
      RECT 88.047 34.506 88.065 34.560 ;
    END
  END rw0_rd_out[500]
  PIN rw0_rd_out[501]
    DIRECTION OUTPUT ;
    USE SIGNAL ;
    SHAPE ABUTMENT ;
    PORT
      LAYER M3 ;
      RECT 88.407 34.506 88.425 34.560 ;
    END
  END rw0_rd_out[501]
  PIN rw0_rd_out[502]
    DIRECTION OUTPUT ;
    USE SIGNAL ;
    SHAPE ABUTMENT ;
    PORT
      LAYER M3 ;
      RECT 88.767 34.506 88.785 34.560 ;
    END
  END rw0_rd_out[502]
  PIN rw0_rd_out[503]
    DIRECTION OUTPUT ;
    USE SIGNAL ;
    SHAPE ABUTMENT ;
    PORT
      LAYER M3 ;
      RECT 89.127 34.506 89.145 34.560 ;
    END
  END rw0_rd_out[503]
  PIN rw0_rd_out[504]
    DIRECTION OUTPUT ;
    USE SIGNAL ;
    SHAPE ABUTMENT ;
    PORT
      LAYER M3 ;
      RECT 89.487 34.506 89.505 34.560 ;
    END
  END rw0_rd_out[504]
  PIN rw0_rd_out[505]
    DIRECTION OUTPUT ;
    USE SIGNAL ;
    SHAPE ABUTMENT ;
    PORT
      LAYER M3 ;
      RECT 89.847 34.506 89.865 34.560 ;
    END
  END rw0_rd_out[505]
  PIN rw0_rd_out[506]
    DIRECTION OUTPUT ;
    USE SIGNAL ;
    SHAPE ABUTMENT ;
    PORT
      LAYER M3 ;
      RECT 90.207 34.506 90.225 34.560 ;
    END
  END rw0_rd_out[506]
  PIN rw0_rd_out[507]
    DIRECTION OUTPUT ;
    USE SIGNAL ;
    SHAPE ABUTMENT ;
    PORT
      LAYER M3 ;
      RECT 90.567 34.506 90.585 34.560 ;
    END
  END rw0_rd_out[507]
  PIN rw0_rd_out[508]
    DIRECTION OUTPUT ;
    USE SIGNAL ;
    SHAPE ABUTMENT ;
    PORT
      LAYER M3 ;
      RECT 90.927 34.506 90.945 34.560 ;
    END
  END rw0_rd_out[508]
  PIN rw0_rd_out[509]
    DIRECTION OUTPUT ;
    USE SIGNAL ;
    SHAPE ABUTMENT ;
    PORT
      LAYER M3 ;
      RECT 91.287 34.506 91.305 34.560 ;
    END
  END rw0_rd_out[509]
  PIN rw0_rd_out[510]
    DIRECTION OUTPUT ;
    USE SIGNAL ;
    SHAPE ABUTMENT ;
    PORT
      LAYER M3 ;
      RECT 91.647 34.506 91.665 34.560 ;
    END
  END rw0_rd_out[510]
  PIN rw0_rd_out[511]
    DIRECTION OUTPUT ;
    USE SIGNAL ;
    SHAPE ABUTMENT ;
    PORT
      LAYER M3 ;
      RECT 92.007 34.506 92.025 34.560 ;
    END
  END rw0_rd_out[511]
  PIN rw0_addr_in[0]
    DIRECTION INPUT ;
    USE SIGNAL ;
    SHAPE ABUTMENT ;
    PORT
      LAYER M4 ;
      RECT 0.000 30.996 0.072 31.020 ;
    END
  END rw0_addr_in[0]
  PIN rw0_addr_in[1]
    DIRECTION INPUT ;
    USE SIGNAL ;
    SHAPE ABUTMENT ;
    PORT
      LAYER M4 ;
      RECT 0.000 31.236 0.072 31.260 ;
    END
  END rw0_addr_in[1]
  PIN rw0_addr_in[2]
    DIRECTION INPUT ;
    USE SIGNAL ;
    SHAPE ABUTMENT ;
    PORT
      LAYER M4 ;
      RECT 0.000 31.476 0.072 31.500 ;
    END
  END rw0_addr_in[2]
  PIN rw0_addr_in[3]
    DIRECTION INPUT ;
    USE SIGNAL ;
    SHAPE ABUTMENT ;
    PORT
      LAYER M4 ;
      RECT 99.461 30.996 99.533 31.020 ;
    END
  END rw0_addr_in[3]
  PIN rw0_addr_in[4]
    DIRECTION INPUT ;
    USE SIGNAL ;
    SHAPE ABUTMENT ;
    PORT
      LAYER M4 ;
      RECT 99.461 31.236 99.533 31.260 ;
    END
  END rw0_addr_in[4]
  PIN rw0_addr_in[5]
    DIRECTION INPUT ;
    USE SIGNAL ;
    SHAPE ABUTMENT ;
    PORT
      LAYER M4 ;
      RECT 99.461 31.476 99.533 31.500 ;
    END
  END rw0_addr_in[5]
  PIN rw0_we_in
    DIRECTION INPUT ;
    USE SIGNAL ;
    SHAPE ABUTMENT ;
    PORT
      LAYER M3 ;
      RECT 92.367 34.506 92.385 34.560 ;
    END
  END rw0_we_in
  PIN rw0_ce_in
    DIRECTION INPUT ;
    USE SIGNAL ;
    SHAPE ABUTMENT ;
    PORT
      LAYER M3 ;
      RECT 92.727 34.506 92.745 34.560 ;
    END
  END rw0_ce_in
  PIN rw0_clk
    DIRECTION INPUT ;
    USE SIGNAL ;
    SHAPE ABUTMENT ;
    PORT
      LAYER M3 ;
      RECT 93.087 34.506 93.105 34.560 ;
    END
  END rw0_clk
  PIN VSS
    DIRECTION INOUT ;
    USE GROUND ;
    PORT
      LAYER M4 ;
      RECT 0.216 0.240 99.317 0.336 ;
      RECT 0.216 1.008 99.317 1.104 ;
      RECT 0.216 1.776 99.317 1.872 ;
      RECT 0.216 2.544 99.317 2.640 ;
      RECT 0.216 3.312 99.317 3.408 ;
      RECT 0.216 4.080 99.317 4.176 ;
      RECT 0.216 4.848 99.317 4.944 ;
      RECT 0.216 5.616 99.317 5.712 ;
      RECT 0.216 6.384 99.317 6.480 ;
      RECT 0.216 7.152 99.317 7.248 ;
      RECT 0.216 7.920 99.317 8.016 ;
      RECT 0.216 8.688 99.317 8.784 ;
      RECT 0.216 9.456 99.317 9.552 ;
      RECT 0.216 10.224 99.317 10.320 ;
      RECT 0.216 10.992 99.317 11.088 ;
      RECT 0.216 11.760 99.317 11.856 ;
      RECT 0.216 12.528 99.317 12.624 ;
      RECT 0.216 13.296 99.317 13.392 ;
      RECT 0.216 14.064 99.317 14.160 ;
      RECT 0.216 14.832 99.317 14.928 ;
      RECT 0.216 15.600 99.317 15.696 ;
      RECT 0.216 16.368 99.317 16.464 ;
      RECT 0.216 17.136 99.317 17.232 ;
      RECT 0.216 17.904 99.317 18.000 ;
      RECT 0.216 18.672 99.317 18.768 ;
      RECT 0.216 19.440 99.317 19.536 ;
      RECT 0.216 20.208 99.317 20.304 ;
      RECT 0.216 20.976 99.317 21.072 ;
      RECT 0.216 21.744 99.317 21.840 ;
      RECT 0.216 22.512 99.317 22.608 ;
      RECT 0.216 23.280 99.317 23.376 ;
      RECT 0.216 24.048 99.317 24.144 ;
      RECT 0.216 24.816 99.317 24.912 ;
      RECT 0.216 25.584 99.317 25.680 ;
      RECT 0.216 26.352 99.317 26.448 ;
      RECT 0.216 27.120 99.317 27.216 ;
      RECT 0.216 27.888 99.317 27.984 ;
      RECT 0.216 28.656 99.317 28.752 ;
      RECT 0.216 29.424 99.317 29.520 ;
      RECT 0.216 30.192 99.317 30.288 ;
      RECT 0.216 30.960 99.317 31.056 ;
      RECT 0.216 31.728 99.317 31.824 ;
      RECT 0.216 32.496 99.317 32.592 ;
      RECT 0.216 33.264 99.317 33.360 ;
      RECT 0.216 34.032 99.317 34.128 ;
    END
  END VSS
  PIN VDD
    DIRECTION INOUT ;
    USE POWER ;
    PORT
      LAYER M4 ;
      RECT 0.216 0.240 99.317 0.336 ;
      RECT 0.216 1.008 99.317 1.104 ;
      RECT 0.216 1.776 99.317 1.872 ;
      RECT 0.216 2.544 99.317 2.640 ;
      RECT 0.216 3.312 99.317 3.408 ;
      RECT 0.216 4.080 99.317 4.176 ;
      RECT 0.216 4.848 99.317 4.944 ;
      RECT 0.216 5.616 99.317 5.712 ;
      RECT 0.216 6.384 99.317 6.480 ;
      RECT 0.216 7.152 99.317 7.248 ;
      RECT 0.216 7.920 99.317 8.016 ;
      RECT 0.216 8.688 99.317 8.784 ;
      RECT 0.216 9.456 99.317 9.552 ;
      RECT 0.216 10.224 99.317 10.320 ;
      RECT 0.216 10.992 99.317 11.088 ;
      RECT 0.216 11.760 99.317 11.856 ;
      RECT 0.216 12.528 99.317 12.624 ;
      RECT 0.216 13.296 99.317 13.392 ;
      RECT 0.216 14.064 99.317 14.160 ;
      RECT 0.216 14.832 99.317 14.928 ;
      RECT 0.216 15.600 99.317 15.696 ;
      RECT 0.216 16.368 99.317 16.464 ;
      RECT 0.216 17.136 99.317 17.232 ;
      RECT 0.216 17.904 99.317 18.000 ;
      RECT 0.216 18.672 99.317 18.768 ;
      RECT 0.216 19.440 99.317 19.536 ;
      RECT 0.216 20.208 99.317 20.304 ;
      RECT 0.216 20.976 99.317 21.072 ;
      RECT 0.216 21.744 99.317 21.840 ;
      RECT 0.216 22.512 99.317 22.608 ;
      RECT 0.216 23.280 99.317 23.376 ;
      RECT 0.216 24.048 99.317 24.144 ;
      RECT 0.216 24.816 99.317 24.912 ;
      RECT 0.216 25.584 99.317 25.680 ;
      RECT 0.216 26.352 99.317 26.448 ;
      RECT 0.216 27.120 99.317 27.216 ;
      RECT 0.216 27.888 99.317 27.984 ;
      RECT 0.216 28.656 99.317 28.752 ;
      RECT 0.216 29.424 99.317 29.520 ;
      RECT 0.216 30.192 99.317 30.288 ;
      RECT 0.216 30.960 99.317 31.056 ;
      RECT 0.216 31.728 99.317 31.824 ;
      RECT 0.216 32.496 99.317 32.592 ;
      RECT 0.216 33.264 99.317 33.360 ;
      RECT 0.216 34.032 99.317 34.128 ;
    END
  END VDD
  OBS
    LAYER M1 ;
    RECT 0 0 99.533 34.560 ;
    LAYER M2 ;
    RECT 0 0 99.533 34.560 ;
    LAYER M3 ;
    RECT 0 0 99.533 34.560 ;
    LAYER M4 ;
    RECT 0 0 99.533 34.560 ;
  END
END fakeram7_64x512

END LIBRARY
